VERSION 5.7 ;
  NOWIREEXTENSIONATPIN ON ;
  DIVIDERCHAR "/" ;
  BUSBITCHARS "[]" ;
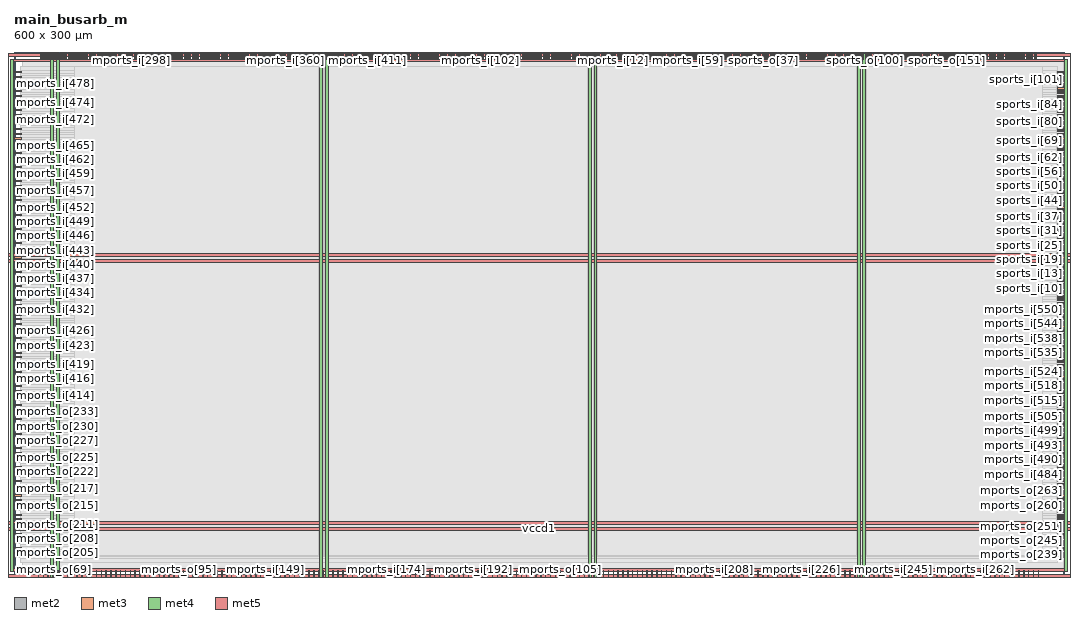
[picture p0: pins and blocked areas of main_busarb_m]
MACRO main_busarb_m
  CLASS BLOCK ;
  FOREIGN main_busarb_m ;
  ORIGIN 0.000 0.000 ;
  SIZE 600.000 BY 300.000 ;
  PIN clk_i
    DIRECTION INPUT ;
    USE SIGNAL ;
    ANTENNAGATEAREA 0.852000 ;
    ANTENNADIFFAREA 0.434700 ;
    PORT
      LAYER met2 ;
        RECT 13.890 0.000 14.170 4.000 ;
    END
  END clk_i
  PIN mports_i[0]
    DIRECTION INPUT ;
    USE SIGNAL ;
    ANTENNAGATEAREA 0.159000 ;
    PORT
      LAYER met2 ;
        RECT 330.830 296.000 331.110 300.000 ;
    END
  END mports_i[0]
  PIN mports_i[100]
    DIRECTION INPUT ;
    USE SIGNAL ;
    ANTENNAGATEAREA 0.196500 ;
    PORT
      LAYER met2 ;
        RECT 264.590 296.000 264.870 300.000 ;
    END
  END mports_i[100]
  PIN mports_i[101]
    DIRECTION INPUT ;
    USE SIGNAL ;
    ANTENNAGATEAREA 0.196500 ;
    PORT
      LAYER met2 ;
        RECT 265.510 296.000 265.790 300.000 ;
    END
  END mports_i[101]
  PIN mports_i[102]
    DIRECTION INPUT ;
    USE SIGNAL ;
    ANTENNAGATEAREA 0.126000 ;
    PORT
      LAYER met2 ;
        RECT 266.430 296.000 266.710 300.000 ;
    END
  END mports_i[102]
  PIN mports_i[103]
    DIRECTION INPUT ;
    USE SIGNAL ;
    ANTENNAGATEAREA 0.213000 ;
    PORT
      LAYER met2 ;
        RECT 267.350 296.000 267.630 300.000 ;
    END
  END mports_i[103]
  PIN mports_i[104]
    DIRECTION INPUT ;
    USE SIGNAL ;
    ANTENNAGATEAREA 0.159000 ;
    PORT
      LAYER met2 ;
        RECT 268.270 296.000 268.550 300.000 ;
    END
  END mports_i[104]
  PIN mports_i[105]
    DIRECTION INPUT ;
    USE SIGNAL ;
    ANTENNAGATEAREA 0.196500 ;
    PORT
      LAYER met2 ;
        RECT 269.190 296.000 269.470 300.000 ;
    END
  END mports_i[105]
  PIN mports_i[106]
    DIRECTION INPUT ;
    USE SIGNAL ;
    ANTENNAGATEAREA 0.196500 ;
    PORT
      LAYER met2 ;
        RECT 270.110 296.000 270.390 300.000 ;
    END
  END mports_i[106]
  PIN mports_i[107]
    DIRECTION INPUT ;
    USE SIGNAL ;
    ANTENNAGATEAREA 0.196500 ;
    PORT
      LAYER met2 ;
        RECT 271.030 296.000 271.310 300.000 ;
    END
  END mports_i[107]
  PIN mports_i[108]
    DIRECTION INPUT ;
    USE SIGNAL ;
    ANTENNAGATEAREA 0.196500 ;
    PORT
      LAYER met2 ;
        RECT 271.950 296.000 272.230 300.000 ;
    END
  END mports_i[108]
  PIN mports_i[109]
    DIRECTION INPUT ;
    USE SIGNAL ;
    ANTENNAGATEAREA 0.196500 ;
    PORT
      LAYER met2 ;
        RECT 272.870 296.000 273.150 300.000 ;
    END
  END mports_i[109]
  PIN mports_i[10]
    DIRECTION INPUT ;
    USE SIGNAL ;
    ANTENNAGATEAREA 0.159000 ;
    PORT
      LAYER met2 ;
        RECT 340.030 296.000 340.310 300.000 ;
    END
  END mports_i[10]
  PIN mports_i[110]
    DIRECTION INPUT ;
    USE SIGNAL ;
    ANTENNAGATEAREA 0.126000 ;
    PORT
      LAYER met2 ;
        RECT 273.790 296.000 274.070 300.000 ;
    END
  END mports_i[110]
  PIN mports_i[111]
    DIRECTION INPUT ;
    USE SIGNAL ;
    ANTENNAGATEAREA 0.196500 ;
    PORT
      LAYER met2 ;
        RECT 274.710 296.000 274.990 300.000 ;
    END
  END mports_i[111]
  PIN mports_i[112]
    DIRECTION INPUT ;
    USE SIGNAL ;
    ANTENNAGATEAREA 0.213000 ;
    PORT
      LAYER met2 ;
        RECT 275.630 296.000 275.910 300.000 ;
    END
  END mports_i[112]
  PIN mports_i[113]
    DIRECTION INPUT ;
    USE SIGNAL ;
    ANTENNAGATEAREA 0.213000 ;
    PORT
      LAYER met2 ;
        RECT 276.550 296.000 276.830 300.000 ;
    END
  END mports_i[113]
  PIN mports_i[114]
    DIRECTION INPUT ;
    USE SIGNAL ;
    ANTENNAGATEAREA 0.126000 ;
    PORT
      LAYER met2 ;
        RECT 277.470 296.000 277.750 300.000 ;
    END
  END mports_i[114]
  PIN mports_i[115]
    DIRECTION INPUT ;
    USE SIGNAL ;
    ANTENNAGATEAREA 0.159000 ;
    PORT
      LAYER met2 ;
        RECT 278.390 296.000 278.670 300.000 ;
    END
  END mports_i[115]
  PIN mports_i[116]
    DIRECTION INPUT ;
    USE SIGNAL ;
    ANTENNAGATEAREA 0.196500 ;
    PORT
      LAYER met2 ;
        RECT 279.310 296.000 279.590 300.000 ;
    END
  END mports_i[116]
  PIN mports_i[117]
    DIRECTION INPUT ;
    USE SIGNAL ;
    ANTENNAGATEAREA 0.196500 ;
    PORT
      LAYER met2 ;
        RECT 280.230 296.000 280.510 300.000 ;
    END
  END mports_i[117]
  PIN mports_i[118]
    DIRECTION INPUT ;
    USE SIGNAL ;
    ANTENNAGATEAREA 0.159000 ;
    PORT
      LAYER met2 ;
        RECT 281.150 296.000 281.430 300.000 ;
    END
  END mports_i[118]
  PIN mports_i[119]
    DIRECTION INPUT ;
    USE SIGNAL ;
    ANTENNAGATEAREA 0.196500 ;
    PORT
      LAYER met2 ;
        RECT 282.070 296.000 282.350 300.000 ;
    END
  END mports_i[119]
  PIN mports_i[11]
    DIRECTION INPUT ;
    USE SIGNAL ;
    ANTENNAGATEAREA 0.159000 ;
    PORT
      LAYER met2 ;
        RECT 340.950 296.000 341.230 300.000 ;
    END
  END mports_i[11]
  PIN mports_i[120]
    DIRECTION INPUT ;
    USE SIGNAL ;
    ANTENNAGATEAREA 0.196500 ;
    PORT
      LAYER met2 ;
        RECT 282.990 296.000 283.270 300.000 ;
    END
  END mports_i[120]
  PIN mports_i[121]
    DIRECTION INPUT ;
    USE SIGNAL ;
    ANTENNAGATEAREA 0.196500 ;
    PORT
      LAYER met2 ;
        RECT 283.910 296.000 284.190 300.000 ;
    END
  END mports_i[121]
  PIN mports_i[122]
    DIRECTION INPUT ;
    USE SIGNAL ;
    ANTENNAGATEAREA 0.213000 ;
    PORT
      LAYER met2 ;
        RECT 284.830 296.000 285.110 300.000 ;
    END
  END mports_i[122]
  PIN mports_i[123]
    DIRECTION INPUT ;
    USE SIGNAL ;
    ANTENNAGATEAREA 0.196500 ;
    PORT
      LAYER met2 ;
        RECT 285.750 296.000 286.030 300.000 ;
    END
  END mports_i[123]
  PIN mports_i[124]
    DIRECTION INPUT ;
    USE SIGNAL ;
    ANTENNAGATEAREA 0.196500 ;
    PORT
      LAYER met2 ;
        RECT 286.670 296.000 286.950 300.000 ;
    END
  END mports_i[124]
  PIN mports_i[125]
    DIRECTION INPUT ;
    USE SIGNAL ;
    ANTENNAGATEAREA 0.159000 ;
    PORT
      LAYER met2 ;
        RECT 287.590 296.000 287.870 300.000 ;
    END
  END mports_i[125]
  PIN mports_i[126]
    DIRECTION INPUT ;
    USE SIGNAL ;
    ANTENNAGATEAREA 0.196500 ;
    PORT
      LAYER met2 ;
        RECT 288.510 296.000 288.790 300.000 ;
    END
  END mports_i[126]
  PIN mports_i[127]
    DIRECTION INPUT ;
    USE SIGNAL ;
    ANTENNAGATEAREA 0.196500 ;
    PORT
      LAYER met2 ;
        RECT 289.430 296.000 289.710 300.000 ;
    END
  END mports_i[127]
  PIN mports_i[128]
    DIRECTION INPUT ;
    USE SIGNAL ;
    ANTENNAGATEAREA 0.126000 ;
    PORT
      LAYER met2 ;
        RECT 290.350 296.000 290.630 300.000 ;
    END
  END mports_i[128]
  PIN mports_i[129]
    DIRECTION INPUT ;
    USE SIGNAL ;
    ANTENNAGATEAREA 0.126000 ;
    PORT
      LAYER met2 ;
        RECT 291.270 296.000 291.550 300.000 ;
    END
  END mports_i[129]
  PIN mports_i[12]
    DIRECTION INPUT ;
    USE SIGNAL ;
    ANTENNAGATEAREA 0.159000 ;
    PORT
      LAYER met2 ;
        RECT 341.870 296.000 342.150 300.000 ;
    END
  END mports_i[12]
  PIN mports_i[130]
    DIRECTION INPUT ;
    USE SIGNAL ;
    ANTENNAGATEAREA 0.213000 ;
    PORT
      LAYER met2 ;
        RECT 292.190 296.000 292.470 300.000 ;
    END
  END mports_i[130]
  PIN mports_i[131]
    DIRECTION INPUT ;
    USE SIGNAL ;
    ANTENNAGATEAREA 0.159000 ;
    PORT
      LAYER met2 ;
        RECT 293.110 296.000 293.390 300.000 ;
    END
  END mports_i[131]
  PIN mports_i[132]
    DIRECTION INPUT ;
    USE SIGNAL ;
    ANTENNAGATEAREA 0.213000 ;
    PORT
      LAYER met2 ;
        RECT 294.030 296.000 294.310 300.000 ;
    END
  END mports_i[132]
  PIN mports_i[133]
    DIRECTION INPUT ;
    USE SIGNAL ;
    ANTENNAGATEAREA 0.247500 ;
    PORT
      LAYER met2 ;
        RECT 294.950 296.000 295.230 300.000 ;
    END
  END mports_i[133]
  PIN mports_i[134]
    DIRECTION INPUT ;
    USE SIGNAL ;
    ANTENNAGATEAREA 0.213000 ;
    PORT
      LAYER met2 ;
        RECT 295.870 296.000 296.150 300.000 ;
    END
  END mports_i[134]
  PIN mports_i[135]
    DIRECTION INPUT ;
    USE SIGNAL ;
    ANTENNAGATEAREA 0.213000 ;
    PORT
      LAYER met2 ;
        RECT 296.790 296.000 297.070 300.000 ;
    END
  END mports_i[135]
  PIN mports_i[136]
    DIRECTION INPUT ;
    USE SIGNAL ;
    ANTENNAGATEAREA 0.196500 ;
    PORT
      LAYER met2 ;
        RECT 297.710 296.000 297.990 300.000 ;
    END
  END mports_i[136]
  PIN mports_i[137]
    DIRECTION INPUT ;
    USE SIGNAL ;
    ANTENNAGATEAREA 0.126000 ;
    PORT
      LAYER met2 ;
        RECT 298.630 296.000 298.910 300.000 ;
    END
  END mports_i[137]
  PIN mports_i[138]
    DIRECTION INPUT ;
    USE SIGNAL ;
    ANTENNAGATEAREA 0.159000 ;
    PORT
      LAYER met2 ;
        RECT 113.250 0.000 113.530 4.000 ;
    END
  END mports_i[138]
  PIN mports_i[139]
    DIRECTION INPUT ;
    USE SIGNAL ;
    ANTENNAGATEAREA 0.159000 ;
    PORT
      LAYER met2 ;
        RECT 116.010 0.000 116.290 4.000 ;
    END
  END mports_i[139]
  PIN mports_i[13]
    DIRECTION INPUT ;
    USE SIGNAL ;
    ANTENNAGATEAREA 0.159000 ;
    PORT
      LAYER met2 ;
        RECT 342.790 296.000 343.070 300.000 ;
    END
  END mports_i[13]
  PIN mports_i[140]
    DIRECTION INPUT ;
    USE SIGNAL ;
    ANTENNAGATEAREA 0.213000 ;
    PORT
      LAYER met2 ;
        RECT 118.770 0.000 119.050 4.000 ;
    END
  END mports_i[140]
  PIN mports_i[141]
    DIRECTION INPUT ;
    USE SIGNAL ;
    ANTENNAGATEAREA 0.213000 ;
    PORT
      LAYER met2 ;
        RECT 121.530 0.000 121.810 4.000 ;
    END
  END mports_i[141]
  PIN mports_i[142]
    DIRECTION INPUT ;
    USE SIGNAL ;
    ANTENNAGATEAREA 0.159000 ;
    PORT
      LAYER met2 ;
        RECT 124.290 0.000 124.570 4.000 ;
    END
  END mports_i[142]
  PIN mports_i[143]
    DIRECTION INPUT ;
    USE SIGNAL ;
    ANTENNAGATEAREA 0.213000 ;
    PORT
      LAYER met2 ;
        RECT 127.050 0.000 127.330 4.000 ;
    END
  END mports_i[143]
  PIN mports_i[144]
    DIRECTION INPUT ;
    USE SIGNAL ;
    ANTENNAGATEAREA 0.159000 ;
    PORT
      LAYER met2 ;
        RECT 129.810 0.000 130.090 4.000 ;
    END
  END mports_i[144]
  PIN mports_i[145]
    DIRECTION INPUT ;
    USE SIGNAL ;
    ANTENNAGATEAREA 0.159000 ;
    PORT
      LAYER met2 ;
        RECT 132.570 0.000 132.850 4.000 ;
    END
  END mports_i[145]
  PIN mports_i[146]
    DIRECTION INPUT ;
    USE SIGNAL ;
    ANTENNAGATEAREA 0.213000 ;
    PORT
      LAYER met2 ;
        RECT 135.330 0.000 135.610 4.000 ;
    END
  END mports_i[146]
  PIN mports_i[147]
    DIRECTION INPUT ;
    USE SIGNAL ;
    ANTENNAGATEAREA 0.213000 ;
    PORT
      LAYER met2 ;
        RECT 138.090 0.000 138.370 4.000 ;
    END
  END mports_i[147]
  PIN mports_i[148]
    DIRECTION INPUT ;
    USE SIGNAL ;
    ANTENNAGATEAREA 0.213000 ;
    PORT
      LAYER met2 ;
        RECT 140.850 0.000 141.130 4.000 ;
    END
  END mports_i[148]
  PIN mports_i[149]
    DIRECTION INPUT ;
    USE SIGNAL ;
    ANTENNAGATEAREA 0.213000 ;
    PORT
      LAYER met2 ;
        RECT 143.610 0.000 143.890 4.000 ;
    END
  END mports_i[149]
  PIN mports_i[14]
    DIRECTION INPUT ;
    USE SIGNAL ;
    ANTENNAGATEAREA 0.159000 ;
    PORT
      LAYER met2 ;
        RECT 343.710 296.000 343.990 300.000 ;
    END
  END mports_i[14]
  PIN mports_i[150]
    DIRECTION INPUT ;
    USE SIGNAL ;
    ANTENNAGATEAREA 0.213000 ;
    PORT
      LAYER met2 ;
        RECT 146.370 0.000 146.650 4.000 ;
    END
  END mports_i[150]
  PIN mports_i[151]
    DIRECTION INPUT ;
    USE SIGNAL ;
    ANTENNAGATEAREA 0.213000 ;
    PORT
      LAYER met2 ;
        RECT 149.130 0.000 149.410 4.000 ;
    END
  END mports_i[151]
  PIN mports_i[152]
    DIRECTION INPUT ;
    USE SIGNAL ;
    ANTENNAGATEAREA 0.159000 ;
    PORT
      LAYER met2 ;
        RECT 151.890 0.000 152.170 4.000 ;
    END
  END mports_i[152]
  PIN mports_i[153]
    DIRECTION INPUT ;
    USE SIGNAL ;
    ANTENNAGATEAREA 0.213000 ;
    PORT
      LAYER met2 ;
        RECT 154.650 0.000 154.930 4.000 ;
    END
  END mports_i[153]
  PIN mports_i[154]
    DIRECTION INPUT ;
    USE SIGNAL ;
    ANTENNAGATEAREA 0.159000 ;
    PORT
      LAYER met2 ;
        RECT 157.410 0.000 157.690 4.000 ;
    END
  END mports_i[154]
  PIN mports_i[155]
    DIRECTION INPUT ;
    USE SIGNAL ;
    ANTENNAGATEAREA 0.159000 ;
    PORT
      LAYER met2 ;
        RECT 160.170 0.000 160.450 4.000 ;
    END
  END mports_i[155]
  PIN mports_i[156]
    DIRECTION INPUT ;
    USE SIGNAL ;
    ANTENNAGATEAREA 0.213000 ;
    PORT
      LAYER met2 ;
        RECT 162.930 0.000 163.210 4.000 ;
    END
  END mports_i[156]
  PIN mports_i[157]
    DIRECTION INPUT ;
    USE SIGNAL ;
    ANTENNAGATEAREA 0.213000 ;
    PORT
      LAYER met2 ;
        RECT 165.690 0.000 165.970 4.000 ;
    END
  END mports_i[157]
  PIN mports_i[158]
    DIRECTION INPUT ;
    USE SIGNAL ;
    ANTENNAGATEAREA 0.213000 ;
    PORT
      LAYER met2 ;
        RECT 168.450 0.000 168.730 4.000 ;
    END
  END mports_i[158]
  PIN mports_i[159]
    DIRECTION INPUT ;
    USE SIGNAL ;
    ANTENNAGATEAREA 0.213000 ;
    PORT
      LAYER met2 ;
        RECT 171.210 0.000 171.490 4.000 ;
    END
  END mports_i[159]
  PIN mports_i[15]
    DIRECTION INPUT ;
    USE SIGNAL ;
    ANTENNAGATEAREA 0.213000 ;
    PORT
      LAYER met2 ;
        RECT 344.630 296.000 344.910 300.000 ;
    END
  END mports_i[15]
  PIN mports_i[160]
    DIRECTION INPUT ;
    USE SIGNAL ;
    ANTENNAGATEAREA 0.159000 ;
    PORT
      LAYER met2 ;
        RECT 173.970 0.000 174.250 4.000 ;
    END
  END mports_i[160]
  PIN mports_i[161]
    DIRECTION INPUT ;
    USE SIGNAL ;
    ANTENNAGATEAREA 0.213000 ;
    PORT
      LAYER met2 ;
        RECT 176.730 0.000 177.010 4.000 ;
    END
  END mports_i[161]
  PIN mports_i[162]
    DIRECTION INPUT ;
    USE SIGNAL ;
    ANTENNAGATEAREA 0.213000 ;
    PORT
      LAYER met2 ;
        RECT 179.490 0.000 179.770 4.000 ;
    END
  END mports_i[162]
  PIN mports_i[163]
    DIRECTION INPUT ;
    USE SIGNAL ;
    ANTENNAGATEAREA 0.213000 ;
    PORT
      LAYER met2 ;
        RECT 182.250 0.000 182.530 4.000 ;
    END
  END mports_i[163]
  PIN mports_i[164]
    DIRECTION INPUT ;
    USE SIGNAL ;
    ANTENNAGATEAREA 0.213000 ;
    PORT
      LAYER met2 ;
        RECT 185.010 0.000 185.290 4.000 ;
    END
  END mports_i[164]
  PIN mports_i[165]
    DIRECTION INPUT ;
    USE SIGNAL ;
    ANTENNAGATEAREA 0.213000 ;
    PORT
      LAYER met2 ;
        RECT 187.770 0.000 188.050 4.000 ;
    END
  END mports_i[165]
  PIN mports_i[166]
    DIRECTION INPUT ;
    USE SIGNAL ;
    ANTENNAGATEAREA 0.213000 ;
    PORT
      LAYER met2 ;
        RECT 190.530 0.000 190.810 4.000 ;
    END
  END mports_i[166]
  PIN mports_i[167]
    DIRECTION INPUT ;
    USE SIGNAL ;
    ANTENNAGATEAREA 0.213000 ;
    PORT
      LAYER met2 ;
        RECT 193.290 0.000 193.570 4.000 ;
    END
  END mports_i[167]
  PIN mports_i[168]
    DIRECTION INPUT ;
    USE SIGNAL ;
    ANTENNAGATEAREA 0.159000 ;
    PORT
      LAYER met2 ;
        RECT 196.050 0.000 196.330 4.000 ;
    END
  END mports_i[168]
  PIN mports_i[169]
    DIRECTION INPUT ;
    USE SIGNAL ;
    ANTENNAGATEAREA 0.213000 ;
    PORT
      LAYER met2 ;
        RECT 198.810 0.000 199.090 4.000 ;
    END
  END mports_i[169]
  PIN mports_i[16]
    DIRECTION INPUT ;
    USE SIGNAL ;
    ANTENNAGATEAREA 0.213000 ;
    PORT
      LAYER met2 ;
        RECT 345.550 296.000 345.830 300.000 ;
    END
  END mports_i[16]
  PIN mports_i[170]
    DIRECTION INPUT ;
    USE SIGNAL ;
    ANTENNAGATEAREA 0.213000 ;
    PORT
      LAYER met2 ;
        RECT 201.570 0.000 201.850 4.000 ;
    END
  END mports_i[170]
  PIN mports_i[171]
    DIRECTION INPUT ;
    USE SIGNAL ;
    ANTENNAGATEAREA 0.213000 ;
    PORT
      LAYER met2 ;
        RECT 204.330 0.000 204.610 4.000 ;
    END
  END mports_i[171]
  PIN mports_i[172]
    DIRECTION INPUT ;
    USE SIGNAL ;
    ANTENNAGATEAREA 0.159000 ;
    PORT
      LAYER met2 ;
        RECT 207.090 0.000 207.370 4.000 ;
    END
  END mports_i[172]
  PIN mports_i[173]
    DIRECTION INPUT ;
    USE SIGNAL ;
    ANTENNAGATEAREA 0.213000 ;
    PORT
      LAYER met2 ;
        RECT 209.850 0.000 210.130 4.000 ;
    END
  END mports_i[173]
  PIN mports_i[174]
    DIRECTION INPUT ;
    USE SIGNAL ;
    ANTENNAGATEAREA 0.159000 ;
    PORT
      LAYER met2 ;
        RECT 212.610 0.000 212.890 4.000 ;
    END
  END mports_i[174]
  PIN mports_i[175]
    DIRECTION INPUT ;
    USE SIGNAL ;
    ANTENNAGATEAREA 0.159000 ;
    PORT
      LAYER met2 ;
        RECT 215.370 0.000 215.650 4.000 ;
    END
  END mports_i[175]
  PIN mports_i[176]
    DIRECTION INPUT ;
    USE SIGNAL ;
    ANTENNAGATEAREA 0.159000 ;
    PORT
      LAYER met2 ;
        RECT 218.130 0.000 218.410 4.000 ;
    END
  END mports_i[176]
  PIN mports_i[177]
    DIRECTION INPUT ;
    USE SIGNAL ;
    ANTENNAGATEAREA 0.213000 ;
    PORT
      LAYER met2 ;
        RECT 220.890 0.000 221.170 4.000 ;
    END
  END mports_i[177]
  PIN mports_i[178]
    DIRECTION INPUT ;
    USE SIGNAL ;
    ANTENNAGATEAREA 0.213000 ;
    PORT
      LAYER met2 ;
        RECT 223.650 0.000 223.930 4.000 ;
    END
  END mports_i[178]
  PIN mports_i[179]
    DIRECTION INPUT ;
    USE SIGNAL ;
    ANTENNAGATEAREA 0.159000 ;
    PORT
      LAYER met2 ;
        RECT 226.410 0.000 226.690 4.000 ;
    END
  END mports_i[179]
  PIN mports_i[17]
    DIRECTION INPUT ;
    USE SIGNAL ;
    ANTENNAGATEAREA 0.159000 ;
    PORT
      LAYER met2 ;
        RECT 346.470 296.000 346.750 300.000 ;
    END
  END mports_i[17]
  PIN mports_i[180]
    DIRECTION INPUT ;
    USE SIGNAL ;
    ANTENNAGATEAREA 0.159000 ;
    PORT
      LAYER met2 ;
        RECT 229.170 0.000 229.450 4.000 ;
    END
  END mports_i[180]
  PIN mports_i[181]
    DIRECTION INPUT ;
    USE SIGNAL ;
    ANTENNAGATEAREA 0.159000 ;
    PORT
      LAYER met2 ;
        RECT 231.930 0.000 232.210 4.000 ;
    END
  END mports_i[181]
  PIN mports_i[182]
    DIRECTION INPUT ;
    USE SIGNAL ;
    ANTENNAGATEAREA 0.159000 ;
    PORT
      LAYER met2 ;
        RECT 234.690 0.000 234.970 4.000 ;
    END
  END mports_i[182]
  PIN mports_i[183]
    DIRECTION INPUT ;
    USE SIGNAL ;
    ANTENNAGATEAREA 0.213000 ;
    PORT
      LAYER met2 ;
        RECT 237.450 0.000 237.730 4.000 ;
    END
  END mports_i[183]
  PIN mports_i[184]
    DIRECTION INPUT ;
    USE SIGNAL ;
    ANTENNAGATEAREA 0.213000 ;
    PORT
      LAYER met2 ;
        RECT 240.210 0.000 240.490 4.000 ;
    END
  END mports_i[184]
  PIN mports_i[185]
    DIRECTION INPUT ;
    USE SIGNAL ;
    ANTENNAGATEAREA 0.159000 ;
    PORT
      LAYER met2 ;
        RECT 242.970 0.000 243.250 4.000 ;
    END
  END mports_i[185]
  PIN mports_i[186]
    DIRECTION INPUT ;
    USE SIGNAL ;
    ANTENNAGATEAREA 0.159000 ;
    PORT
      LAYER met2 ;
        RECT 245.730 0.000 246.010 4.000 ;
    END
  END mports_i[186]
  PIN mports_i[187]
    DIRECTION INPUT ;
    USE SIGNAL ;
    ANTENNAGATEAREA 0.213000 ;
    PORT
      LAYER met2 ;
        RECT 248.490 0.000 248.770 4.000 ;
    END
  END mports_i[187]
  PIN mports_i[188]
    DIRECTION INPUT ;
    USE SIGNAL ;
    ANTENNAGATEAREA 0.213000 ;
    PORT
      LAYER met2 ;
        RECT 251.250 0.000 251.530 4.000 ;
    END
  END mports_i[188]
  PIN mports_i[189]
    DIRECTION INPUT ;
    USE SIGNAL ;
    ANTENNAGATEAREA 0.159000 ;
    PORT
      LAYER met2 ;
        RECT 254.010 0.000 254.290 4.000 ;
    END
  END mports_i[189]
  PIN mports_i[18]
    DIRECTION INPUT ;
    USE SIGNAL ;
    ANTENNAGATEAREA 0.159000 ;
    PORT
      LAYER met2 ;
        RECT 347.390 296.000 347.670 300.000 ;
    END
  END mports_i[18]
  PIN mports_i[190]
    DIRECTION INPUT ;
    USE SIGNAL ;
    ANTENNAGATEAREA 0.159000 ;
    PORT
      LAYER met2 ;
        RECT 256.770 0.000 257.050 4.000 ;
    END
  END mports_i[190]
  PIN mports_i[191]
    DIRECTION INPUT ;
    USE SIGNAL ;
    ANTENNAGATEAREA 0.159000 ;
    PORT
      LAYER met2 ;
        RECT 259.530 0.000 259.810 4.000 ;
    END
  END mports_i[191]
  PIN mports_i[192]
    DIRECTION INPUT ;
    USE SIGNAL ;
    ANTENNAGATEAREA 0.159000 ;
    PORT
      LAYER met2 ;
        RECT 262.290 0.000 262.570 4.000 ;
    END
  END mports_i[192]
  PIN mports_i[193]
    DIRECTION INPUT ;
    USE SIGNAL ;
    ANTENNAGATEAREA 0.159000 ;
    PORT
      LAYER met2 ;
        RECT 265.050 0.000 265.330 4.000 ;
    END
  END mports_i[193]
  PIN mports_i[194]
    DIRECTION INPUT ;
    USE SIGNAL ;
    ANTENNAGATEAREA 0.213000 ;
    PORT
      LAYER met2 ;
        RECT 267.810 0.000 268.090 4.000 ;
    END
  END mports_i[194]
  PIN mports_i[195]
    DIRECTION INPUT ;
    USE SIGNAL ;
    ANTENNAGATEAREA 0.159000 ;
    PORT
      LAYER met2 ;
        RECT 270.570 0.000 270.850 4.000 ;
    END
  END mports_i[195]
  PIN mports_i[196]
    DIRECTION INPUT ;
    USE SIGNAL ;
    ANTENNAGATEAREA 0.159000 ;
    PORT
      LAYER met2 ;
        RECT 273.330 0.000 273.610 4.000 ;
    END
  END mports_i[196]
  PIN mports_i[197]
    DIRECTION INPUT ;
    USE SIGNAL ;
    ANTENNAGATEAREA 0.213000 ;
    PORT
      LAYER met2 ;
        RECT 276.090 0.000 276.370 4.000 ;
    END
  END mports_i[197]
  PIN mports_i[198]
    DIRECTION INPUT ;
    USE SIGNAL ;
    ANTENNAGATEAREA 0.213000 ;
    PORT
      LAYER met2 ;
        RECT 278.850 0.000 279.130 4.000 ;
    END
  END mports_i[198]
  PIN mports_i[199]
    DIRECTION INPUT ;
    USE SIGNAL ;
    ANTENNAGATEAREA 0.213000 ;
    PORT
      LAYER met2 ;
        RECT 281.610 0.000 281.890 4.000 ;
    END
  END mports_i[199]
  PIN mports_i[19]
    DIRECTION INPUT ;
    USE SIGNAL ;
    ANTENNAGATEAREA 0.213000 ;
    PORT
      LAYER met2 ;
        RECT 348.310 296.000 348.590 300.000 ;
    END
  END mports_i[19]
  PIN mports_i[1]
    DIRECTION INPUT ;
    USE SIGNAL ;
    ANTENNAGATEAREA 0.159000 ;
    PORT
      LAYER met2 ;
        RECT 331.750 296.000 332.030 300.000 ;
    END
  END mports_i[1]
  PIN mports_i[200]
    DIRECTION INPUT ;
    USE SIGNAL ;
    ANTENNAGATEAREA 0.213000 ;
    PORT
      LAYER met2 ;
        RECT 284.370 0.000 284.650 4.000 ;
    END
  END mports_i[200]
  PIN mports_i[201]
    DIRECTION INPUT ;
    USE SIGNAL ;
    ANTENNAGATEAREA 0.159000 ;
    PORT
      LAYER met2 ;
        RECT 287.130 0.000 287.410 4.000 ;
    END
  END mports_i[201]
  PIN mports_i[202]
    DIRECTION INPUT ;
    USE SIGNAL ;
    ANTENNAGATEAREA 0.213000 ;
    PORT
      LAYER met2 ;
        RECT 289.890 0.000 290.170 4.000 ;
    END
  END mports_i[202]
  PIN mports_i[203]
    DIRECTION INPUT ;
    USE SIGNAL ;
    ANTENNAGATEAREA 0.213000 ;
    PORT
      LAYER met2 ;
        RECT 292.650 0.000 292.930 4.000 ;
    END
  END mports_i[203]
  PIN mports_i[204]
    DIRECTION INPUT ;
    USE SIGNAL ;
    ANTENNAGATEAREA 0.159000 ;
    PORT
      LAYER met2 ;
        RECT 295.410 0.000 295.690 4.000 ;
    END
  END mports_i[204]
  PIN mports_i[205]
    DIRECTION INPUT ;
    USE SIGNAL ;
    ANTENNAGATEAREA 0.159000 ;
    PORT
      LAYER met2 ;
        RECT 298.170 0.000 298.450 4.000 ;
    END
  END mports_i[205]
  PIN mports_i[206]
    DIRECTION INPUT ;
    USE SIGNAL ;
    ANTENNAGATEAREA 0.159000 ;
    PORT
      LAYER met2 ;
        RECT 300.930 0.000 301.210 4.000 ;
    END
  END mports_i[206]
  PIN mports_i[207]
    DIRECTION INPUT ;
    USE SIGNAL ;
    ANTENNAGATEAREA 0.247500 ;
    PORT
      LAYER met2 ;
        RECT 397.530 0.000 397.810 4.000 ;
    END
  END mports_i[207]
  PIN mports_i[208]
    DIRECTION INPUT ;
    USE SIGNAL ;
    ANTENNAGATEAREA 0.247500 ;
    PORT
      LAYER met2 ;
        RECT 400.290 0.000 400.570 4.000 ;
    END
  END mports_i[208]
  PIN mports_i[209]
    DIRECTION INPUT ;
    USE SIGNAL ;
    ANTENNAGATEAREA 0.247500 ;
    PORT
      LAYER met2 ;
        RECT 403.050 0.000 403.330 4.000 ;
    END
  END mports_i[209]
  PIN mports_i[20]
    DIRECTION INPUT ;
    USE SIGNAL ;
    ANTENNAGATEAREA 0.159000 ;
    PORT
      LAYER met2 ;
        RECT 349.230 296.000 349.510 300.000 ;
    END
  END mports_i[20]
  PIN mports_i[210]
    DIRECTION INPUT ;
    USE SIGNAL ;
    ANTENNAGATEAREA 0.213000 ;
    PORT
      LAYER met2 ;
        RECT 405.810 0.000 406.090 4.000 ;
    END
  END mports_i[210]
  PIN mports_i[211]
    DIRECTION INPUT ;
    USE SIGNAL ;
    ANTENNAGATEAREA 0.213000 ;
    PORT
      LAYER met2 ;
        RECT 408.570 0.000 408.850 4.000 ;
    END
  END mports_i[211]
  PIN mports_i[212]
    DIRECTION INPUT ;
    USE SIGNAL ;
    ANTENNAGATEAREA 0.247500 ;
    PORT
      LAYER met2 ;
        RECT 411.330 0.000 411.610 4.000 ;
    END
  END mports_i[212]
  PIN mports_i[213]
    DIRECTION INPUT ;
    USE SIGNAL ;
    ANTENNAGATEAREA 0.247500 ;
    PORT
      LAYER met2 ;
        RECT 414.090 0.000 414.370 4.000 ;
    END
  END mports_i[213]
  PIN mports_i[214]
    DIRECTION INPUT ;
    USE SIGNAL ;
    ANTENNAGATEAREA 0.247500 ;
    PORT
      LAYER met2 ;
        RECT 416.850 0.000 417.130 4.000 ;
    END
  END mports_i[214]
  PIN mports_i[215]
    DIRECTION INPUT ;
    USE SIGNAL ;
    ANTENNAGATEAREA 0.247500 ;
    PORT
      LAYER met2 ;
        RECT 419.610 0.000 419.890 4.000 ;
    END
  END mports_i[215]
  PIN mports_i[216]
    DIRECTION INPUT ;
    USE SIGNAL ;
    ANTENNAGATEAREA 0.159000 ;
    PORT
      LAYER met2 ;
        RECT 422.370 0.000 422.650 4.000 ;
    END
  END mports_i[216]
  PIN mports_i[217]
    DIRECTION INPUT ;
    USE SIGNAL ;
    ANTENNAGATEAREA 0.159000 ;
    PORT
      LAYER met2 ;
        RECT 425.130 0.000 425.410 4.000 ;
    END
  END mports_i[217]
  PIN mports_i[218]
    DIRECTION INPUT ;
    USE SIGNAL ;
    ANTENNAGATEAREA 0.213000 ;
    PORT
      LAYER met2 ;
        RECT 427.890 0.000 428.170 4.000 ;
    END
  END mports_i[218]
  PIN mports_i[219]
    DIRECTION INPUT ;
    USE SIGNAL ;
    ANTENNAGATEAREA 0.213000 ;
    PORT
      LAYER met2 ;
        RECT 430.650 0.000 430.930 4.000 ;
    END
  END mports_i[219]
  PIN mports_i[21]
    DIRECTION INPUT ;
    USE SIGNAL ;
    ANTENNAGATEAREA 0.159000 ;
    PORT
      LAYER met2 ;
        RECT 350.150 296.000 350.430 300.000 ;
    END
  END mports_i[21]
  PIN mports_i[220]
    DIRECTION INPUT ;
    USE SIGNAL ;
    ANTENNAGATEAREA 0.213000 ;
    PORT
      LAYER met2 ;
        RECT 433.410 0.000 433.690 4.000 ;
    END
  END mports_i[220]
  PIN mports_i[221]
    DIRECTION INPUT ;
    USE SIGNAL ;
    ANTENNAGATEAREA 0.247500 ;
    PORT
      LAYER met2 ;
        RECT 436.170 0.000 436.450 4.000 ;
    END
  END mports_i[221]
  PIN mports_i[222]
    DIRECTION INPUT ;
    USE SIGNAL ;
    ANTENNAGATEAREA 0.213000 ;
    PORT
      LAYER met2 ;
        RECT 438.930 0.000 439.210 4.000 ;
    END
  END mports_i[222]
  PIN mports_i[223]
    DIRECTION INPUT ;
    USE SIGNAL ;
    ANTENNAGATEAREA 0.126000 ;
    PORT
      LAYER met2 ;
        RECT 441.690 0.000 441.970 4.000 ;
    END
  END mports_i[223]
  PIN mports_i[224]
    DIRECTION INPUT ;
    USE SIGNAL ;
    ANTENNAGATEAREA 0.247500 ;
    PORT
      LAYER met2 ;
        RECT 444.450 0.000 444.730 4.000 ;
    END
  END mports_i[224]
  PIN mports_i[225]
    DIRECTION INPUT ;
    USE SIGNAL ;
    ANTENNAGATEAREA 0.213000 ;
    PORT
      LAYER met2 ;
        RECT 447.210 0.000 447.490 4.000 ;
    END
  END mports_i[225]
  PIN mports_i[226]
    DIRECTION INPUT ;
    USE SIGNAL ;
    ANTENNAGATEAREA 0.159000 ;
    PORT
      LAYER met2 ;
        RECT 449.970 0.000 450.250 4.000 ;
    END
  END mports_i[226]
  PIN mports_i[227]
    DIRECTION INPUT ;
    USE SIGNAL ;
    ANTENNAGATEAREA 0.247500 ;
    PORT
      LAYER met2 ;
        RECT 452.730 0.000 453.010 4.000 ;
    END
  END mports_i[227]
  PIN mports_i[228]
    DIRECTION INPUT ;
    USE SIGNAL ;
    ANTENNAGATEAREA 0.213000 ;
    PORT
      LAYER met2 ;
        RECT 455.490 0.000 455.770 4.000 ;
    END
  END mports_i[228]
  PIN mports_i[229]
    DIRECTION INPUT ;
    USE SIGNAL ;
    ANTENNAGATEAREA 0.247500 ;
    PORT
      LAYER met2 ;
        RECT 458.250 0.000 458.530 4.000 ;
    END
  END mports_i[229]
  PIN mports_i[22]
    DIRECTION INPUT ;
    USE SIGNAL ;
    ANTENNAGATEAREA 0.213000 ;
    PORT
      LAYER met2 ;
        RECT 351.070 296.000 351.350 300.000 ;
    END
  END mports_i[22]
  PIN mports_i[230]
    DIRECTION INPUT ;
    USE SIGNAL ;
    ANTENNAGATEAREA 0.247500 ;
    PORT
      LAYER met2 ;
        RECT 461.010 0.000 461.290 4.000 ;
    END
  END mports_i[230]
  PIN mports_i[231]
    DIRECTION INPUT ;
    USE SIGNAL ;
    ANTENNAGATEAREA 0.213000 ;
    PORT
      LAYER met2 ;
        RECT 463.770 0.000 464.050 4.000 ;
    END
  END mports_i[231]
  PIN mports_i[232]
    DIRECTION INPUT ;
    USE SIGNAL ;
    ANTENNAGATEAREA 0.213000 ;
    PORT
      LAYER met2 ;
        RECT 466.530 0.000 466.810 4.000 ;
    END
  END mports_i[232]
  PIN mports_i[233]
    DIRECTION INPUT ;
    USE SIGNAL ;
    ANTENNAGATEAREA 0.159000 ;
    PORT
      LAYER met2 ;
        RECT 469.290 0.000 469.570 4.000 ;
    END
  END mports_i[233]
  PIN mports_i[234]
    DIRECTION INPUT ;
    USE SIGNAL ;
    ANTENNAGATEAREA 0.159000 ;
    PORT
      LAYER met2 ;
        RECT 472.050 0.000 472.330 4.000 ;
    END
  END mports_i[234]
  PIN mports_i[235]
    DIRECTION INPUT ;
    USE SIGNAL ;
    ANTENNAGATEAREA 0.213000 ;
    PORT
      LAYER met2 ;
        RECT 474.810 0.000 475.090 4.000 ;
    END
  END mports_i[235]
  PIN mports_i[236]
    DIRECTION INPUT ;
    USE SIGNAL ;
    ANTENNAGATEAREA 0.213000 ;
    PORT
      LAYER met2 ;
        RECT 477.570 0.000 477.850 4.000 ;
    END
  END mports_i[236]
  PIN mports_i[237]
    DIRECTION INPUT ;
    USE SIGNAL ;
    ANTENNAGATEAREA 0.213000 ;
    PORT
      LAYER met2 ;
        RECT 480.330 0.000 480.610 4.000 ;
    END
  END mports_i[237]
  PIN mports_i[238]
    DIRECTION INPUT ;
    USE SIGNAL ;
    ANTENNAGATEAREA 0.213000 ;
    PORT
      LAYER met2 ;
        RECT 483.090 0.000 483.370 4.000 ;
    END
  END mports_i[238]
  PIN mports_i[239]
    DIRECTION INPUT ;
    USE SIGNAL ;
    ANTENNAGATEAREA 0.213000 ;
    PORT
      LAYER met2 ;
        RECT 485.850 0.000 486.130 4.000 ;
    END
  END mports_i[239]
  PIN mports_i[23]
    DIRECTION INPUT ;
    USE SIGNAL ;
    ANTENNAGATEAREA 0.213000 ;
    PORT
      LAYER met2 ;
        RECT 351.990 296.000 352.270 300.000 ;
    END
  END mports_i[23]
  PIN mports_i[240]
    DIRECTION INPUT ;
    USE SIGNAL ;
    ANTENNAGATEAREA 0.213000 ;
    PORT
      LAYER met2 ;
        RECT 488.610 0.000 488.890 4.000 ;
    END
  END mports_i[240]
  PIN mports_i[241]
    DIRECTION INPUT ;
    USE SIGNAL ;
    ANTENNAGATEAREA 0.159000 ;
    PORT
      LAYER met2 ;
        RECT 491.370 0.000 491.650 4.000 ;
    END
  END mports_i[241]
  PIN mports_i[242]
    DIRECTION INPUT ;
    USE SIGNAL ;
    ANTENNAGATEAREA 0.213000 ;
    PORT
      LAYER met2 ;
        RECT 494.130 0.000 494.410 4.000 ;
    END
  END mports_i[242]
  PIN mports_i[243]
    DIRECTION INPUT ;
    USE SIGNAL ;
    ANTENNAGATEAREA 0.247500 ;
    PORT
      LAYER met2 ;
        RECT 496.890 0.000 497.170 4.000 ;
    END
  END mports_i[243]
  PIN mports_i[244]
    DIRECTION INPUT ;
    USE SIGNAL ;
    ANTENNAGATEAREA 0.247500 ;
    PORT
      LAYER met2 ;
        RECT 499.650 0.000 499.930 4.000 ;
    END
  END mports_i[244]
  PIN mports_i[245]
    DIRECTION INPUT ;
    USE SIGNAL ;
    ANTENNAGATEAREA 0.213000 ;
    PORT
      LAYER met2 ;
        RECT 502.410 0.000 502.690 4.000 ;
    END
  END mports_i[245]
  PIN mports_i[246]
    DIRECTION INPUT ;
    USE SIGNAL ;
    ANTENNAGATEAREA 0.247500 ;
    PORT
      LAYER met2 ;
        RECT 505.170 0.000 505.450 4.000 ;
    END
  END mports_i[246]
  PIN mports_i[247]
    DIRECTION INPUT ;
    USE SIGNAL ;
    ANTENNAGATEAREA 0.213000 ;
    PORT
      LAYER met2 ;
        RECT 507.930 0.000 508.210 4.000 ;
    END
  END mports_i[247]
  PIN mports_i[248]
    DIRECTION INPUT ;
    USE SIGNAL ;
    ANTENNAGATEAREA 0.213000 ;
    PORT
      LAYER met2 ;
        RECT 510.690 0.000 510.970 4.000 ;
    END
  END mports_i[248]
  PIN mports_i[249]
    DIRECTION INPUT ;
    USE SIGNAL ;
    ANTENNAGATEAREA 0.213000 ;
    PORT
      LAYER met2 ;
        RECT 513.450 0.000 513.730 4.000 ;
    END
  END mports_i[249]
  PIN mports_i[24]
    DIRECTION INPUT ;
    USE SIGNAL ;
    ANTENNAGATEAREA 0.159000 ;
    PORT
      LAYER met2 ;
        RECT 352.910 296.000 353.190 300.000 ;
    END
  END mports_i[24]
  PIN mports_i[250]
    DIRECTION INPUT ;
    USE SIGNAL ;
    ANTENNAGATEAREA 0.213000 ;
    PORT
      LAYER met2 ;
        RECT 516.210 0.000 516.490 4.000 ;
    END
  END mports_i[250]
  PIN mports_i[251]
    DIRECTION INPUT ;
    USE SIGNAL ;
    ANTENNAGATEAREA 0.159000 ;
    PORT
      LAYER met2 ;
        RECT 518.970 0.000 519.250 4.000 ;
    END
  END mports_i[251]
  PIN mports_i[252]
    DIRECTION INPUT ;
    USE SIGNAL ;
    ANTENNAGATEAREA 0.213000 ;
    PORT
      LAYER met2 ;
        RECT 521.730 0.000 522.010 4.000 ;
    END
  END mports_i[252]
  PIN mports_i[253]
    DIRECTION INPUT ;
    USE SIGNAL ;
    ANTENNAGATEAREA 0.159000 ;
    PORT
      LAYER met2 ;
        RECT 524.490 0.000 524.770 4.000 ;
    END
  END mports_i[253]
  PIN mports_i[254]
    DIRECTION INPUT ;
    USE SIGNAL ;
    ANTENNAGATEAREA 0.247500 ;
    PORT
      LAYER met2 ;
        RECT 527.250 0.000 527.530 4.000 ;
    END
  END mports_i[254]
  PIN mports_i[255]
    DIRECTION INPUT ;
    USE SIGNAL ;
    ANTENNAGATEAREA 0.213000 ;
    PORT
      LAYER met2 ;
        RECT 530.010 0.000 530.290 4.000 ;
    END
  END mports_i[255]
  PIN mports_i[256]
    DIRECTION INPUT ;
    USE SIGNAL ;
    ANTENNAGATEAREA 0.159000 ;
    PORT
      LAYER met2 ;
        RECT 532.770 0.000 533.050 4.000 ;
    END
  END mports_i[256]
  PIN mports_i[257]
    DIRECTION INPUT ;
    USE SIGNAL ;
    ANTENNAGATEAREA 0.213000 ;
    PORT
      LAYER met2 ;
        RECT 535.530 0.000 535.810 4.000 ;
    END
  END mports_i[257]
  PIN mports_i[258]
    DIRECTION INPUT ;
    USE SIGNAL ;
    ANTENNAGATEAREA 0.247500 ;
    PORT
      LAYER met2 ;
        RECT 538.290 0.000 538.570 4.000 ;
    END
  END mports_i[258]
  PIN mports_i[259]
    DIRECTION INPUT ;
    USE SIGNAL ;
    ANTENNAGATEAREA 0.247500 ;
    PORT
      LAYER met2 ;
        RECT 541.050 0.000 541.330 4.000 ;
    END
  END mports_i[259]
  PIN mports_i[25]
    DIRECTION INPUT ;
    USE SIGNAL ;
    ANTENNAGATEAREA 0.159000 ;
    PORT
      LAYER met2 ;
        RECT 353.830 296.000 354.110 300.000 ;
    END
  END mports_i[25]
  PIN mports_i[260]
    DIRECTION INPUT ;
    USE SIGNAL ;
    ANTENNAGATEAREA 0.213000 ;
    PORT
      LAYER met2 ;
        RECT 543.810 0.000 544.090 4.000 ;
    END
  END mports_i[260]
  PIN mports_i[261]
    DIRECTION INPUT ;
    USE SIGNAL ;
    ANTENNAGATEAREA 0.247500 ;
    PORT
      LAYER met2 ;
        RECT 546.570 0.000 546.850 4.000 ;
    END
  END mports_i[261]
  PIN mports_i[262]
    DIRECTION INPUT ;
    USE SIGNAL ;
    ANTENNAGATEAREA 0.213000 ;
    PORT
      LAYER met2 ;
        RECT 549.330 0.000 549.610 4.000 ;
    END
  END mports_i[262]
  PIN mports_i[263]
    DIRECTION INPUT ;
    USE SIGNAL ;
    ANTENNAGATEAREA 0.159000 ;
    PORT
      LAYER met2 ;
        RECT 552.090 0.000 552.370 4.000 ;
    END
  END mports_i[263]
  PIN mports_i[264]
    DIRECTION INPUT ;
    USE SIGNAL ;
    ANTENNAGATEAREA 0.247500 ;
    PORT
      LAYER met2 ;
        RECT 554.850 0.000 555.130 4.000 ;
    END
  END mports_i[264]
  PIN mports_i[265]
    DIRECTION INPUT ;
    USE SIGNAL ;
    ANTENNAGATEAREA 0.247500 ;
    PORT
      LAYER met2 ;
        RECT 557.610 0.000 557.890 4.000 ;
    END
  END mports_i[265]
  PIN mports_i[266]
    DIRECTION INPUT ;
    USE SIGNAL ;
    ANTENNAGATEAREA 0.213000 ;
    PORT
      LAYER met2 ;
        RECT 560.370 0.000 560.650 4.000 ;
    END
  END mports_i[266]
  PIN mports_i[267]
    DIRECTION INPUT ;
    USE SIGNAL ;
    ANTENNAGATEAREA 0.213000 ;
    PORT
      LAYER met2 ;
        RECT 563.130 0.000 563.410 4.000 ;
    END
  END mports_i[267]
  PIN mports_i[268]
    DIRECTION INPUT ;
    USE SIGNAL ;
    ANTENNAGATEAREA 0.213000 ;
    PORT
      LAYER met2 ;
        RECT 565.890 0.000 566.170 4.000 ;
    END
  END mports_i[268]
  PIN mports_i[269]
    DIRECTION INPUT ;
    USE SIGNAL ;
    ANTENNAGATEAREA 0.159000 ;
    PORT
      LAYER met2 ;
        RECT 568.650 0.000 568.930 4.000 ;
    END
  END mports_i[269]
  PIN mports_i[26]
    DIRECTION INPUT ;
    USE SIGNAL ;
    ANTENNAGATEAREA 0.213000 ;
    PORT
      LAYER met2 ;
        RECT 354.750 296.000 355.030 300.000 ;
    END
  END mports_i[26]
  PIN mports_i[270]
    DIRECTION INPUT ;
    USE SIGNAL ;
    ANTENNAGATEAREA 0.159000 ;
    PORT
      LAYER met2 ;
        RECT 571.410 0.000 571.690 4.000 ;
    END
  END mports_i[270]
  PIN mports_i[271]
    DIRECTION INPUT ;
    USE SIGNAL ;
    ANTENNAGATEAREA 0.247500 ;
    PORT
      LAYER met2 ;
        RECT 574.170 0.000 574.450 4.000 ;
    END
  END mports_i[271]
  PIN mports_i[272]
    DIRECTION INPUT ;
    USE SIGNAL ;
    ANTENNAGATEAREA 0.213000 ;
    PORT
      LAYER met2 ;
        RECT 576.930 0.000 577.210 4.000 ;
    END
  END mports_i[272]
  PIN mports_i[273]
    DIRECTION INPUT ;
    USE SIGNAL ;
    ANTENNAGATEAREA 0.213000 ;
    PORT
      LAYER met2 ;
        RECT 579.690 0.000 579.970 4.000 ;
    END
  END mports_i[273]
  PIN mports_i[274]
    DIRECTION INPUT ;
    USE SIGNAL ;
    ANTENNAGATEAREA 0.213000 ;
    PORT
      LAYER met2 ;
        RECT 582.450 0.000 582.730 4.000 ;
    END
  END mports_i[274]
  PIN mports_i[275]
    DIRECTION INPUT ;
    USE SIGNAL ;
    ANTENNAGATEAREA 0.213000 ;
    PORT
      LAYER met2 ;
        RECT 585.210 0.000 585.490 4.000 ;
    END
  END mports_i[275]
  PIN mports_i[276]
    DIRECTION INPUT ;
    USE SIGNAL ;
    ANTENNAGATEAREA 0.196500 ;
    PORT
      LAYER met2 ;
        RECT 46.550 296.000 46.830 300.000 ;
    END
  END mports_i[276]
  PIN mports_i[277]
    DIRECTION INPUT ;
    USE SIGNAL ;
    ANTENNAGATEAREA 0.196500 ;
    PORT
      LAYER met2 ;
        RECT 47.470 296.000 47.750 300.000 ;
    END
  END mports_i[277]
  PIN mports_i[278]
    DIRECTION INPUT ;
    USE SIGNAL ;
    ANTENNAGATEAREA 0.126000 ;
    PORT
      LAYER met2 ;
        RECT 48.390 296.000 48.670 300.000 ;
    END
  END mports_i[278]
  PIN mports_i[279]
    DIRECTION INPUT ;
    USE SIGNAL ;
    ANTENNAGATEAREA 0.213000 ;
    PORT
      LAYER met2 ;
        RECT 49.310 296.000 49.590 300.000 ;
    END
  END mports_i[279]
  PIN mports_i[27]
    DIRECTION INPUT ;
    USE SIGNAL ;
    ANTENNAGATEAREA 0.159000 ;
    PORT
      LAYER met2 ;
        RECT 355.670 296.000 355.950 300.000 ;
    END
  END mports_i[27]
  PIN mports_i[280]
    DIRECTION INPUT ;
    USE SIGNAL ;
    ANTENNAGATEAREA 0.213000 ;
    PORT
      LAYER met2 ;
        RECT 50.230 296.000 50.510 300.000 ;
    END
  END mports_i[280]
  PIN mports_i[281]
    DIRECTION INPUT ;
    USE SIGNAL ;
    ANTENNAGATEAREA 0.196500 ;
    PORT
      LAYER met2 ;
        RECT 51.150 296.000 51.430 300.000 ;
    END
  END mports_i[281]
  PIN mports_i[282]
    DIRECTION INPUT ;
    USE SIGNAL ;
    ANTENNAGATEAREA 0.196500 ;
    PORT
      LAYER met2 ;
        RECT 52.070 296.000 52.350 300.000 ;
    END
  END mports_i[282]
  PIN mports_i[283]
    DIRECTION INPUT ;
    USE SIGNAL ;
    ANTENNAGATEAREA 0.196500 ;
    PORT
      LAYER met2 ;
        RECT 52.990 296.000 53.270 300.000 ;
    END
  END mports_i[283]
  PIN mports_i[284]
    DIRECTION INPUT ;
    USE SIGNAL ;
    ANTENNAGATEAREA 0.196500 ;
    PORT
      LAYER met2 ;
        RECT 53.910 296.000 54.190 300.000 ;
    END
  END mports_i[284]
  PIN mports_i[285]
    DIRECTION INPUT ;
    USE SIGNAL ;
    ANTENNAGATEAREA 0.159000 ;
    PORT
      LAYER met2 ;
        RECT 54.830 296.000 55.110 300.000 ;
    END
  END mports_i[285]
  PIN mports_i[286]
    DIRECTION INPUT ;
    USE SIGNAL ;
    ANTENNAGATEAREA 0.159000 ;
    PORT
      LAYER met2 ;
        RECT 55.750 296.000 56.030 300.000 ;
    END
  END mports_i[286]
  PIN mports_i[287]
    DIRECTION INPUT ;
    USE SIGNAL ;
    ANTENNAGATEAREA 0.213000 ;
    PORT
      LAYER met2 ;
        RECT 56.670 296.000 56.950 300.000 ;
    END
  END mports_i[287]
  PIN mports_i[288]
    DIRECTION INPUT ;
    USE SIGNAL ;
    ANTENNAGATEAREA 0.126000 ;
    PORT
      LAYER met2 ;
        RECT 57.590 296.000 57.870 300.000 ;
    END
  END mports_i[288]
  PIN mports_i[289]
    DIRECTION INPUT ;
    USE SIGNAL ;
    ANTENNAGATEAREA 0.213000 ;
    PORT
      LAYER met2 ;
        RECT 58.510 296.000 58.790 300.000 ;
    END
  END mports_i[289]
  PIN mports_i[28]
    DIRECTION INPUT ;
    USE SIGNAL ;
    ANTENNAGATEAREA 0.213000 ;
    PORT
      LAYER met2 ;
        RECT 356.590 296.000 356.870 300.000 ;
    END
  END mports_i[28]
  PIN mports_i[290]
    DIRECTION INPUT ;
    USE SIGNAL ;
    ANTENNAGATEAREA 0.196500 ;
    PORT
      LAYER met2 ;
        RECT 59.430 296.000 59.710 300.000 ;
    END
  END mports_i[290]
  PIN mports_i[291]
    DIRECTION INPUT ;
    USE SIGNAL ;
    ANTENNAGATEAREA 0.213000 ;
    PORT
      LAYER met2 ;
        RECT 60.350 296.000 60.630 300.000 ;
    END
  END mports_i[291]
  PIN mports_i[292]
    DIRECTION INPUT ;
    USE SIGNAL ;
    ANTENNAGATEAREA 0.247500 ;
    PORT
      LAYER met2 ;
        RECT 61.270 296.000 61.550 300.000 ;
    END
  END mports_i[292]
  PIN mports_i[293]
    DIRECTION INPUT ;
    USE SIGNAL ;
    ANTENNAGATEAREA 0.196500 ;
    PORT
      LAYER met2 ;
        RECT 62.190 296.000 62.470 300.000 ;
    END
  END mports_i[293]
  PIN mports_i[294]
    DIRECTION INPUT ;
    USE SIGNAL ;
    ANTENNAGATEAREA 0.159000 ;
    PORT
      LAYER met2 ;
        RECT 63.110 296.000 63.390 300.000 ;
    END
  END mports_i[294]
  PIN mports_i[295]
    DIRECTION INPUT ;
    USE SIGNAL ;
    ANTENNAGATEAREA 0.159000 ;
    PORT
      LAYER met2 ;
        RECT 64.030 296.000 64.310 300.000 ;
    END
  END mports_i[295]
  PIN mports_i[296]
    DIRECTION INPUT ;
    USE SIGNAL ;
    ANTENNAGATEAREA 0.213000 ;
    PORT
      LAYER met2 ;
        RECT 64.950 296.000 65.230 300.000 ;
    END
  END mports_i[296]
  PIN mports_i[297]
    DIRECTION INPUT ;
    USE SIGNAL ;
    ANTENNAGATEAREA 0.213000 ;
    PORT
      LAYER met2 ;
        RECT 65.870 296.000 66.150 300.000 ;
    END
  END mports_i[297]
  PIN mports_i[298]
    DIRECTION INPUT ;
    USE SIGNAL ;
    ANTENNAGATEAREA 0.126000 ;
    PORT
      LAYER met2 ;
        RECT 66.790 296.000 67.070 300.000 ;
    END
  END mports_i[298]
  PIN mports_i[299]
    DIRECTION INPUT ;
    USE SIGNAL ;
    ANTENNAGATEAREA 0.126000 ;
    PORT
      LAYER met2 ;
        RECT 67.710 296.000 67.990 300.000 ;
    END
  END mports_i[299]
  PIN mports_i[29]
    DIRECTION INPUT ;
    USE SIGNAL ;
    ANTENNAGATEAREA 0.213000 ;
    PORT
      LAYER met2 ;
        RECT 357.510 296.000 357.790 300.000 ;
    END
  END mports_i[29]
  PIN mports_i[2]
    DIRECTION INPUT ;
    USE SIGNAL ;
    ANTENNAGATEAREA 0.213000 ;
    PORT
      LAYER met2 ;
        RECT 332.670 296.000 332.950 300.000 ;
    END
  END mports_i[2]
  PIN mports_i[300]
    DIRECTION INPUT ;
    USE SIGNAL ;
    ANTENNAGATEAREA 0.213000 ;
    PORT
      LAYER met2 ;
        RECT 68.630 296.000 68.910 300.000 ;
    END
  END mports_i[300]
  PIN mports_i[301]
    DIRECTION INPUT ;
    USE SIGNAL ;
    ANTENNAGATEAREA 0.213000 ;
    PORT
      LAYER met2 ;
        RECT 69.550 296.000 69.830 300.000 ;
    END
  END mports_i[301]
  PIN mports_i[302]
    DIRECTION INPUT ;
    USE SIGNAL ;
    ANTENNAGATEAREA 0.213000 ;
    PORT
      LAYER met2 ;
        RECT 70.470 296.000 70.750 300.000 ;
    END
  END mports_i[302]
  PIN mports_i[303]
    DIRECTION INPUT ;
    USE SIGNAL ;
    ANTENNAGATEAREA 0.213000 ;
    PORT
      LAYER met2 ;
        RECT 71.390 296.000 71.670 300.000 ;
    END
  END mports_i[303]
  PIN mports_i[304]
    DIRECTION INPUT ;
    USE SIGNAL ;
    ANTENNAGATEAREA 0.159000 ;
    PORT
      LAYER met2 ;
        RECT 72.310 296.000 72.590 300.000 ;
    END
  END mports_i[304]
  PIN mports_i[305]
    DIRECTION INPUT ;
    USE SIGNAL ;
    ANTENNAGATEAREA 0.159000 ;
    PORT
      LAYER met2 ;
        RECT 73.230 296.000 73.510 300.000 ;
    END
  END mports_i[305]
  PIN mports_i[306]
    DIRECTION INPUT ;
    USE SIGNAL ;
    ANTENNAGATEAREA 0.159000 ;
    PORT
      LAYER met2 ;
        RECT 74.150 296.000 74.430 300.000 ;
    END
  END mports_i[306]
  PIN mports_i[307]
    DIRECTION INPUT ;
    USE SIGNAL ;
    ANTENNAGATEAREA 0.159000 ;
    PORT
      LAYER met2 ;
        RECT 75.070 296.000 75.350 300.000 ;
    END
  END mports_i[307]
  PIN mports_i[308]
    DIRECTION INPUT ;
    USE SIGNAL ;
    ANTENNAGATEAREA 0.159000 ;
    PORT
      LAYER met2 ;
        RECT 75.990 296.000 76.270 300.000 ;
    END
  END mports_i[308]
  PIN mports_i[309]
    DIRECTION INPUT ;
    USE SIGNAL ;
    ANTENNAGATEAREA 0.213000 ;
    PORT
      LAYER met2 ;
        RECT 76.910 296.000 77.190 300.000 ;
    END
  END mports_i[309]
  PIN mports_i[30]
    DIRECTION INPUT ;
    USE SIGNAL ;
    ANTENNAGATEAREA 0.213000 ;
    PORT
      LAYER met2 ;
        RECT 358.430 296.000 358.710 300.000 ;
    END
  END mports_i[30]
  PIN mports_i[310]
    DIRECTION INPUT ;
    USE SIGNAL ;
    ANTENNAGATEAREA 0.213000 ;
    PORT
      LAYER met2 ;
        RECT 77.830 296.000 78.110 300.000 ;
    END
  END mports_i[310]
  PIN mports_i[311]
    DIRECTION INPUT ;
    USE SIGNAL ;
    ANTENNAGATEAREA 0.213000 ;
    PORT
      LAYER met2 ;
        RECT 78.750 296.000 79.030 300.000 ;
    END
  END mports_i[311]
  PIN mports_i[312]
    DIRECTION INPUT ;
    USE SIGNAL ;
    ANTENNAGATEAREA 0.213000 ;
    PORT
      LAYER met2 ;
        RECT 79.670 296.000 79.950 300.000 ;
    END
  END mports_i[312]
  PIN mports_i[313]
    DIRECTION INPUT ;
    USE SIGNAL ;
    ANTENNAGATEAREA 0.126000 ;
    PORT
      LAYER met2 ;
        RECT 80.590 296.000 80.870 300.000 ;
    END
  END mports_i[313]
  PIN mports_i[314]
    DIRECTION INPUT ;
    USE SIGNAL ;
    ANTENNAGATEAREA 0.213000 ;
    PORT
      LAYER met2 ;
        RECT 81.510 296.000 81.790 300.000 ;
    END
  END mports_i[314]
  PIN mports_i[315]
    DIRECTION INPUT ;
    USE SIGNAL ;
    ANTENNAGATEAREA 0.213000 ;
    PORT
      LAYER met2 ;
        RECT 82.430 296.000 82.710 300.000 ;
    END
  END mports_i[315]
  PIN mports_i[316]
    DIRECTION INPUT ;
    USE SIGNAL ;
    ANTENNAGATEAREA 0.213000 ;
    PORT
      LAYER met2 ;
        RECT 83.350 296.000 83.630 300.000 ;
    END
  END mports_i[316]
  PIN mports_i[317]
    DIRECTION INPUT ;
    USE SIGNAL ;
    ANTENNAGATEAREA 0.159000 ;
    PORT
      LAYER met2 ;
        RECT 84.270 296.000 84.550 300.000 ;
    END
  END mports_i[317]
  PIN mports_i[318]
    DIRECTION INPUT ;
    USE SIGNAL ;
    ANTENNAGATEAREA 0.213000 ;
    PORT
      LAYER met2 ;
        RECT 85.190 296.000 85.470 300.000 ;
    END
  END mports_i[318]
  PIN mports_i[319]
    DIRECTION INPUT ;
    USE SIGNAL ;
    ANTENNAGATEAREA 0.159000 ;
    PORT
      LAYER met2 ;
        RECT 86.110 296.000 86.390 300.000 ;
    END
  END mports_i[319]
  PIN mports_i[31]
    DIRECTION INPUT ;
    USE SIGNAL ;
    ANTENNAGATEAREA 0.213000 ;
    PORT
      LAYER met2 ;
        RECT 359.350 296.000 359.630 300.000 ;
    END
  END mports_i[31]
  PIN mports_i[320]
    DIRECTION INPUT ;
    USE SIGNAL ;
    ANTENNAGATEAREA 0.213000 ;
    PORT
      LAYER met2 ;
        RECT 87.030 296.000 87.310 300.000 ;
    END
  END mports_i[320]
  PIN mports_i[321]
    DIRECTION INPUT ;
    USE SIGNAL ;
    ANTENNAGATEAREA 0.213000 ;
    PORT
      LAYER met2 ;
        RECT 87.950 296.000 88.230 300.000 ;
    END
  END mports_i[321]
  PIN mports_i[322]
    DIRECTION INPUT ;
    USE SIGNAL ;
    ANTENNAGATEAREA 0.213000 ;
    PORT
      LAYER met2 ;
        RECT 88.870 296.000 89.150 300.000 ;
    END
  END mports_i[322]
  PIN mports_i[323]
    DIRECTION INPUT ;
    USE SIGNAL ;
    ANTENNAGATEAREA 0.213000 ;
    PORT
      LAYER met2 ;
        RECT 89.790 296.000 90.070 300.000 ;
    END
  END mports_i[323]
  PIN mports_i[324]
    DIRECTION INPUT ;
    USE SIGNAL ;
    ANTENNAGATEAREA 0.159000 ;
    PORT
      LAYER met2 ;
        RECT 90.710 296.000 90.990 300.000 ;
    END
  END mports_i[324]
  PIN mports_i[325]
    DIRECTION INPUT ;
    USE SIGNAL ;
    ANTENNAGATEAREA 0.213000 ;
    PORT
      LAYER met2 ;
        RECT 91.630 296.000 91.910 300.000 ;
    END
  END mports_i[325]
  PIN mports_i[326]
    DIRECTION INPUT ;
    USE SIGNAL ;
    ANTENNAGATEAREA 0.159000 ;
    PORT
      LAYER met2 ;
        RECT 92.550 296.000 92.830 300.000 ;
    END
  END mports_i[326]
  PIN mports_i[327]
    DIRECTION INPUT ;
    USE SIGNAL ;
    ANTENNAGATEAREA 0.213000 ;
    PORT
      LAYER met2 ;
        RECT 93.470 296.000 93.750 300.000 ;
    END
  END mports_i[327]
  PIN mports_i[328]
    DIRECTION INPUT ;
    USE SIGNAL ;
    ANTENNAGATEAREA 0.213000 ;
    PORT
      LAYER met2 ;
        RECT 94.390 296.000 94.670 300.000 ;
    END
  END mports_i[328]
  PIN mports_i[329]
    DIRECTION INPUT ;
    USE SIGNAL ;
    ANTENNAGATEAREA 0.159000 ;
    PORT
      LAYER met2 ;
        RECT 95.310 296.000 95.590 300.000 ;
    END
  END mports_i[329]
  PIN mports_i[32]
    DIRECTION INPUT ;
    USE SIGNAL ;
    ANTENNAGATEAREA 0.213000 ;
    PORT
      LAYER met2 ;
        RECT 360.270 296.000 360.550 300.000 ;
    END
  END mports_i[32]
  PIN mports_i[330]
    DIRECTION INPUT ;
    USE SIGNAL ;
    ANTENNAGATEAREA 0.213000 ;
    PORT
      LAYER met2 ;
        RECT 96.230 296.000 96.510 300.000 ;
    END
  END mports_i[330]
  PIN mports_i[331]
    DIRECTION INPUT ;
    USE SIGNAL ;
    ANTENNAGATEAREA 0.159000 ;
    PORT
      LAYER met2 ;
        RECT 97.150 296.000 97.430 300.000 ;
    END
  END mports_i[331]
  PIN mports_i[332]
    DIRECTION INPUT ;
    USE SIGNAL ;
    ANTENNAGATEAREA 0.213000 ;
    PORT
      LAYER met2 ;
        RECT 98.070 296.000 98.350 300.000 ;
    END
  END mports_i[332]
  PIN mports_i[333]
    DIRECTION INPUT ;
    USE SIGNAL ;
    ANTENNAGATEAREA 0.213000 ;
    PORT
      LAYER met2 ;
        RECT 98.990 296.000 99.270 300.000 ;
    END
  END mports_i[333]
  PIN mports_i[334]
    DIRECTION INPUT ;
    USE SIGNAL ;
    ANTENNAGATEAREA 0.159000 ;
    PORT
      LAYER met2 ;
        RECT 99.910 296.000 100.190 300.000 ;
    END
  END mports_i[334]
  PIN mports_i[335]
    DIRECTION INPUT ;
    USE SIGNAL ;
    ANTENNAGATEAREA 0.159000 ;
    PORT
      LAYER met2 ;
        RECT 100.830 296.000 101.110 300.000 ;
    END
  END mports_i[335]
  PIN mports_i[336]
    DIRECTION INPUT ;
    USE SIGNAL ;
    ANTENNAGATEAREA 0.159000 ;
    PORT
      LAYER met2 ;
        RECT 101.750 296.000 102.030 300.000 ;
    END
  END mports_i[336]
  PIN mports_i[337]
    DIRECTION INPUT ;
    USE SIGNAL ;
    ANTENNAGATEAREA 0.213000 ;
    PORT
      LAYER met2 ;
        RECT 102.670 296.000 102.950 300.000 ;
    END
  END mports_i[337]
  PIN mports_i[338]
    DIRECTION INPUT ;
    USE SIGNAL ;
    ANTENNAGATEAREA 0.213000 ;
    PORT
      LAYER met2 ;
        RECT 103.590 296.000 103.870 300.000 ;
    END
  END mports_i[338]
  PIN mports_i[339]
    DIRECTION INPUT ;
    USE SIGNAL ;
    ANTENNAGATEAREA 0.213000 ;
    PORT
      LAYER met2 ;
        RECT 104.510 296.000 104.790 300.000 ;
    END
  END mports_i[339]
  PIN mports_i[33]
    DIRECTION INPUT ;
    USE SIGNAL ;
    ANTENNAGATEAREA 0.213000 ;
    PORT
      LAYER met2 ;
        RECT 361.190 296.000 361.470 300.000 ;
    END
  END mports_i[33]
  PIN mports_i[340]
    DIRECTION INPUT ;
    USE SIGNAL ;
    ANTENNAGATEAREA 0.426000 ;
    PORT
      LAYER met2 ;
        RECT 105.430 296.000 105.710 300.000 ;
    END
  END mports_i[340]
  PIN mports_i[341]
    DIRECTION INPUT ;
    USE SIGNAL ;
    ANTENNAGATEAREA 0.213000 ;
    PORT
      LAYER met2 ;
        RECT 106.350 296.000 106.630 300.000 ;
    END
  END mports_i[341]
  PIN mports_i[342]
    DIRECTION INPUT ;
    USE SIGNAL ;
    ANTENNAGATEAREA 0.213000 ;
    PORT
      LAYER met2 ;
        RECT 107.270 296.000 107.550 300.000 ;
    END
  END mports_i[342]
  PIN mports_i[343]
    DIRECTION INPUT ;
    USE SIGNAL ;
    ANTENNAGATEAREA 0.159000 ;
    PORT
      LAYER met2 ;
        RECT 108.190 296.000 108.470 300.000 ;
    END
  END mports_i[343]
  PIN mports_i[344]
    DIRECTION INPUT ;
    USE SIGNAL ;
    ANTENNAGATEAREA 0.159000 ;
    PORT
      LAYER met2 ;
        RECT 109.110 296.000 109.390 300.000 ;
    END
  END mports_i[344]
  PIN mports_i[345]
    DIRECTION INPUT ;
    USE SIGNAL ;
    ANTENNAGATEAREA 0.196500 ;
    PORT
      LAYER met2 ;
        RECT 141.310 296.000 141.590 300.000 ;
    END
  END mports_i[345]
  PIN mports_i[346]
    DIRECTION INPUT ;
    USE SIGNAL ;
    ANTENNAGATEAREA 0.196500 ;
    PORT
      LAYER met2 ;
        RECT 142.230 296.000 142.510 300.000 ;
    END
  END mports_i[346]
  PIN mports_i[347]
    DIRECTION INPUT ;
    USE SIGNAL ;
    ANTENNAGATEAREA 0.213000 ;
    PORT
      LAYER met2 ;
        RECT 143.150 296.000 143.430 300.000 ;
    END
  END mports_i[347]
  PIN mports_i[348]
    DIRECTION INPUT ;
    USE SIGNAL ;
    ANTENNAGATEAREA 0.126000 ;
    PORT
      LAYER met2 ;
        RECT 144.070 296.000 144.350 300.000 ;
    END
  END mports_i[348]
  PIN mports_i[349]
    DIRECTION INPUT ;
    USE SIGNAL ;
    ANTENNAGATEAREA 0.213000 ;
    PORT
      LAYER met2 ;
        RECT 144.990 296.000 145.270 300.000 ;
    END
  END mports_i[349]
  PIN mports_i[34]
    DIRECTION INPUT ;
    USE SIGNAL ;
    ANTENNAGATEAREA 0.213000 ;
    PORT
      LAYER met2 ;
        RECT 362.110 296.000 362.390 300.000 ;
    END
  END mports_i[34]
  PIN mports_i[350]
    DIRECTION INPUT ;
    USE SIGNAL ;
    ANTENNAGATEAREA 0.196500 ;
    PORT
      LAYER met2 ;
        RECT 145.910 296.000 146.190 300.000 ;
    END
  END mports_i[350]
  PIN mports_i[351]
    DIRECTION INPUT ;
    USE SIGNAL ;
    ANTENNAGATEAREA 0.213000 ;
    PORT
      LAYER met2 ;
        RECT 146.830 296.000 147.110 300.000 ;
    END
  END mports_i[351]
  PIN mports_i[352]
    DIRECTION INPUT ;
    USE SIGNAL ;
    ANTENNAGATEAREA 0.196500 ;
    PORT
      LAYER met2 ;
        RECT 147.750 296.000 148.030 300.000 ;
    END
  END mports_i[352]
  PIN mports_i[353]
    DIRECTION INPUT ;
    USE SIGNAL ;
    ANTENNAGATEAREA 0.126000 ;
    PORT
      LAYER met2 ;
        RECT 148.670 296.000 148.950 300.000 ;
    END
  END mports_i[353]
  PIN mports_i[354]
    DIRECTION INPUT ;
    USE SIGNAL ;
    ANTENNAGATEAREA 0.213000 ;
    PORT
      LAYER met2 ;
        RECT 149.590 296.000 149.870 300.000 ;
    END
  END mports_i[354]
  PIN mports_i[355]
    DIRECTION INPUT ;
    USE SIGNAL ;
    ANTENNAGATEAREA 0.159000 ;
    PORT
      LAYER met2 ;
        RECT 150.510 296.000 150.790 300.000 ;
    END
  END mports_i[355]
  PIN mports_i[356]
    DIRECTION INPUT ;
    USE SIGNAL ;
    ANTENNAGATEAREA 0.126000 ;
    PORT
      LAYER met2 ;
        RECT 151.430 296.000 151.710 300.000 ;
    END
  END mports_i[356]
  PIN mports_i[357]
    DIRECTION INPUT ;
    USE SIGNAL ;
    ANTENNAGATEAREA 0.196500 ;
    PORT
      LAYER met2 ;
        RECT 152.350 296.000 152.630 300.000 ;
    END
  END mports_i[357]
  PIN mports_i[358]
    DIRECTION INPUT ;
    USE SIGNAL ;
    ANTENNAGATEAREA 0.196500 ;
    PORT
      LAYER met2 ;
        RECT 153.270 296.000 153.550 300.000 ;
    END
  END mports_i[358]
  PIN mports_i[359]
    DIRECTION INPUT ;
    USE SIGNAL ;
    ANTENNAGATEAREA 0.196500 ;
    PORT
      LAYER met2 ;
        RECT 154.190 296.000 154.470 300.000 ;
    END
  END mports_i[359]
  PIN mports_i[35]
    DIRECTION INPUT ;
    USE SIGNAL ;
    ANTENNAGATEAREA 0.213000 ;
    PORT
      LAYER met2 ;
        RECT 363.030 296.000 363.310 300.000 ;
    END
  END mports_i[35]
  PIN mports_i[360]
    DIRECTION INPUT ;
    USE SIGNAL ;
    ANTENNAGATEAREA 0.213000 ;
    PORT
      LAYER met2 ;
        RECT 155.110 296.000 155.390 300.000 ;
    END
  END mports_i[360]
  PIN mports_i[361]
    DIRECTION INPUT ;
    USE SIGNAL ;
    ANTENNAGATEAREA 0.213000 ;
    PORT
      LAYER met2 ;
        RECT 156.030 296.000 156.310 300.000 ;
    END
  END mports_i[361]
  PIN mports_i[362]
    DIRECTION INPUT ;
    USE SIGNAL ;
    ANTENNAGATEAREA 0.196500 ;
    PORT
      LAYER met2 ;
        RECT 156.950 296.000 157.230 300.000 ;
    END
  END mports_i[362]
  PIN mports_i[363]
    DIRECTION INPUT ;
    USE SIGNAL ;
    ANTENNAGATEAREA 0.213000 ;
    PORT
      LAYER met2 ;
        RECT 157.870 296.000 158.150 300.000 ;
    END
  END mports_i[363]
  PIN mports_i[364]
    DIRECTION INPUT ;
    USE SIGNAL ;
    ANTENNAGATEAREA 0.159000 ;
    PORT
      LAYER met2 ;
        RECT 158.790 296.000 159.070 300.000 ;
    END
  END mports_i[364]
  PIN mports_i[365]
    DIRECTION INPUT ;
    USE SIGNAL ;
    ANTENNAGATEAREA 0.196500 ;
    PORT
      LAYER met2 ;
        RECT 159.710 296.000 159.990 300.000 ;
    END
  END mports_i[365]
  PIN mports_i[366]
    DIRECTION INPUT ;
    USE SIGNAL ;
    ANTENNAGATEAREA 0.196500 ;
    PORT
      LAYER met2 ;
        RECT 160.630 296.000 160.910 300.000 ;
    END
  END mports_i[366]
  PIN mports_i[367]
    DIRECTION INPUT ;
    USE SIGNAL ;
    ANTENNAGATEAREA 0.196500 ;
    PORT
      LAYER met2 ;
        RECT 161.550 296.000 161.830 300.000 ;
    END
  END mports_i[367]
  PIN mports_i[368]
    DIRECTION INPUT ;
    USE SIGNAL ;
    ANTENNAGATEAREA 0.196500 ;
    PORT
      LAYER met2 ;
        RECT 162.470 296.000 162.750 300.000 ;
    END
  END mports_i[368]
  PIN mports_i[369]
    DIRECTION INPUT ;
    USE SIGNAL ;
    ANTENNAGATEAREA 0.196500 ;
    PORT
      LAYER met2 ;
        RECT 163.390 296.000 163.670 300.000 ;
    END
  END mports_i[369]
  PIN mports_i[36]
    DIRECTION INPUT ;
    USE SIGNAL ;
    ANTENNAGATEAREA 0.213000 ;
    PORT
      LAYER met2 ;
        RECT 363.950 296.000 364.230 300.000 ;
    END
  END mports_i[36]
  PIN mports_i[370]
    DIRECTION INPUT ;
    USE SIGNAL ;
    ANTENNAGATEAREA 0.126000 ;
    PORT
      LAYER met2 ;
        RECT 164.310 296.000 164.590 300.000 ;
    END
  END mports_i[370]
  PIN mports_i[371]
    DIRECTION INPUT ;
    USE SIGNAL ;
    ANTENNAGATEAREA 0.213000 ;
    PORT
      LAYER met2 ;
        RECT 165.230 296.000 165.510 300.000 ;
    END
  END mports_i[371]
  PIN mports_i[372]
    DIRECTION INPUT ;
    USE SIGNAL ;
    ANTENNAGATEAREA 0.159000 ;
    PORT
      LAYER met2 ;
        RECT 166.150 296.000 166.430 300.000 ;
    END
  END mports_i[372]
  PIN mports_i[373]
    DIRECTION INPUT ;
    USE SIGNAL ;
    ANTENNAGATEAREA 0.213000 ;
    PORT
      LAYER met2 ;
        RECT 167.070 296.000 167.350 300.000 ;
    END
  END mports_i[373]
  PIN mports_i[374]
    DIRECTION INPUT ;
    USE SIGNAL ;
    ANTENNAGATEAREA 0.126000 ;
    PORT
      LAYER met2 ;
        RECT 167.990 296.000 168.270 300.000 ;
    END
  END mports_i[374]
  PIN mports_i[375]
    DIRECTION INPUT ;
    USE SIGNAL ;
    ANTENNAGATEAREA 0.213000 ;
    PORT
      LAYER met2 ;
        RECT 168.910 296.000 169.190 300.000 ;
    END
  END mports_i[375]
  PIN mports_i[376]
    DIRECTION INPUT ;
    USE SIGNAL ;
    ANTENNAGATEAREA 0.213000 ;
    PORT
      LAYER met2 ;
        RECT 169.830 296.000 170.110 300.000 ;
    END
  END mports_i[376]
  PIN mports_i[377]
    DIRECTION INPUT ;
    USE SIGNAL ;
    ANTENNAGATEAREA 0.213000 ;
    PORT
      LAYER met2 ;
        RECT 170.750 296.000 171.030 300.000 ;
    END
  END mports_i[377]
  PIN mports_i[378]
    DIRECTION INPUT ;
    USE SIGNAL ;
    ANTENNAGATEAREA 0.196500 ;
    PORT
      LAYER met2 ;
        RECT 171.670 296.000 171.950 300.000 ;
    END
  END mports_i[378]
  PIN mports_i[379]
    DIRECTION INPUT ;
    USE SIGNAL ;
    ANTENNAGATEAREA 0.159000 ;
    PORT
      LAYER met2 ;
        RECT 172.590 296.000 172.870 300.000 ;
    END
  END mports_i[379]
  PIN mports_i[37]
    DIRECTION INPUT ;
    USE SIGNAL ;
    ANTENNAGATEAREA 0.213000 ;
    PORT
      LAYER met2 ;
        RECT 364.870 296.000 365.150 300.000 ;
    END
  END mports_i[37]
  PIN mports_i[380]
    DIRECTION INPUT ;
    USE SIGNAL ;
    ANTENNAGATEAREA 0.213000 ;
    PORT
      LAYER met2 ;
        RECT 173.510 296.000 173.790 300.000 ;
    END
  END mports_i[380]
  PIN mports_i[381]
    DIRECTION INPUT ;
    USE SIGNAL ;
    ANTENNAGATEAREA 0.196500 ;
    PORT
      LAYER met2 ;
        RECT 174.430 296.000 174.710 300.000 ;
    END
  END mports_i[381]
  PIN mports_i[382]
    DIRECTION INPUT ;
    USE SIGNAL ;
    ANTENNAGATEAREA 0.196500 ;
    PORT
      LAYER met2 ;
        RECT 175.350 296.000 175.630 300.000 ;
    END
  END mports_i[382]
  PIN mports_i[383]
    DIRECTION INPUT ;
    USE SIGNAL ;
    ANTENNAGATEAREA 0.196500 ;
    PORT
      LAYER met2 ;
        RECT 176.270 296.000 176.550 300.000 ;
    END
  END mports_i[383]
  PIN mports_i[384]
    DIRECTION INPUT ;
    USE SIGNAL ;
    ANTENNAGATEAREA 0.196500 ;
    PORT
      LAYER met2 ;
        RECT 177.190 296.000 177.470 300.000 ;
    END
  END mports_i[384]
  PIN mports_i[385]
    DIRECTION INPUT ;
    USE SIGNAL ;
    ANTENNAGATEAREA 0.126000 ;
    PORT
      LAYER met2 ;
        RECT 178.110 296.000 178.390 300.000 ;
    END
  END mports_i[385]
  PIN mports_i[386]
    DIRECTION INPUT ;
    USE SIGNAL ;
    ANTENNAGATEAREA 0.213000 ;
    PORT
      LAYER met2 ;
        RECT 179.030 296.000 179.310 300.000 ;
    END
  END mports_i[386]
  PIN mports_i[387]
    DIRECTION INPUT ;
    USE SIGNAL ;
    ANTENNAGATEAREA 0.126000 ;
    PORT
      LAYER met2 ;
        RECT 179.950 296.000 180.230 300.000 ;
    END
  END mports_i[387]
  PIN mports_i[388]
    DIRECTION INPUT ;
    USE SIGNAL ;
    ANTENNAGATEAREA 0.159000 ;
    PORT
      LAYER met2 ;
        RECT 180.870 296.000 181.150 300.000 ;
    END
  END mports_i[388]
  PIN mports_i[389]
    DIRECTION INPUT ;
    USE SIGNAL ;
    ANTENNAGATEAREA 0.159000 ;
    PORT
      LAYER met2 ;
        RECT 181.790 296.000 182.070 300.000 ;
    END
  END mports_i[389]
  PIN mports_i[38]
    DIRECTION INPUT ;
    USE SIGNAL ;
    ANTENNAGATEAREA 0.213000 ;
    PORT
      LAYER met2 ;
        RECT 365.790 296.000 366.070 300.000 ;
    END
  END mports_i[38]
  PIN mports_i[390]
    DIRECTION INPUT ;
    USE SIGNAL ;
    ANTENNAGATEAREA 0.159000 ;
    PORT
      LAYER met2 ;
        RECT 182.710 296.000 182.990 300.000 ;
    END
  END mports_i[390]
  PIN mports_i[391]
    DIRECTION INPUT ;
    USE SIGNAL ;
    ANTENNAGATEAREA 0.159000 ;
    PORT
      LAYER met2 ;
        RECT 183.630 296.000 183.910 300.000 ;
    END
  END mports_i[391]
  PIN mports_i[392]
    DIRECTION INPUT ;
    USE SIGNAL ;
    ANTENNAGATEAREA 0.196500 ;
    PORT
      LAYER met2 ;
        RECT 184.550 296.000 184.830 300.000 ;
    END
  END mports_i[392]
  PIN mports_i[393]
    DIRECTION INPUT ;
    USE SIGNAL ;
    ANTENNAGATEAREA 0.213000 ;
    PORT
      LAYER met2 ;
        RECT 185.470 296.000 185.750 300.000 ;
    END
  END mports_i[393]
  PIN mports_i[394]
    DIRECTION INPUT ;
    USE SIGNAL ;
    ANTENNAGATEAREA 0.159000 ;
    PORT
      LAYER met2 ;
        RECT 186.390 296.000 186.670 300.000 ;
    END
  END mports_i[394]
  PIN mports_i[395]
    DIRECTION INPUT ;
    USE SIGNAL ;
    ANTENNAGATEAREA 0.213000 ;
    PORT
      LAYER met2 ;
        RECT 187.310 296.000 187.590 300.000 ;
    END
  END mports_i[395]
  PIN mports_i[396]
    DIRECTION INPUT ;
    USE SIGNAL ;
    ANTENNAGATEAREA 0.196500 ;
    PORT
      LAYER met2 ;
        RECT 188.230 296.000 188.510 300.000 ;
    END
  END mports_i[396]
  PIN mports_i[397]
    DIRECTION INPUT ;
    USE SIGNAL ;
    ANTENNAGATEAREA 0.196500 ;
    PORT
      LAYER met2 ;
        RECT 189.150 296.000 189.430 300.000 ;
    END
  END mports_i[397]
  PIN mports_i[398]
    DIRECTION INPUT ;
    USE SIGNAL ;
    ANTENNAGATEAREA 0.159000 ;
    PORT
      LAYER met2 ;
        RECT 190.070 296.000 190.350 300.000 ;
    END
  END mports_i[398]
  PIN mports_i[399]
    DIRECTION INPUT ;
    USE SIGNAL ;
    ANTENNAGATEAREA 0.126000 ;
    PORT
      LAYER met2 ;
        RECT 190.990 296.000 191.270 300.000 ;
    END
  END mports_i[399]
  PIN mports_i[39]
    DIRECTION INPUT ;
    USE SIGNAL ;
    ANTENNAGATEAREA 0.213000 ;
    PORT
      LAYER met2 ;
        RECT 366.710 296.000 366.990 300.000 ;
    END
  END mports_i[39]
  PIN mports_i[3]
    DIRECTION INPUT ;
    USE SIGNAL ;
    ANTENNAGATEAREA 0.159000 ;
    PORT
      LAYER met2 ;
        RECT 333.590 296.000 333.870 300.000 ;
    END
  END mports_i[3]
  PIN mports_i[400]
    DIRECTION INPUT ;
    USE SIGNAL ;
    ANTENNAGATEAREA 0.213000 ;
    PORT
      LAYER met2 ;
        RECT 191.910 296.000 192.190 300.000 ;
    END
  END mports_i[400]
  PIN mports_i[401]
    DIRECTION INPUT ;
    USE SIGNAL ;
    ANTENNAGATEAREA 0.213000 ;
    PORT
      LAYER met2 ;
        RECT 192.830 296.000 193.110 300.000 ;
    END
  END mports_i[401]
  PIN mports_i[402]
    DIRECTION INPUT ;
    USE SIGNAL ;
    ANTENNAGATEAREA 0.196500 ;
    PORT
      LAYER met2 ;
        RECT 193.750 296.000 194.030 300.000 ;
    END
  END mports_i[402]
  PIN mports_i[403]
    DIRECTION INPUT ;
    USE SIGNAL ;
    ANTENNAGATEAREA 0.213000 ;
    PORT
      LAYER met2 ;
        RECT 194.670 296.000 194.950 300.000 ;
    END
  END mports_i[403]
  PIN mports_i[404]
    DIRECTION INPUT ;
    USE SIGNAL ;
    ANTENNAGATEAREA 0.213000 ;
    PORT
      LAYER met2 ;
        RECT 195.590 296.000 195.870 300.000 ;
    END
  END mports_i[404]
  PIN mports_i[405]
    DIRECTION INPUT ;
    USE SIGNAL ;
    ANTENNAGATEAREA 0.213000 ;
    PORT
      LAYER met2 ;
        RECT 196.510 296.000 196.790 300.000 ;
    END
  END mports_i[405]
  PIN mports_i[406]
    DIRECTION INPUT ;
    USE SIGNAL ;
    ANTENNAGATEAREA 0.159000 ;
    PORT
      LAYER met2 ;
        RECT 197.430 296.000 197.710 300.000 ;
    END
  END mports_i[406]
  PIN mports_i[407]
    DIRECTION INPUT ;
    USE SIGNAL ;
    ANTENNAGATEAREA 0.159000 ;
    PORT
      LAYER met2 ;
        RECT 198.350 296.000 198.630 300.000 ;
    END
  END mports_i[407]
  PIN mports_i[408]
    DIRECTION INPUT ;
    USE SIGNAL ;
    ANTENNAGATEAREA 0.159000 ;
    PORT
      LAYER met2 ;
        RECT 199.270 296.000 199.550 300.000 ;
    END
  END mports_i[408]
  PIN mports_i[409]
    DIRECTION INPUT ;
    USE SIGNAL ;
    ANTENNAGATEAREA 0.426000 ;
    PORT
      LAYER met2 ;
        RECT 200.190 296.000 200.470 300.000 ;
    END
  END mports_i[409]
  PIN mports_i[40]
    DIRECTION INPUT ;
    USE SIGNAL ;
    ANTENNAGATEAREA 0.213000 ;
    PORT
      LAYER met2 ;
        RECT 367.630 296.000 367.910 300.000 ;
    END
  END mports_i[40]
  PIN mports_i[410]
    DIRECTION INPUT ;
    USE SIGNAL ;
    ANTENNAGATEAREA 0.159000 ;
    PORT
      LAYER met2 ;
        RECT 201.110 296.000 201.390 300.000 ;
    END
  END mports_i[410]
  PIN mports_i[411]
    DIRECTION INPUT ;
    USE SIGNAL ;
    ANTENNAGATEAREA 0.159000 ;
    PORT
      LAYER met2 ;
        RECT 202.030 296.000 202.310 300.000 ;
    END
  END mports_i[411]
  PIN mports_i[412]
    DIRECTION INPUT ;
    USE SIGNAL ;
    ANTENNAGATEAREA 0.213000 ;
    PORT
      LAYER met2 ;
        RECT 202.950 296.000 203.230 300.000 ;
    END
  END mports_i[412]
  PIN mports_i[413]
    DIRECTION INPUT ;
    USE SIGNAL ;
    ANTENNAGATEAREA 0.213000 ;
    PORT
      LAYER met2 ;
        RECT 203.870 296.000 204.150 300.000 ;
    END
  END mports_i[413]
  PIN mports_i[414]
    DIRECTION INPUT ;
    USE SIGNAL ;
    ANTENNAGATEAREA 0.213000 ;
    PORT
      LAYER met3 ;
        RECT 0.000 103.400 4.000 104.000 ;
    END
  END mports_i[414]
  PIN mports_i[415]
    DIRECTION INPUT ;
    USE SIGNAL ;
    ANTENNAGATEAREA 0.213000 ;
    PORT
      LAYER met3 ;
        RECT 0.000 106.120 4.000 106.720 ;
    END
  END mports_i[415]
  PIN mports_i[416]
    DIRECTION INPUT ;
    USE SIGNAL ;
    ANTENNAGATEAREA 0.213000 ;
    PORT
      LAYER met3 ;
        RECT 0.000 108.840 4.000 109.440 ;
    END
  END mports_i[416]
  PIN mports_i[417]
    DIRECTION INPUT ;
    USE SIGNAL ;
    ANTENNAGATEAREA 0.213000 ;
    PORT
      LAYER met3 ;
        RECT 0.000 111.560 4.000 112.160 ;
    END
  END mports_i[417]
  PIN mports_i[418]
    DIRECTION INPUT ;
    USE SIGNAL ;
    ANTENNAGATEAREA 0.213000 ;
    PORT
      LAYER met3 ;
        RECT 0.000 114.280 4.000 114.880 ;
    END
  END mports_i[418]
  PIN mports_i[419]
    DIRECTION INPUT ;
    USE SIGNAL ;
    ANTENNAGATEAREA 0.213000 ;
    PORT
      LAYER met3 ;
        RECT 0.000 117.000 4.000 117.600 ;
    END
  END mports_i[419]
  PIN mports_i[41]
    DIRECTION INPUT ;
    USE SIGNAL ;
    ANTENNAGATEAREA 0.213000 ;
    PORT
      LAYER met2 ;
        RECT 368.550 296.000 368.830 300.000 ;
    END
  END mports_i[41]
  PIN mports_i[420]
    DIRECTION INPUT ;
    USE SIGNAL ;
    ANTENNAGATEAREA 0.213000 ;
    PORT
      LAYER met3 ;
        RECT 0.000 119.720 4.000 120.320 ;
    END
  END mports_i[420]
  PIN mports_i[421]
    DIRECTION INPUT ;
    USE SIGNAL ;
    ANTENNAGATEAREA 0.159000 ;
    PORT
      LAYER met3 ;
        RECT 0.000 122.440 4.000 123.040 ;
    END
  END mports_i[421]
  PIN mports_i[422]
    DIRECTION INPUT ;
    USE SIGNAL ;
    ANTENNAGATEAREA 0.213000 ;
    PORT
      LAYER met3 ;
        RECT 0.000 125.160 4.000 125.760 ;
    END
  END mports_i[422]
  PIN mports_i[423]
    DIRECTION INPUT ;
    USE SIGNAL ;
    ANTENNAGATEAREA 0.159000 ;
    PORT
      LAYER met3 ;
        RECT 0.000 127.880 4.000 128.480 ;
    END
  END mports_i[423]
  PIN mports_i[424]
    DIRECTION INPUT ;
    USE SIGNAL ;
    ANTENNAGATEAREA 0.159000 ;
    PORT
      LAYER met3 ;
        RECT 0.000 130.600 4.000 131.200 ;
    END
  END mports_i[424]
  PIN mports_i[425]
    DIRECTION INPUT ;
    USE SIGNAL ;
    ANTENNAGATEAREA 0.213000 ;
    PORT
      LAYER met3 ;
        RECT 0.000 133.320 4.000 133.920 ;
    END
  END mports_i[425]
  PIN mports_i[426]
    DIRECTION INPUT ;
    USE SIGNAL ;
    ANTENNAGATEAREA 0.213000 ;
    PORT
      LAYER met3 ;
        RECT 0.000 136.040 4.000 136.640 ;
    END
  END mports_i[426]
  PIN mports_i[427]
    DIRECTION INPUT ;
    USE SIGNAL ;
    ANTENNAGATEAREA 0.213000 ;
    PORT
      LAYER met3 ;
        RECT 0.000 138.760 4.000 139.360 ;
    END
  END mports_i[427]
  PIN mports_i[428]
    DIRECTION INPUT ;
    USE SIGNAL ;
    ANTENNAGATEAREA 0.213000 ;
    PORT
      LAYER met3 ;
        RECT 0.000 141.480 4.000 142.080 ;
    END
  END mports_i[428]
  PIN mports_i[429]
    DIRECTION INPUT ;
    USE SIGNAL ;
    ANTENNAGATEAREA 0.213000 ;
    PORT
      LAYER met3 ;
        RECT 0.000 144.200 4.000 144.800 ;
    END
  END mports_i[429]
  PIN mports_i[42]
    DIRECTION INPUT ;
    USE SIGNAL ;
    ANTENNAGATEAREA 0.213000 ;
    PORT
      LAYER met2 ;
        RECT 369.470 296.000 369.750 300.000 ;
    END
  END mports_i[42]
  PIN mports_i[430]
    DIRECTION INPUT ;
    USE SIGNAL ;
    ANTENNAGATEAREA 0.213000 ;
    PORT
      LAYER met3 ;
        RECT 0.000 146.920 4.000 147.520 ;
    END
  END mports_i[430]
  PIN mports_i[431]
    DIRECTION INPUT ;
    USE SIGNAL ;
    ANTENNAGATEAREA 0.159000 ;
    PORT
      LAYER met3 ;
        RECT 0.000 149.640 4.000 150.240 ;
    END
  END mports_i[431]
  PIN mports_i[432]
    DIRECTION INPUT ;
    USE SIGNAL ;
    ANTENNAGATEAREA 0.213000 ;
    PORT
      LAYER met3 ;
        RECT 0.000 152.360 4.000 152.960 ;
    END
  END mports_i[432]
  PIN mports_i[433]
    DIRECTION INPUT ;
    USE SIGNAL ;
    ANTENNAGATEAREA 0.159000 ;
    PORT
      LAYER met3 ;
        RECT 0.000 155.080 4.000 155.680 ;
    END
  END mports_i[433]
  PIN mports_i[434]
    DIRECTION INPUT ;
    USE SIGNAL ;
    ANTENNAGATEAREA 0.213000 ;
    PORT
      LAYER met3 ;
        RECT 0.000 157.800 4.000 158.400 ;
    END
  END mports_i[434]
  PIN mports_i[435]
    DIRECTION INPUT ;
    USE SIGNAL ;
    ANTENNAGATEAREA 0.213000 ;
    PORT
      LAYER met3 ;
        RECT 0.000 160.520 4.000 161.120 ;
    END
  END mports_i[435]
  PIN mports_i[436]
    DIRECTION INPUT ;
    USE SIGNAL ;
    ANTENNAGATEAREA 0.159000 ;
    PORT
      LAYER met3 ;
        RECT 0.000 163.240 4.000 163.840 ;
    END
  END mports_i[436]
  PIN mports_i[437]
    DIRECTION INPUT ;
    USE SIGNAL ;
    ANTENNAGATEAREA 0.159000 ;
    PORT
      LAYER met3 ;
        RECT 0.000 165.960 4.000 166.560 ;
    END
  END mports_i[437]
  PIN mports_i[438]
    DIRECTION INPUT ;
    USE SIGNAL ;
    ANTENNAGATEAREA 0.213000 ;
    PORT
      LAYER met3 ;
        RECT 0.000 168.680 4.000 169.280 ;
    END
  END mports_i[438]
  PIN mports_i[439]
    DIRECTION INPUT ;
    USE SIGNAL ;
    ANTENNAGATEAREA 0.213000 ;
    PORT
      LAYER met3 ;
        RECT 0.000 171.400 4.000 172.000 ;
    END
  END mports_i[439]
  PIN mports_i[43]
    DIRECTION INPUT ;
    USE SIGNAL ;
    ANTENNAGATEAREA 0.196500 ;
    PORT
      LAYER met2 ;
        RECT 370.390 296.000 370.670 300.000 ;
    END
  END mports_i[43]
  PIN mports_i[440]
    DIRECTION INPUT ;
    USE SIGNAL ;
    ANTENNAGATEAREA 0.159000 ;
    PORT
      LAYER met3 ;
        RECT 0.000 174.120 4.000 174.720 ;
    END
  END mports_i[440]
  PIN mports_i[441]
    DIRECTION INPUT ;
    USE SIGNAL ;
    ANTENNAGATEAREA 0.159000 ;
    PORT
      LAYER met3 ;
        RECT 0.000 176.840 4.000 177.440 ;
    END
  END mports_i[441]
  PIN mports_i[442]
    DIRECTION INPUT ;
    USE SIGNAL ;
    ANTENNAGATEAREA 0.159000 ;
    PORT
      LAYER met3 ;
        RECT 0.000 179.560 4.000 180.160 ;
    END
  END mports_i[442]
  PIN mports_i[443]
    DIRECTION INPUT ;
    USE SIGNAL ;
    ANTENNAGATEAREA 0.213000 ;
    PORT
      LAYER met3 ;
        RECT 0.000 182.280 4.000 182.880 ;
    END
  END mports_i[443]
  PIN mports_i[444]
    DIRECTION INPUT ;
    USE SIGNAL ;
    ANTENNAGATEAREA 0.159000 ;
    PORT
      LAYER met3 ;
        RECT 0.000 185.000 4.000 185.600 ;
    END
  END mports_i[444]
  PIN mports_i[445]
    DIRECTION INPUT ;
    USE SIGNAL ;
    ANTENNAGATEAREA 0.213000 ;
    PORT
      LAYER met3 ;
        RECT 0.000 187.720 4.000 188.320 ;
    END
  END mports_i[445]
  PIN mports_i[446]
    DIRECTION INPUT ;
    USE SIGNAL ;
    ANTENNAGATEAREA 0.159000 ;
    PORT
      LAYER met3 ;
        RECT 0.000 190.440 4.000 191.040 ;
    END
  END mports_i[446]
  PIN mports_i[447]
    DIRECTION INPUT ;
    USE SIGNAL ;
    ANTENNAGATEAREA 0.213000 ;
    PORT
      LAYER met3 ;
        RECT 0.000 193.160 4.000 193.760 ;
    END
  END mports_i[447]
  PIN mports_i[448]
    DIRECTION INPUT ;
    USE SIGNAL ;
    ANTENNAGATEAREA 0.213000 ;
    PORT
      LAYER met3 ;
        RECT 0.000 195.880 4.000 196.480 ;
    END
  END mports_i[448]
  PIN mports_i[449]
    DIRECTION INPUT ;
    USE SIGNAL ;
    ANTENNAGATEAREA 0.213000 ;
    PORT
      LAYER met3 ;
        RECT 0.000 198.600 4.000 199.200 ;
    END
  END mports_i[449]
  PIN mports_i[44]
    DIRECTION INPUT ;
    USE SIGNAL ;
    ANTENNAGATEAREA 0.196500 ;
    PORT
      LAYER met2 ;
        RECT 371.310 296.000 371.590 300.000 ;
    END
  END mports_i[44]
  PIN mports_i[450]
    DIRECTION INPUT ;
    USE SIGNAL ;
    ANTENNAGATEAREA 0.159000 ;
    PORT
      LAYER met3 ;
        RECT 0.000 201.320 4.000 201.920 ;
    END
  END mports_i[450]
  PIN mports_i[451]
    DIRECTION INPUT ;
    USE SIGNAL ;
    ANTENNAGATEAREA 0.159000 ;
    PORT
      LAYER met3 ;
        RECT 0.000 204.040 4.000 204.640 ;
    END
  END mports_i[451]
  PIN mports_i[452]
    DIRECTION INPUT ;
    USE SIGNAL ;
    ANTENNAGATEAREA 0.159000 ;
    PORT
      LAYER met3 ;
        RECT 0.000 206.760 4.000 207.360 ;
    END
  END mports_i[452]
  PIN mports_i[453]
    DIRECTION INPUT ;
    USE SIGNAL ;
    ANTENNAGATEAREA 0.213000 ;
    PORT
      LAYER met3 ;
        RECT 0.000 209.480 4.000 210.080 ;
    END
  END mports_i[453]
  PIN mports_i[454]
    DIRECTION INPUT ;
    USE SIGNAL ;
    ANTENNAGATEAREA 0.159000 ;
    PORT
      LAYER met3 ;
        RECT 0.000 212.200 4.000 212.800 ;
    END
  END mports_i[454]
  PIN mports_i[455]
    DIRECTION INPUT ;
    USE SIGNAL ;
    ANTENNAGATEAREA 0.159000 ;
    PORT
      LAYER met3 ;
        RECT 0.000 214.920 4.000 215.520 ;
    END
  END mports_i[455]
  PIN mports_i[456]
    DIRECTION INPUT ;
    USE SIGNAL ;
    ANTENNAGATEAREA 0.159000 ;
    PORT
      LAYER met3 ;
        RECT 0.000 217.640 4.000 218.240 ;
    END
  END mports_i[456]
  PIN mports_i[457]
    DIRECTION INPUT ;
    USE SIGNAL ;
    ANTENNAGATEAREA 0.213000 ;
    PORT
      LAYER met3 ;
        RECT 0.000 220.360 4.000 220.960 ;
    END
  END mports_i[457]
  PIN mports_i[458]
    DIRECTION INPUT ;
    USE SIGNAL ;
    ANTENNAGATEAREA 0.213000 ;
    PORT
      LAYER met3 ;
        RECT 0.000 223.080 4.000 223.680 ;
    END
  END mports_i[458]
  PIN mports_i[459]
    DIRECTION INPUT ;
    USE SIGNAL ;
    ANTENNAGATEAREA 0.213000 ;
    PORT
      LAYER met3 ;
        RECT 0.000 225.800 4.000 226.400 ;
    END
  END mports_i[459]
  PIN mports_i[45]
    DIRECTION INPUT ;
    USE SIGNAL ;
    ANTENNAGATEAREA 0.196500 ;
    PORT
      LAYER met2 ;
        RECT 372.230 296.000 372.510 300.000 ;
    END
  END mports_i[45]
  PIN mports_i[460]
    DIRECTION INPUT ;
    USE SIGNAL ;
    ANTENNAGATEAREA 0.213000 ;
    PORT
      LAYER met3 ;
        RECT 0.000 228.520 4.000 229.120 ;
    END
  END mports_i[460]
  PIN mports_i[461]
    DIRECTION INPUT ;
    USE SIGNAL ;
    ANTENNAGATEAREA 0.159000 ;
    PORT
      LAYER met3 ;
        RECT 0.000 231.240 4.000 231.840 ;
    END
  END mports_i[461]
  PIN mports_i[462]
    DIRECTION INPUT ;
    USE SIGNAL ;
    ANTENNAGATEAREA 0.159000 ;
    PORT
      LAYER met3 ;
        RECT 0.000 233.960 4.000 234.560 ;
    END
  END mports_i[462]
  PIN mports_i[463]
    DIRECTION INPUT ;
    USE SIGNAL ;
    ANTENNAGATEAREA 0.213000 ;
    PORT
      LAYER met3 ;
        RECT 0.000 236.680 4.000 237.280 ;
    END
  END mports_i[463]
  PIN mports_i[464]
    DIRECTION INPUT ;
    USE SIGNAL ;
    ANTENNAGATEAREA 0.159000 ;
    PORT
      LAYER met3 ;
        RECT 0.000 239.400 4.000 240.000 ;
    END
  END mports_i[464]
  PIN mports_i[465]
    DIRECTION INPUT ;
    USE SIGNAL ;
    ANTENNAGATEAREA 0.159000 ;
    PORT
      LAYER met3 ;
        RECT 0.000 242.120 4.000 242.720 ;
    END
  END mports_i[465]
  PIN mports_i[466]
    DIRECTION INPUT ;
    USE SIGNAL ;
    ANTENNAGATEAREA 0.159000 ;
    PORT
      LAYER met3 ;
        RECT 0.000 244.840 4.000 245.440 ;
    END
  END mports_i[466]
  PIN mports_i[467]
    DIRECTION INPUT ;
    USE SIGNAL ;
    ANTENNAGATEAREA 0.213000 ;
    PORT
      LAYER met3 ;
        RECT 0.000 247.560 4.000 248.160 ;
    END
  END mports_i[467]
  PIN mports_i[468]
    DIRECTION INPUT ;
    USE SIGNAL ;
    ANTENNAGATEAREA 0.159000 ;
    PORT
      LAYER met3 ;
        RECT 0.000 250.280 4.000 250.880 ;
    END
  END mports_i[468]
  PIN mports_i[469]
    DIRECTION INPUT ;
    USE SIGNAL ;
    ANTENNAGATEAREA 0.159000 ;
    PORT
      LAYER met3 ;
        RECT 0.000 253.000 4.000 253.600 ;
    END
  END mports_i[469]
  PIN mports_i[46]
    DIRECTION INPUT ;
    USE SIGNAL ;
    ANTENNAGATEAREA 0.213000 ;
    PORT
      LAYER met2 ;
        RECT 373.150 296.000 373.430 300.000 ;
    END
  END mports_i[46]
  PIN mports_i[470]
    DIRECTION INPUT ;
    USE SIGNAL ;
    ANTENNAGATEAREA 0.247500 ;
    PORT
      LAYER met3 ;
        RECT 0.000 255.720 4.000 256.320 ;
    END
  END mports_i[470]
  PIN mports_i[471]
    DIRECTION INPUT ;
    USE SIGNAL ;
    ANTENNAGATEAREA 0.159000 ;
    PORT
      LAYER met3 ;
        RECT 0.000 258.440 4.000 259.040 ;
    END
  END mports_i[471]
  PIN mports_i[472]
    DIRECTION INPUT ;
    USE SIGNAL ;
    ANTENNAGATEAREA 0.213000 ;
    PORT
      LAYER met3 ;
        RECT 0.000 261.160 4.000 261.760 ;
    END
  END mports_i[472]
  PIN mports_i[473]
    DIRECTION INPUT ;
    USE SIGNAL ;
    ANTENNAGATEAREA 0.213000 ;
    PORT
      LAYER met3 ;
        RECT 0.000 263.880 4.000 264.480 ;
    END
  END mports_i[473]
  PIN mports_i[474]
    DIRECTION INPUT ;
    USE SIGNAL ;
    ANTENNAGATEAREA 0.213000 ;
    PORT
      LAYER met3 ;
        RECT 0.000 266.600 4.000 267.200 ;
    END
  END mports_i[474]
  PIN mports_i[475]
    DIRECTION INPUT ;
    USE SIGNAL ;
    ANTENNAGATEAREA 0.213000 ;
    PORT
      LAYER met3 ;
        RECT 0.000 269.320 4.000 269.920 ;
    END
  END mports_i[475]
  PIN mports_i[476]
    DIRECTION INPUT ;
    USE SIGNAL ;
    ANTENNAGATEAREA 0.247500 ;
    PORT
      LAYER met3 ;
        RECT 0.000 272.040 4.000 272.640 ;
    END
  END mports_i[476]
  PIN mports_i[477]
    DIRECTION INPUT ;
    USE SIGNAL ;
    ANTENNAGATEAREA 0.213000 ;
    PORT
      LAYER met3 ;
        RECT 0.000 274.760 4.000 275.360 ;
    END
  END mports_i[477]
  PIN mports_i[478]
    DIRECTION INPUT ;
    USE SIGNAL ;
    ANTENNAGATEAREA 0.426000 ;
    PORT
      LAYER met3 ;
        RECT 0.000 277.480 4.000 278.080 ;
    END
  END mports_i[478]
  PIN mports_i[479]
    DIRECTION INPUT ;
    USE SIGNAL ;
    ANTENNAGATEAREA 0.213000 ;
    PORT
      LAYER met3 ;
        RECT 0.000 280.200 4.000 280.800 ;
    END
  END mports_i[479]
  PIN mports_i[47]
    DIRECTION INPUT ;
    USE SIGNAL ;
    ANTENNAGATEAREA 0.213000 ;
    PORT
      LAYER met2 ;
        RECT 374.070 296.000 374.350 300.000 ;
    END
  END mports_i[47]
  PIN mports_i[480]
    DIRECTION INPUT ;
    USE SIGNAL ;
    ANTENNAGATEAREA 0.213000 ;
    PORT
      LAYER met3 ;
        RECT 0.000 282.920 4.000 283.520 ;
    END
  END mports_i[480]
  PIN mports_i[481]
    DIRECTION INPUT ;
    USE SIGNAL ;
    ANTENNAGATEAREA 0.213000 ;
    PORT
      LAYER met3 ;
        RECT 0.000 285.640 4.000 286.240 ;
    END
  END mports_i[481]
  PIN mports_i[482]
    DIRECTION INPUT ;
    USE SIGNAL ;
    ANTENNAGATEAREA 0.213000 ;
    PORT
      LAYER met3 ;
        RECT 0.000 288.360 4.000 288.960 ;
    END
  END mports_i[482]
  PIN mports_i[483]
    DIRECTION INPUT ;
    USE SIGNAL ;
    ANTENNAGATEAREA 0.426000 ;
    PORT
      LAYER met3 ;
        RECT 596.000 57.160 600.000 57.760 ;
    END
  END mports_i[483]
  PIN mports_i[484]
    DIRECTION INPUT ;
    USE SIGNAL ;
    ANTENNAGATEAREA 0.426000 ;
    PORT
      LAYER met3 ;
        RECT 596.000 58.520 600.000 59.120 ;
    END
  END mports_i[484]
  PIN mports_i[485]
    DIRECTION INPUT ;
    USE SIGNAL ;
    ANTENNAGATEAREA 0.247500 ;
    PORT
      LAYER met3 ;
        RECT 596.000 59.880 600.000 60.480 ;
    END
  END mports_i[485]
  PIN mports_i[486]
    DIRECTION INPUT ;
    USE SIGNAL ;
    ANTENNAGATEAREA 0.247500 ;
    PORT
      LAYER met3 ;
        RECT 596.000 61.240 600.000 61.840 ;
    END
  END mports_i[486]
  PIN mports_i[487]
    DIRECTION INPUT ;
    USE SIGNAL ;
    ANTENNAGATEAREA 0.247500 ;
    PORT
      LAYER met3 ;
        RECT 596.000 62.600 600.000 63.200 ;
    END
  END mports_i[487]
  PIN mports_i[488]
    DIRECTION INPUT ;
    USE SIGNAL ;
    ANTENNAGATEAREA 0.247500 ;
    PORT
      LAYER met3 ;
        RECT 596.000 63.960 600.000 64.560 ;
    END
  END mports_i[488]
  PIN mports_i[489]
    DIRECTION INPUT ;
    USE SIGNAL ;
    ANTENNAGATEAREA 0.247500 ;
    PORT
      LAYER met3 ;
        RECT 596.000 65.320 600.000 65.920 ;
    END
  END mports_i[489]
  PIN mports_i[48]
    DIRECTION INPUT ;
    USE SIGNAL ;
    ANTENNAGATEAREA 0.126000 ;
    PORT
      LAYER met2 ;
        RECT 374.990 296.000 375.270 300.000 ;
    END
  END mports_i[48]
  PIN mports_i[490]
    DIRECTION INPUT ;
    USE SIGNAL ;
    ANTENNAGATEAREA 0.426000 ;
    PORT
      LAYER met3 ;
        RECT 596.000 66.680 600.000 67.280 ;
    END
  END mports_i[490]
  PIN mports_i[491]
    DIRECTION INPUT ;
    USE SIGNAL ;
    ANTENNAGATEAREA 0.426000 ;
    PORT
      LAYER met3 ;
        RECT 596.000 68.040 600.000 68.640 ;
    END
  END mports_i[491]
  PIN mports_i[492]
    DIRECTION INPUT ;
    USE SIGNAL ;
    ANTENNAGATEAREA 0.213000 ;
    PORT
      LAYER met3 ;
        RECT 596.000 69.400 600.000 70.000 ;
    END
  END mports_i[492]
  PIN mports_i[493]
    DIRECTION INPUT ;
    USE SIGNAL ;
    ANTENNAGATEAREA 0.213000 ;
    PORT
      LAYER met3 ;
        RECT 596.000 70.760 600.000 71.360 ;
    END
  END mports_i[493]
  PIN mports_i[494]
    DIRECTION INPUT ;
    USE SIGNAL ;
    ANTENNAGATEAREA 0.247500 ;
    PORT
      LAYER met3 ;
        RECT 596.000 72.120 600.000 72.720 ;
    END
  END mports_i[494]
  PIN mports_i[495]
    DIRECTION INPUT ;
    USE SIGNAL ;
    ANTENNAGATEAREA 0.247500 ;
    PORT
      LAYER met3 ;
        RECT 596.000 73.480 600.000 74.080 ;
    END
  END mports_i[495]
  PIN mports_i[496]
    DIRECTION INPUT ;
    USE SIGNAL ;
    ANTENNAGATEAREA 0.247500 ;
    PORT
      LAYER met3 ;
        RECT 596.000 74.840 600.000 75.440 ;
    END
  END mports_i[496]
  PIN mports_i[497]
    DIRECTION INPUT ;
    USE SIGNAL ;
    ANTENNAGATEAREA 0.247500 ;
    PORT
      LAYER met3 ;
        RECT 596.000 76.200 600.000 76.800 ;
    END
  END mports_i[497]
  PIN mports_i[498]
    DIRECTION INPUT ;
    USE SIGNAL ;
    ANTENNAGATEAREA 0.159000 ;
    PORT
      LAYER met3 ;
        RECT 596.000 77.560 600.000 78.160 ;
    END
  END mports_i[498]
  PIN mports_i[499]
    DIRECTION INPUT ;
    USE SIGNAL ;
    ANTENNAGATEAREA 0.213000 ;
    PORT
      LAYER met3 ;
        RECT 596.000 78.920 600.000 79.520 ;
    END
  END mports_i[499]
  PIN mports_i[49]
    DIRECTION INPUT ;
    USE SIGNAL ;
    ANTENNAGATEAREA 0.213000 ;
    PORT
      LAYER met2 ;
        RECT 375.910 296.000 376.190 300.000 ;
    END
  END mports_i[49]
  PIN mports_i[4]
    DIRECTION INPUT ;
    USE SIGNAL ;
    ANTENNAGATEAREA 0.159000 ;
    PORT
      LAYER met2 ;
        RECT 334.510 296.000 334.790 300.000 ;
    END
  END mports_i[4]
  PIN mports_i[500]
    DIRECTION INPUT ;
    USE SIGNAL ;
    ANTENNAGATEAREA 0.247500 ;
    PORT
      LAYER met3 ;
        RECT 596.000 80.280 600.000 80.880 ;
    END
  END mports_i[500]
  PIN mports_i[501]
    DIRECTION INPUT ;
    USE SIGNAL ;
    ANTENNAGATEAREA 0.213000 ;
    PORT
      LAYER met3 ;
        RECT 596.000 81.640 600.000 82.240 ;
    END
  END mports_i[501]
  PIN mports_i[502]
    DIRECTION INPUT ;
    USE SIGNAL ;
    ANTENNAGATEAREA 0.213000 ;
    PORT
      LAYER met3 ;
        RECT 596.000 83.000 600.000 83.600 ;
    END
  END mports_i[502]
  PIN mports_i[503]
    DIRECTION INPUT ;
    USE SIGNAL ;
    ANTENNAGATEAREA 0.247500 ;
    PORT
      LAYER met3 ;
        RECT 596.000 84.360 600.000 84.960 ;
    END
  END mports_i[503]
  PIN mports_i[504]
    DIRECTION INPUT ;
    USE SIGNAL ;
    ANTENNAGATEAREA 0.247500 ;
    PORT
      LAYER met3 ;
        RECT 596.000 85.720 600.000 86.320 ;
    END
  END mports_i[504]
  PIN mports_i[505]
    DIRECTION INPUT ;
    USE SIGNAL ;
    ANTENNAGATEAREA 0.247500 ;
    PORT
      LAYER met3 ;
        RECT 596.000 87.080 600.000 87.680 ;
    END
  END mports_i[505]
  PIN mports_i[506]
    DIRECTION INPUT ;
    USE SIGNAL ;
    ANTENNAGATEAREA 0.247500 ;
    PORT
      LAYER met3 ;
        RECT 596.000 88.440 600.000 89.040 ;
    END
  END mports_i[506]
  PIN mports_i[507]
    DIRECTION INPUT ;
    USE SIGNAL ;
    ANTENNAGATEAREA 0.247500 ;
    PORT
      LAYER met3 ;
        RECT 596.000 89.800 600.000 90.400 ;
    END
  END mports_i[507]
  PIN mports_i[508]
    DIRECTION INPUT ;
    USE SIGNAL ;
    ANTENNAGATEAREA 0.247500 ;
    PORT
      LAYER met3 ;
        RECT 596.000 91.160 600.000 91.760 ;
    END
  END mports_i[508]
  PIN mports_i[509]
    DIRECTION INPUT ;
    USE SIGNAL ;
    ANTENNAGATEAREA 0.213000 ;
    PORT
      LAYER met3 ;
        RECT 596.000 92.520 600.000 93.120 ;
    END
  END mports_i[509]
  PIN mports_i[50]
    DIRECTION INPUT ;
    USE SIGNAL ;
    ANTENNAGATEAREA 0.213000 ;
    PORT
      LAYER met2 ;
        RECT 376.830 296.000 377.110 300.000 ;
    END
  END mports_i[50]
  PIN mports_i[510]
    DIRECTION INPUT ;
    USE SIGNAL ;
    ANTENNAGATEAREA 0.213000 ;
    PORT
      LAYER met3 ;
        RECT 596.000 93.880 600.000 94.480 ;
    END
  END mports_i[510]
  PIN mports_i[511]
    DIRECTION INPUT ;
    USE SIGNAL ;
    ANTENNAGATEAREA 0.213000 ;
    PORT
      LAYER met3 ;
        RECT 596.000 95.240 600.000 95.840 ;
    END
  END mports_i[511]
  PIN mports_i[512]
    DIRECTION INPUT ;
    USE SIGNAL ;
    ANTENNAGATEAREA 0.247500 ;
    PORT
      LAYER met3 ;
        RECT 596.000 96.600 600.000 97.200 ;
    END
  END mports_i[512]
  PIN mports_i[513]
    DIRECTION INPUT ;
    USE SIGNAL ;
    ANTENNAGATEAREA 0.213000 ;
    PORT
      LAYER met3 ;
        RECT 596.000 97.960 600.000 98.560 ;
    END
  END mports_i[513]
  PIN mports_i[514]
    DIRECTION INPUT ;
    USE SIGNAL ;
    ANTENNAGATEAREA 0.213000 ;
    PORT
      LAYER met3 ;
        RECT 596.000 99.320 600.000 99.920 ;
    END
  END mports_i[514]
  PIN mports_i[515]
    DIRECTION INPUT ;
    USE SIGNAL ;
    ANTENNAGATEAREA 0.213000 ;
    PORT
      LAYER met3 ;
        RECT 596.000 100.680 600.000 101.280 ;
    END
  END mports_i[515]
  PIN mports_i[516]
    DIRECTION INPUT ;
    USE SIGNAL ;
    ANTENNAGATEAREA 0.247500 ;
    PORT
      LAYER met3 ;
        RECT 596.000 102.040 600.000 102.640 ;
    END
  END mports_i[516]
  PIN mports_i[517]
    DIRECTION INPUT ;
    USE SIGNAL ;
    ANTENNAGATEAREA 0.159000 ;
    PORT
      LAYER met3 ;
        RECT 596.000 103.400 600.000 104.000 ;
    END
  END mports_i[517]
  PIN mports_i[518]
    DIRECTION INPUT ;
    USE SIGNAL ;
    ANTENNAGATEAREA 0.159000 ;
    PORT
      LAYER met3 ;
        RECT 596.000 104.760 600.000 105.360 ;
    END
  END mports_i[518]
  PIN mports_i[519]
    DIRECTION INPUT ;
    USE SIGNAL ;
    ANTENNAGATEAREA 0.247500 ;
    PORT
      LAYER met3 ;
        RECT 596.000 106.120 600.000 106.720 ;
    END
  END mports_i[519]
  PIN mports_i[51]
    DIRECTION INPUT ;
    USE SIGNAL ;
    ANTENNAGATEAREA 0.213000 ;
    PORT
      LAYER met2 ;
        RECT 377.750 296.000 378.030 300.000 ;
    END
  END mports_i[51]
  PIN mports_i[520]
    DIRECTION INPUT ;
    USE SIGNAL ;
    ANTENNAGATEAREA 0.247500 ;
    PORT
      LAYER met3 ;
        RECT 596.000 107.480 600.000 108.080 ;
    END
  END mports_i[520]
  PIN mports_i[521]
    DIRECTION INPUT ;
    USE SIGNAL ;
    ANTENNAGATEAREA 0.247500 ;
    PORT
      LAYER met3 ;
        RECT 596.000 108.840 600.000 109.440 ;
    END
  END mports_i[521]
  PIN mports_i[522]
    DIRECTION INPUT ;
    USE SIGNAL ;
    ANTENNAGATEAREA 0.247500 ;
    PORT
      LAYER met3 ;
        RECT 596.000 110.200 600.000 110.800 ;
    END
  END mports_i[522]
  PIN mports_i[523]
    DIRECTION INPUT ;
    USE SIGNAL ;
    ANTENNAGATEAREA 0.213000 ;
    PORT
      LAYER met3 ;
        RECT 596.000 111.560 600.000 112.160 ;
    END
  END mports_i[523]
  PIN mports_i[524]
    DIRECTION INPUT ;
    USE SIGNAL ;
    ANTENNAGATEAREA 0.213000 ;
    PORT
      LAYER met3 ;
        RECT 596.000 112.920 600.000 113.520 ;
    END
  END mports_i[524]
  PIN mports_i[525]
    DIRECTION INPUT ;
    USE SIGNAL ;
    ANTENNAGATEAREA 0.213000 ;
    PORT
      LAYER met3 ;
        RECT 596.000 114.280 600.000 114.880 ;
    END
  END mports_i[525]
  PIN mports_i[526]
    DIRECTION INPUT ;
    USE SIGNAL ;
    ANTENNAGATEAREA 0.213000 ;
    PORT
      LAYER met3 ;
        RECT 596.000 115.640 600.000 116.240 ;
    END
  END mports_i[526]
  PIN mports_i[527]
    DIRECTION INPUT ;
    USE SIGNAL ;
    ANTENNAGATEAREA 0.159000 ;
    PORT
      LAYER met3 ;
        RECT 596.000 117.000 600.000 117.600 ;
    END
  END mports_i[527]
  PIN mports_i[528]
    DIRECTION INPUT ;
    USE SIGNAL ;
    ANTENNAGATEAREA 0.159000 ;
    PORT
      LAYER met3 ;
        RECT 596.000 118.360 600.000 118.960 ;
    END
  END mports_i[528]
  PIN mports_i[529]
    DIRECTION INPUT ;
    USE SIGNAL ;
    ANTENNAGATEAREA 0.159000 ;
    PORT
      LAYER met3 ;
        RECT 596.000 119.720 600.000 120.320 ;
    END
  END mports_i[529]
  PIN mports_i[52]
    DIRECTION INPUT ;
    USE SIGNAL ;
    ANTENNAGATEAREA 0.213000 ;
    PORT
      LAYER met2 ;
        RECT 378.670 296.000 378.950 300.000 ;
    END
  END mports_i[52]
  PIN mports_i[530]
    DIRECTION INPUT ;
    USE SIGNAL ;
    ANTENNAGATEAREA 0.247500 ;
    PORT
      LAYER met3 ;
        RECT 596.000 121.080 600.000 121.680 ;
    END
  END mports_i[530]
  PIN mports_i[531]
    DIRECTION INPUT ;
    USE SIGNAL ;
    ANTENNAGATEAREA 0.213000 ;
    PORT
      LAYER met3 ;
        RECT 596.000 122.440 600.000 123.040 ;
    END
  END mports_i[531]
  PIN mports_i[532]
    DIRECTION INPUT ;
    USE SIGNAL ;
    ANTENNAGATEAREA 0.159000 ;
    PORT
      LAYER met3 ;
        RECT 596.000 123.800 600.000 124.400 ;
    END
  END mports_i[532]
  PIN mports_i[533]
    DIRECTION INPUT ;
    USE SIGNAL ;
    ANTENNAGATEAREA 0.213000 ;
    PORT
      LAYER met3 ;
        RECT 596.000 125.160 600.000 125.760 ;
    END
  END mports_i[533]
  PIN mports_i[534]
    DIRECTION INPUT ;
    USE SIGNAL ;
    ANTENNAGATEAREA 0.247500 ;
    PORT
      LAYER met3 ;
        RECT 596.000 126.520 600.000 127.120 ;
    END
  END mports_i[534]
  PIN mports_i[535]
    DIRECTION INPUT ;
    USE SIGNAL ;
    ANTENNAGATEAREA 0.247500 ;
    PORT
      LAYER met3 ;
        RECT 596.000 127.880 600.000 128.480 ;
    END
  END mports_i[535]
  PIN mports_i[536]
    DIRECTION INPUT ;
    USE SIGNAL ;
    ANTENNAGATEAREA 0.159000 ;
    PORT
      LAYER met3 ;
        RECT 596.000 129.240 600.000 129.840 ;
    END
  END mports_i[536]
  PIN mports_i[537]
    DIRECTION INPUT ;
    USE SIGNAL ;
    ANTENNAGATEAREA 0.213000 ;
    PORT
      LAYER met3 ;
        RECT 596.000 130.600 600.000 131.200 ;
    END
  END mports_i[537]
  PIN mports_i[538]
    DIRECTION INPUT ;
    USE SIGNAL ;
    ANTENNAGATEAREA 0.213000 ;
    PORT
      LAYER met3 ;
        RECT 596.000 131.960 600.000 132.560 ;
    END
  END mports_i[538]
  PIN mports_i[539]
    DIRECTION INPUT ;
    USE SIGNAL ;
    ANTENNAGATEAREA 0.213000 ;
    PORT
      LAYER met3 ;
        RECT 596.000 133.320 600.000 133.920 ;
    END
  END mports_i[539]
  PIN mports_i[53]
    DIRECTION INPUT ;
    USE SIGNAL ;
    ANTENNAGATEAREA 0.126000 ;
    PORT
      LAYER met2 ;
        RECT 379.590 296.000 379.870 300.000 ;
    END
  END mports_i[53]
  PIN mports_i[540]
    DIRECTION INPUT ;
    USE SIGNAL ;
    ANTENNAGATEAREA 0.213000 ;
    PORT
      LAYER met3 ;
        RECT 596.000 134.680 600.000 135.280 ;
    END
  END mports_i[540]
  PIN mports_i[541]
    DIRECTION INPUT ;
    USE SIGNAL ;
    ANTENNAGATEAREA 0.213000 ;
    PORT
      LAYER met3 ;
        RECT 596.000 136.040 600.000 136.640 ;
    END
  END mports_i[541]
  PIN mports_i[542]
    DIRECTION INPUT ;
    USE SIGNAL ;
    ANTENNAGATEAREA 0.213000 ;
    PORT
      LAYER met3 ;
        RECT 596.000 137.400 600.000 138.000 ;
    END
  END mports_i[542]
  PIN mports_i[543]
    DIRECTION INPUT ;
    USE SIGNAL ;
    ANTENNAGATEAREA 0.159000 ;
    PORT
      LAYER met3 ;
        RECT 596.000 138.760 600.000 139.360 ;
    END
  END mports_i[543]
  PIN mports_i[544]
    DIRECTION INPUT ;
    USE SIGNAL ;
    ANTENNAGATEAREA 0.159000 ;
    PORT
      LAYER met3 ;
        RECT 596.000 140.120 600.000 140.720 ;
    END
  END mports_i[544]
  PIN mports_i[545]
    DIRECTION INPUT ;
    USE SIGNAL ;
    ANTENNAGATEAREA 0.213000 ;
    PORT
      LAYER met3 ;
        RECT 596.000 141.480 600.000 142.080 ;
    END
  END mports_i[545]
  PIN mports_i[546]
    DIRECTION INPUT ;
    USE SIGNAL ;
    ANTENNAGATEAREA 0.159000 ;
    PORT
      LAYER met3 ;
        RECT 596.000 142.840 600.000 143.440 ;
    END
  END mports_i[546]
  PIN mports_i[547]
    DIRECTION INPUT ;
    USE SIGNAL ;
    ANTENNAGATEAREA 0.247500 ;
    PORT
      LAYER met3 ;
        RECT 596.000 144.200 600.000 144.800 ;
    END
  END mports_i[547]
  PIN mports_i[548]
    DIRECTION INPUT ;
    USE SIGNAL ;
    ANTENNAGATEAREA 0.159000 ;
    PORT
      LAYER met3 ;
        RECT 596.000 145.560 600.000 146.160 ;
    END
  END mports_i[548]
  PIN mports_i[549]
    DIRECTION INPUT ;
    USE SIGNAL ;
    ANTENNAGATEAREA 0.159000 ;
    PORT
      LAYER met3 ;
        RECT 596.000 146.920 600.000 147.520 ;
    END
  END mports_i[549]
  PIN mports_i[54]
    DIRECTION INPUT ;
    USE SIGNAL ;
    ANTENNAGATEAREA 0.126000 ;
    PORT
      LAYER met2 ;
        RECT 380.510 296.000 380.790 300.000 ;
    END
  END mports_i[54]
  PIN mports_i[550]
    DIRECTION INPUT ;
    USE SIGNAL ;
    ANTENNAGATEAREA 0.213000 ;
    PORT
      LAYER met3 ;
        RECT 596.000 148.280 600.000 148.880 ;
    END
  END mports_i[550]
  PIN mports_i[551]
    DIRECTION INPUT ;
    USE SIGNAL ;
    ANTENNAGATEAREA 0.159000 ;
    PORT
      LAYER met3 ;
        RECT 596.000 149.640 600.000 150.240 ;
    END
  END mports_i[551]
  PIN mports_i[55]
    DIRECTION INPUT ;
    USE SIGNAL ;
    ANTENNAGATEAREA 0.196500 ;
    PORT
      LAYER met2 ;
        RECT 381.430 296.000 381.710 300.000 ;
    END
  END mports_i[55]
  PIN mports_i[56]
    DIRECTION INPUT ;
    USE SIGNAL ;
    ANTENNAGATEAREA 0.213000 ;
    PORT
      LAYER met2 ;
        RECT 382.350 296.000 382.630 300.000 ;
    END
  END mports_i[56]
  PIN mports_i[57]
    DIRECTION INPUT ;
    USE SIGNAL ;
    ANTENNAGATEAREA 0.126000 ;
    PORT
      LAYER met2 ;
        RECT 383.270 296.000 383.550 300.000 ;
    END
  END mports_i[57]
  PIN mports_i[58]
    DIRECTION INPUT ;
    USE SIGNAL ;
    ANTENNAGATEAREA 0.196500 ;
    PORT
      LAYER met2 ;
        RECT 384.190 296.000 384.470 300.000 ;
    END
  END mports_i[58]
  PIN mports_i[59]
    DIRECTION INPUT ;
    USE SIGNAL ;
    ANTENNAGATEAREA 0.196500 ;
    PORT
      LAYER met2 ;
        RECT 385.110 296.000 385.390 300.000 ;
    END
  END mports_i[59]
  PIN mports_i[5]
    DIRECTION INPUT ;
    USE SIGNAL ;
    ANTENNAGATEAREA 0.159000 ;
    PORT
      LAYER met2 ;
        RECT 335.430 296.000 335.710 300.000 ;
    END
  END mports_i[5]
  PIN mports_i[60]
    DIRECTION INPUT ;
    USE SIGNAL ;
    ANTENNAGATEAREA 0.196500 ;
    PORT
      LAYER met2 ;
        RECT 386.030 296.000 386.310 300.000 ;
    END
  END mports_i[60]
  PIN mports_i[61]
    DIRECTION INPUT ;
    USE SIGNAL ;
    ANTENNAGATEAREA 0.213000 ;
    PORT
      LAYER met2 ;
        RECT 386.950 296.000 387.230 300.000 ;
    END
  END mports_i[61]
  PIN mports_i[62]
    DIRECTION INPUT ;
    USE SIGNAL ;
    ANTENNAGATEAREA 0.213000 ;
    PORT
      LAYER met2 ;
        RECT 387.870 296.000 388.150 300.000 ;
    END
  END mports_i[62]
  PIN mports_i[63]
    DIRECTION INPUT ;
    USE SIGNAL ;
    ANTENNAGATEAREA 0.126000 ;
    PORT
      LAYER met2 ;
        RECT 388.790 296.000 389.070 300.000 ;
    END
  END mports_i[63]
  PIN mports_i[64]
    DIRECTION INPUT ;
    USE SIGNAL ;
    ANTENNAGATEAREA 0.247500 ;
    PORT
      LAYER met2 ;
        RECT 389.710 296.000 389.990 300.000 ;
    END
  END mports_i[64]
  PIN mports_i[65]
    DIRECTION INPUT ;
    USE SIGNAL ;
    ANTENNAGATEAREA 0.213000 ;
    PORT
      LAYER met2 ;
        RECT 390.630 296.000 390.910 300.000 ;
    END
  END mports_i[65]
  PIN mports_i[66]
    DIRECTION INPUT ;
    USE SIGNAL ;
    ANTENNAGATEAREA 0.196500 ;
    PORT
      LAYER met2 ;
        RECT 391.550 296.000 391.830 300.000 ;
    END
  END mports_i[66]
  PIN mports_i[67]
    DIRECTION INPUT ;
    USE SIGNAL ;
    ANTENNAGATEAREA 0.196500 ;
    PORT
      LAYER met2 ;
        RECT 392.470 296.000 392.750 300.000 ;
    END
  END mports_i[67]
  PIN mports_i[68]
    DIRECTION INPUT ;
    USE SIGNAL ;
    ANTENNAGATEAREA 0.196500 ;
    PORT
      LAYER met2 ;
        RECT 393.390 296.000 393.670 300.000 ;
    END
  END mports_i[68]
  PIN mports_i[69]
    DIRECTION INPUT ;
    USE SIGNAL ;
    ANTENNAGATEAREA 0.213000 ;
    PORT
      LAYER met2 ;
        RECT 236.070 296.000 236.350 300.000 ;
    END
  END mports_i[69]
  PIN mports_i[6]
    DIRECTION INPUT ;
    USE SIGNAL ;
    ANTENNAGATEAREA 0.159000 ;
    PORT
      LAYER met2 ;
        RECT 336.350 296.000 336.630 300.000 ;
    END
  END mports_i[6]
  PIN mports_i[70]
    DIRECTION INPUT ;
    USE SIGNAL ;
    ANTENNAGATEAREA 0.213000 ;
    PORT
      LAYER met2 ;
        RECT 236.990 296.000 237.270 300.000 ;
    END
  END mports_i[70]
  PIN mports_i[71]
    DIRECTION INPUT ;
    USE SIGNAL ;
    ANTENNAGATEAREA 0.213000 ;
    PORT
      LAYER met2 ;
        RECT 237.910 296.000 238.190 300.000 ;
    END
  END mports_i[71]
  PIN mports_i[72]
    DIRECTION INPUT ;
    USE SIGNAL ;
    ANTENNAGATEAREA 0.213000 ;
    PORT
      LAYER met2 ;
        RECT 238.830 296.000 239.110 300.000 ;
    END
  END mports_i[72]
  PIN mports_i[73]
    DIRECTION INPUT ;
    USE SIGNAL ;
    ANTENNAGATEAREA 0.213000 ;
    PORT
      LAYER met2 ;
        RECT 239.750 296.000 240.030 300.000 ;
    END
  END mports_i[73]
  PIN mports_i[74]
    DIRECTION INPUT ;
    USE SIGNAL ;
    ANTENNAGATEAREA 0.213000 ;
    PORT
      LAYER met2 ;
        RECT 240.670 296.000 240.950 300.000 ;
    END
  END mports_i[74]
  PIN mports_i[75]
    DIRECTION INPUT ;
    USE SIGNAL ;
    ANTENNAGATEAREA 0.213000 ;
    PORT
      LAYER met2 ;
        RECT 241.590 296.000 241.870 300.000 ;
    END
  END mports_i[75]
  PIN mports_i[76]
    DIRECTION INPUT ;
    USE SIGNAL ;
    ANTENNAGATEAREA 0.213000 ;
    PORT
      LAYER met2 ;
        RECT 242.510 296.000 242.790 300.000 ;
    END
  END mports_i[76]
  PIN mports_i[77]
    DIRECTION INPUT ;
    USE SIGNAL ;
    ANTENNAGATEAREA 0.213000 ;
    PORT
      LAYER met2 ;
        RECT 243.430 296.000 243.710 300.000 ;
    END
  END mports_i[77]
  PIN mports_i[78]
    DIRECTION INPUT ;
    USE SIGNAL ;
    ANTENNAGATEAREA 0.213000 ;
    PORT
      LAYER met2 ;
        RECT 244.350 296.000 244.630 300.000 ;
    END
  END mports_i[78]
  PIN mports_i[79]
    DIRECTION INPUT ;
    USE SIGNAL ;
    ANTENNAGATEAREA 0.213000 ;
    PORT
      LAYER met2 ;
        RECT 245.270 296.000 245.550 300.000 ;
    END
  END mports_i[79]
  PIN mports_i[7]
    DIRECTION INPUT ;
    USE SIGNAL ;
    ANTENNAGATEAREA 0.159000 ;
    PORT
      LAYER met2 ;
        RECT 337.270 296.000 337.550 300.000 ;
    END
  END mports_i[7]
  PIN mports_i[80]
    DIRECTION INPUT ;
    USE SIGNAL ;
    ANTENNAGATEAREA 0.213000 ;
    PORT
      LAYER met2 ;
        RECT 246.190 296.000 246.470 300.000 ;
    END
  END mports_i[80]
  PIN mports_i[81]
    DIRECTION INPUT ;
    USE SIGNAL ;
    ANTENNAGATEAREA 0.213000 ;
    PORT
      LAYER met2 ;
        RECT 247.110 296.000 247.390 300.000 ;
    END
  END mports_i[81]
  PIN mports_i[82]
    DIRECTION INPUT ;
    USE SIGNAL ;
    ANTENNAGATEAREA 0.213000 ;
    PORT
      LAYER met2 ;
        RECT 248.030 296.000 248.310 300.000 ;
    END
  END mports_i[82]
  PIN mports_i[83]
    DIRECTION INPUT ;
    USE SIGNAL ;
    ANTENNAGATEAREA 0.213000 ;
    PORT
      LAYER met2 ;
        RECT 248.950 296.000 249.230 300.000 ;
    END
  END mports_i[83]
  PIN mports_i[84]
    DIRECTION INPUT ;
    USE SIGNAL ;
    ANTENNAGATEAREA 0.159000 ;
    PORT
      LAYER met2 ;
        RECT 249.870 296.000 250.150 300.000 ;
    END
  END mports_i[84]
  PIN mports_i[85]
    DIRECTION INPUT ;
    USE SIGNAL ;
    ANTENNAGATEAREA 0.213000 ;
    PORT
      LAYER met2 ;
        RECT 250.790 296.000 251.070 300.000 ;
    END
  END mports_i[85]
  PIN mports_i[86]
    DIRECTION INPUT ;
    USE SIGNAL ;
    ANTENNAGATEAREA 0.126000 ;
    PORT
      LAYER met2 ;
        RECT 251.710 296.000 251.990 300.000 ;
    END
  END mports_i[86]
  PIN mports_i[87]
    DIRECTION INPUT ;
    USE SIGNAL ;
    ANTENNAGATEAREA 0.213000 ;
    PORT
      LAYER met2 ;
        RECT 252.630 296.000 252.910 300.000 ;
    END
  END mports_i[87]
  PIN mports_i[88]
    DIRECTION INPUT ;
    USE SIGNAL ;
    ANTENNAGATEAREA 0.213000 ;
    PORT
      LAYER met2 ;
        RECT 253.550 296.000 253.830 300.000 ;
    END
  END mports_i[88]
  PIN mports_i[89]
    DIRECTION INPUT ;
    USE SIGNAL ;
    ANTENNAGATEAREA 0.213000 ;
    PORT
      LAYER met2 ;
        RECT 254.470 296.000 254.750 300.000 ;
    END
  END mports_i[89]
  PIN mports_i[8]
    DIRECTION INPUT ;
    USE SIGNAL ;
    ANTENNAGATEAREA 0.159000 ;
    PORT
      LAYER met2 ;
        RECT 338.190 296.000 338.470 300.000 ;
    END
  END mports_i[8]
  PIN mports_i[90]
    DIRECTION INPUT ;
    USE SIGNAL ;
    ANTENNAGATEAREA 0.126000 ;
    PORT
      LAYER met2 ;
        RECT 255.390 296.000 255.670 300.000 ;
    END
  END mports_i[90]
  PIN mports_i[91]
    DIRECTION INPUT ;
    USE SIGNAL ;
    ANTENNAGATEAREA 0.196500 ;
    PORT
      LAYER met2 ;
        RECT 256.310 296.000 256.590 300.000 ;
    END
  END mports_i[91]
  PIN mports_i[92]
    DIRECTION INPUT ;
    USE SIGNAL ;
    ANTENNAGATEAREA 0.196500 ;
    PORT
      LAYER met2 ;
        RECT 257.230 296.000 257.510 300.000 ;
    END
  END mports_i[92]
  PIN mports_i[93]
    DIRECTION INPUT ;
    USE SIGNAL ;
    ANTENNAGATEAREA 0.213000 ;
    PORT
      LAYER met2 ;
        RECT 258.150 296.000 258.430 300.000 ;
    END
  END mports_i[93]
  PIN mports_i[94]
    DIRECTION INPUT ;
    USE SIGNAL ;
    ANTENNAGATEAREA 0.213000 ;
    PORT
      LAYER met2 ;
        RECT 259.070 296.000 259.350 300.000 ;
    END
  END mports_i[94]
  PIN mports_i[95]
    DIRECTION INPUT ;
    USE SIGNAL ;
    ANTENNAGATEAREA 0.213000 ;
    PORT
      LAYER met2 ;
        RECT 259.990 296.000 260.270 300.000 ;
    END
  END mports_i[95]
  PIN mports_i[96]
    DIRECTION INPUT ;
    USE SIGNAL ;
    ANTENNAGATEAREA 0.213000 ;
    PORT
      LAYER met2 ;
        RECT 260.910 296.000 261.190 300.000 ;
    END
  END mports_i[96]
  PIN mports_i[97]
    DIRECTION INPUT ;
    USE SIGNAL ;
    ANTENNAGATEAREA 0.126000 ;
    PORT
      LAYER met2 ;
        RECT 261.830 296.000 262.110 300.000 ;
    END
  END mports_i[97]
  PIN mports_i[98]
    DIRECTION INPUT ;
    USE SIGNAL ;
    ANTENNAGATEAREA 0.126000 ;
    PORT
      LAYER met2 ;
        RECT 262.750 296.000 263.030 300.000 ;
    END
  END mports_i[98]
  PIN mports_i[99]
    DIRECTION INPUT ;
    USE SIGNAL ;
    ANTENNAGATEAREA 0.126000 ;
    PORT
      LAYER met2 ;
        RECT 263.670 296.000 263.950 300.000 ;
    END
  END mports_i[99]
  PIN mports_i[9]
    DIRECTION INPUT ;
    USE SIGNAL ;
    ANTENNAGATEAREA 0.213000 ;
    PORT
      LAYER met2 ;
        RECT 339.110 296.000 339.390 300.000 ;
    END
  END mports_i[9]
  PIN mports_o[0]
    DIRECTION OUTPUT TRISTATE ;
    USE SIGNAL ;
    ANTENNADIFFAREA 0.795200 ;
    PORT
      LAYER met2 ;
        RECT 299.550 296.000 299.830 300.000 ;
    END
  END mports_o[0]
  PIN mports_o[100]
    DIRECTION OUTPUT TRISTATE ;
    USE SIGNAL ;
    ANTENNADIFFAREA 0.795200 ;
    PORT
      LAYER met2 ;
        RECT 107.730 0.000 108.010 4.000 ;
    END
  END mports_o[100]
  PIN mports_o[101]
    DIRECTION OUTPUT TRISTATE ;
    USE SIGNAL ;
    ANTENNADIFFAREA 0.795200 ;
    PORT
      LAYER met2 ;
        RECT 110.490 0.000 110.770 4.000 ;
    END
  END mports_o[101]
  PIN mports_o[102]
    DIRECTION OUTPUT TRISTATE ;
    USE SIGNAL ;
    ANTENNADIFFAREA 0.795200 ;
    PORT
      LAYER met2 ;
        RECT 303.690 0.000 303.970 4.000 ;
    END
  END mports_o[102]
  PIN mports_o[103]
    DIRECTION OUTPUT TRISTATE ;
    USE SIGNAL ;
    ANTENNADIFFAREA 0.795200 ;
    PORT
      LAYER met2 ;
        RECT 306.450 0.000 306.730 4.000 ;
    END
  END mports_o[103]
  PIN mports_o[104]
    DIRECTION OUTPUT TRISTATE ;
    USE SIGNAL ;
    ANTENNADIFFAREA 0.795200 ;
    PORT
      LAYER met2 ;
        RECT 309.210 0.000 309.490 4.000 ;
    END
  END mports_o[104]
  PIN mports_o[105]
    DIRECTION OUTPUT TRISTATE ;
    USE SIGNAL ;
    ANTENNADIFFAREA 0.795200 ;
    PORT
      LAYER met2 ;
        RECT 311.970 0.000 312.250 4.000 ;
    END
  END mports_o[105]
  PIN mports_o[106]
    DIRECTION OUTPUT TRISTATE ;
    USE SIGNAL ;
    ANTENNADIFFAREA 0.795200 ;
    PORT
      LAYER met2 ;
        RECT 314.730 0.000 315.010 4.000 ;
    END
  END mports_o[106]
  PIN mports_o[107]
    DIRECTION OUTPUT TRISTATE ;
    USE SIGNAL ;
    ANTENNADIFFAREA 0.795200 ;
    PORT
      LAYER met2 ;
        RECT 317.490 0.000 317.770 4.000 ;
    END
  END mports_o[107]
  PIN mports_o[108]
    DIRECTION OUTPUT TRISTATE ;
    USE SIGNAL ;
    ANTENNADIFFAREA 0.795200 ;
    PORT
      LAYER met2 ;
        RECT 320.250 0.000 320.530 4.000 ;
    END
  END mports_o[108]
  PIN mports_o[109]
    DIRECTION OUTPUT TRISTATE ;
    USE SIGNAL ;
    ANTENNADIFFAREA 0.795200 ;
    PORT
      LAYER met2 ;
        RECT 323.010 0.000 323.290 4.000 ;
    END
  END mports_o[109]
  PIN mports_o[10]
    DIRECTION OUTPUT TRISTATE ;
    USE SIGNAL ;
    ANTENNADIFFAREA 0.795200 ;
    PORT
      LAYER met2 ;
        RECT 308.750 296.000 309.030 300.000 ;
    END
  END mports_o[10]
  PIN mports_o[110]
    DIRECTION OUTPUT TRISTATE ;
    USE SIGNAL ;
    ANTENNADIFFAREA 0.795200 ;
    PORT
      LAYER met2 ;
        RECT 325.770 0.000 326.050 4.000 ;
    END
  END mports_o[110]
  PIN mports_o[111]
    DIRECTION OUTPUT TRISTATE ;
    USE SIGNAL ;
    ANTENNADIFFAREA 0.795200 ;
    PORT
      LAYER met2 ;
        RECT 328.530 0.000 328.810 4.000 ;
    END
  END mports_o[111]
  PIN mports_o[112]
    DIRECTION OUTPUT TRISTATE ;
    USE SIGNAL ;
    ANTENNADIFFAREA 0.795200 ;
    PORT
      LAYER met2 ;
        RECT 331.290 0.000 331.570 4.000 ;
    END
  END mports_o[112]
  PIN mports_o[113]
    DIRECTION OUTPUT TRISTATE ;
    USE SIGNAL ;
    ANTENNADIFFAREA 0.795200 ;
    PORT
      LAYER met2 ;
        RECT 334.050 0.000 334.330 4.000 ;
    END
  END mports_o[113]
  PIN mports_o[114]
    DIRECTION OUTPUT TRISTATE ;
    USE SIGNAL ;
    ANTENNADIFFAREA 0.795200 ;
    PORT
      LAYER met2 ;
        RECT 336.810 0.000 337.090 4.000 ;
    END
  END mports_o[114]
  PIN mports_o[115]
    DIRECTION OUTPUT TRISTATE ;
    USE SIGNAL ;
    ANTENNADIFFAREA 0.795200 ;
    PORT
      LAYER met2 ;
        RECT 339.570 0.000 339.850 4.000 ;
    END
  END mports_o[115]
  PIN mports_o[116]
    DIRECTION OUTPUT TRISTATE ;
    USE SIGNAL ;
    ANTENNADIFFAREA 0.795200 ;
    PORT
      LAYER met2 ;
        RECT 342.330 0.000 342.610 4.000 ;
    END
  END mports_o[116]
  PIN mports_o[117]
    DIRECTION OUTPUT TRISTATE ;
    USE SIGNAL ;
    ANTENNADIFFAREA 0.795200 ;
    PORT
      LAYER met2 ;
        RECT 345.090 0.000 345.370 4.000 ;
    END
  END mports_o[117]
  PIN mports_o[118]
    DIRECTION OUTPUT TRISTATE ;
    USE SIGNAL ;
    ANTENNADIFFAREA 0.795200 ;
    PORT
      LAYER met2 ;
        RECT 347.850 0.000 348.130 4.000 ;
    END
  END mports_o[118]
  PIN mports_o[119]
    DIRECTION OUTPUT TRISTATE ;
    USE SIGNAL ;
    ANTENNADIFFAREA 0.795200 ;
    PORT
      LAYER met2 ;
        RECT 350.610 0.000 350.890 4.000 ;
    END
  END mports_o[119]
  PIN mports_o[11]
    DIRECTION OUTPUT TRISTATE ;
    USE SIGNAL ;
    ANTENNADIFFAREA 0.795200 ;
    PORT
      LAYER met2 ;
        RECT 309.670 296.000 309.950 300.000 ;
    END
  END mports_o[11]
  PIN mports_o[120]
    DIRECTION OUTPUT TRISTATE ;
    USE SIGNAL ;
    ANTENNADIFFAREA 0.795200 ;
    PORT
      LAYER met2 ;
        RECT 353.370 0.000 353.650 4.000 ;
    END
  END mports_o[120]
  PIN mports_o[121]
    DIRECTION OUTPUT TRISTATE ;
    USE SIGNAL ;
    ANTENNADIFFAREA 0.795200 ;
    PORT
      LAYER met2 ;
        RECT 356.130 0.000 356.410 4.000 ;
    END
  END mports_o[121]
  PIN mports_o[122]
    DIRECTION OUTPUT TRISTATE ;
    USE SIGNAL ;
    ANTENNADIFFAREA 0.795200 ;
    PORT
      LAYER met2 ;
        RECT 358.890 0.000 359.170 4.000 ;
    END
  END mports_o[122]
  PIN mports_o[123]
    DIRECTION OUTPUT TRISTATE ;
    USE SIGNAL ;
    ANTENNADIFFAREA 0.795200 ;
    PORT
      LAYER met2 ;
        RECT 361.650 0.000 361.930 4.000 ;
    END
  END mports_o[123]
  PIN mports_o[124]
    DIRECTION OUTPUT TRISTATE ;
    USE SIGNAL ;
    ANTENNADIFFAREA 0.795200 ;
    PORT
      LAYER met2 ;
        RECT 364.410 0.000 364.690 4.000 ;
    END
  END mports_o[124]
  PIN mports_o[125]
    DIRECTION OUTPUT TRISTATE ;
    USE SIGNAL ;
    ANTENNADIFFAREA 0.795200 ;
    PORT
      LAYER met2 ;
        RECT 367.170 0.000 367.450 4.000 ;
    END
  END mports_o[125]
  PIN mports_o[126]
    DIRECTION OUTPUT TRISTATE ;
    USE SIGNAL ;
    ANTENNADIFFAREA 0.795200 ;
    PORT
      LAYER met2 ;
        RECT 369.930 0.000 370.210 4.000 ;
    END
  END mports_o[126]
  PIN mports_o[127]
    DIRECTION OUTPUT TRISTATE ;
    USE SIGNAL ;
    ANTENNADIFFAREA 0.795200 ;
    PORT
      LAYER met2 ;
        RECT 372.690 0.000 372.970 4.000 ;
    END
  END mports_o[127]
  PIN mports_o[128]
    DIRECTION OUTPUT TRISTATE ;
    USE SIGNAL ;
    ANTENNADIFFAREA 0.795200 ;
    PORT
      LAYER met2 ;
        RECT 375.450 0.000 375.730 4.000 ;
    END
  END mports_o[128]
  PIN mports_o[129]
    DIRECTION OUTPUT TRISTATE ;
    USE SIGNAL ;
    ANTENNADIFFAREA 0.795200 ;
    PORT
      LAYER met2 ;
        RECT 378.210 0.000 378.490 4.000 ;
    END
  END mports_o[129]
  PIN mports_o[12]
    DIRECTION OUTPUT TRISTATE ;
    USE SIGNAL ;
    ANTENNADIFFAREA 0.795200 ;
    PORT
      LAYER met2 ;
        RECT 310.590 296.000 310.870 300.000 ;
    END
  END mports_o[12]
  PIN mports_o[130]
    DIRECTION OUTPUT TRISTATE ;
    USE SIGNAL ;
    ANTENNADIFFAREA 0.795200 ;
    PORT
      LAYER met2 ;
        RECT 380.970 0.000 381.250 4.000 ;
    END
  END mports_o[130]
  PIN mports_o[131]
    DIRECTION OUTPUT TRISTATE ;
    USE SIGNAL ;
    ANTENNADIFFAREA 0.795200 ;
    PORT
      LAYER met2 ;
        RECT 383.730 0.000 384.010 4.000 ;
    END
  END mports_o[131]
  PIN mports_o[132]
    DIRECTION OUTPUT TRISTATE ;
    USE SIGNAL ;
    ANTENNADIFFAREA 0.795200 ;
    PORT
      LAYER met2 ;
        RECT 386.490 0.000 386.770 4.000 ;
    END
  END mports_o[132]
  PIN mports_o[133]
    DIRECTION OUTPUT TRISTATE ;
    USE SIGNAL ;
    ANTENNADIFFAREA 0.795200 ;
    PORT
      LAYER met2 ;
        RECT 389.250 0.000 389.530 4.000 ;
    END
  END mports_o[133]
  PIN mports_o[134]
    DIRECTION OUTPUT TRISTATE ;
    USE SIGNAL ;
    ANTENNADIFFAREA 0.795200 ;
    PORT
      LAYER met2 ;
        RECT 392.010 0.000 392.290 4.000 ;
    END
  END mports_o[134]
  PIN mports_o[135]
    DIRECTION OUTPUT TRISTATE ;
    USE SIGNAL ;
    ANTENNADIFFAREA 0.795200 ;
    PORT
      LAYER met2 ;
        RECT 394.770 0.000 395.050 4.000 ;
    END
  END mports_o[135]
  PIN mports_o[136]
    DIRECTION OUTPUT TRISTATE ;
    USE SIGNAL ;
    ANTENNADIFFAREA 0.795200 ;
    PORT
      LAYER met2 ;
        RECT 15.270 296.000 15.550 300.000 ;
    END
  END mports_o[136]
  PIN mports_o[137]
    DIRECTION OUTPUT TRISTATE ;
    USE SIGNAL ;
    ANTENNADIFFAREA 0.795200 ;
    PORT
      LAYER met2 ;
        RECT 16.190 296.000 16.470 300.000 ;
    END
  END mports_o[137]
  PIN mports_o[138]
    DIRECTION OUTPUT TRISTATE ;
    USE SIGNAL ;
    ANTENNADIFFAREA 0.795200 ;
    PORT
      LAYER met2 ;
        RECT 17.110 296.000 17.390 300.000 ;
    END
  END mports_o[138]
  PIN mports_o[139]
    DIRECTION OUTPUT TRISTATE ;
    USE SIGNAL ;
    ANTENNADIFFAREA 0.795200 ;
    PORT
      LAYER met2 ;
        RECT 18.030 296.000 18.310 300.000 ;
    END
  END mports_o[139]
  PIN mports_o[13]
    DIRECTION OUTPUT TRISTATE ;
    USE SIGNAL ;
    ANTENNADIFFAREA 0.795200 ;
    PORT
      LAYER met2 ;
        RECT 311.510 296.000 311.790 300.000 ;
    END
  END mports_o[13]
  PIN mports_o[140]
    DIRECTION OUTPUT TRISTATE ;
    USE SIGNAL ;
    ANTENNADIFFAREA 0.795200 ;
    PORT
      LAYER met2 ;
        RECT 18.950 296.000 19.230 300.000 ;
    END
  END mports_o[140]
  PIN mports_o[141]
    DIRECTION OUTPUT TRISTATE ;
    USE SIGNAL ;
    ANTENNADIFFAREA 0.795200 ;
    PORT
      LAYER met2 ;
        RECT 19.870 296.000 20.150 300.000 ;
    END
  END mports_o[141]
  PIN mports_o[142]
    DIRECTION OUTPUT TRISTATE ;
    USE SIGNAL ;
    ANTENNADIFFAREA 0.795200 ;
    PORT
      LAYER met2 ;
        RECT 20.790 296.000 21.070 300.000 ;
    END
  END mports_o[142]
  PIN mports_o[143]
    DIRECTION OUTPUT TRISTATE ;
    USE SIGNAL ;
    ANTENNADIFFAREA 0.795200 ;
    PORT
      LAYER met2 ;
        RECT 21.710 296.000 21.990 300.000 ;
    END
  END mports_o[143]
  PIN mports_o[144]
    DIRECTION OUTPUT TRISTATE ;
    USE SIGNAL ;
    ANTENNADIFFAREA 0.795200 ;
    PORT
      LAYER met2 ;
        RECT 22.630 296.000 22.910 300.000 ;
    END
  END mports_o[144]
  PIN mports_o[145]
    DIRECTION OUTPUT TRISTATE ;
    USE SIGNAL ;
    ANTENNADIFFAREA 0.795200 ;
    PORT
      LAYER met2 ;
        RECT 23.550 296.000 23.830 300.000 ;
    END
  END mports_o[145]
  PIN mports_o[146]
    DIRECTION OUTPUT TRISTATE ;
    USE SIGNAL ;
    ANTENNADIFFAREA 0.795200 ;
    PORT
      LAYER met2 ;
        RECT 24.470 296.000 24.750 300.000 ;
    END
  END mports_o[146]
  PIN mports_o[147]
    DIRECTION OUTPUT TRISTATE ;
    USE SIGNAL ;
    ANTENNADIFFAREA 0.795200 ;
    PORT
      LAYER met2 ;
        RECT 25.390 296.000 25.670 300.000 ;
    END
  END mports_o[147]
  PIN mports_o[148]
    DIRECTION OUTPUT TRISTATE ;
    USE SIGNAL ;
    ANTENNADIFFAREA 0.795200 ;
    PORT
      LAYER met2 ;
        RECT 26.310 296.000 26.590 300.000 ;
    END
  END mports_o[148]
  PIN mports_o[149]
    DIRECTION OUTPUT TRISTATE ;
    USE SIGNAL ;
    ANTENNADIFFAREA 0.795200 ;
    PORT
      LAYER met2 ;
        RECT 27.230 296.000 27.510 300.000 ;
    END
  END mports_o[149]
  PIN mports_o[14]
    DIRECTION OUTPUT TRISTATE ;
    USE SIGNAL ;
    ANTENNADIFFAREA 0.795200 ;
    PORT
      LAYER met2 ;
        RECT 312.430 296.000 312.710 300.000 ;
    END
  END mports_o[14]
  PIN mports_o[150]
    DIRECTION OUTPUT TRISTATE ;
    USE SIGNAL ;
    ANTENNADIFFAREA 0.795200 ;
    PORT
      LAYER met2 ;
        RECT 28.150 296.000 28.430 300.000 ;
    END
  END mports_o[150]
  PIN mports_o[151]
    DIRECTION OUTPUT TRISTATE ;
    USE SIGNAL ;
    ANTENNADIFFAREA 0.795200 ;
    PORT
      LAYER met2 ;
        RECT 29.070 296.000 29.350 300.000 ;
    END
  END mports_o[151]
  PIN mports_o[152]
    DIRECTION OUTPUT TRISTATE ;
    USE SIGNAL ;
    ANTENNADIFFAREA 0.795200 ;
    PORT
      LAYER met2 ;
        RECT 29.990 296.000 30.270 300.000 ;
    END
  END mports_o[152]
  PIN mports_o[153]
    DIRECTION OUTPUT TRISTATE ;
    USE SIGNAL ;
    ANTENNADIFFAREA 0.795200 ;
    PORT
      LAYER met2 ;
        RECT 30.910 296.000 31.190 300.000 ;
    END
  END mports_o[153]
  PIN mports_o[154]
    DIRECTION OUTPUT TRISTATE ;
    USE SIGNAL ;
    ANTENNADIFFAREA 0.795200 ;
    PORT
      LAYER met2 ;
        RECT 31.830 296.000 32.110 300.000 ;
    END
  END mports_o[154]
  PIN mports_o[155]
    DIRECTION OUTPUT TRISTATE ;
    USE SIGNAL ;
    ANTENNADIFFAREA 0.795200 ;
    PORT
      LAYER met2 ;
        RECT 32.750 296.000 33.030 300.000 ;
    END
  END mports_o[155]
  PIN mports_o[156]
    DIRECTION OUTPUT TRISTATE ;
    USE SIGNAL ;
    ANTENNADIFFAREA 0.795200 ;
    PORT
      LAYER met2 ;
        RECT 33.670 296.000 33.950 300.000 ;
    END
  END mports_o[156]
  PIN mports_o[157]
    DIRECTION OUTPUT TRISTATE ;
    USE SIGNAL ;
    ANTENNADIFFAREA 0.795200 ;
    PORT
      LAYER met2 ;
        RECT 34.590 296.000 34.870 300.000 ;
    END
  END mports_o[157]
  PIN mports_o[158]
    DIRECTION OUTPUT TRISTATE ;
    USE SIGNAL ;
    ANTENNADIFFAREA 0.795200 ;
    PORT
      LAYER met2 ;
        RECT 35.510 296.000 35.790 300.000 ;
    END
  END mports_o[158]
  PIN mports_o[159]
    DIRECTION OUTPUT TRISTATE ;
    USE SIGNAL ;
    ANTENNADIFFAREA 0.795200 ;
    PORT
      LAYER met2 ;
        RECT 36.430 296.000 36.710 300.000 ;
    END
  END mports_o[159]
  PIN mports_o[15]
    DIRECTION OUTPUT TRISTATE ;
    USE SIGNAL ;
    ANTENNADIFFAREA 0.795200 ;
    PORT
      LAYER met2 ;
        RECT 313.350 296.000 313.630 300.000 ;
    END
  END mports_o[15]
  PIN mports_o[160]
    DIRECTION OUTPUT TRISTATE ;
    USE SIGNAL ;
    ANTENNADIFFAREA 0.795200 ;
    PORT
      LAYER met2 ;
        RECT 37.350 296.000 37.630 300.000 ;
    END
  END mports_o[160]
  PIN mports_o[161]
    DIRECTION OUTPUT TRISTATE ;
    USE SIGNAL ;
    ANTENNADIFFAREA 0.795200 ;
    PORT
      LAYER met2 ;
        RECT 38.270 296.000 38.550 300.000 ;
    END
  END mports_o[161]
  PIN mports_o[162]
    DIRECTION OUTPUT TRISTATE ;
    USE SIGNAL ;
    ANTENNADIFFAREA 0.795200 ;
    PORT
      LAYER met2 ;
        RECT 39.190 296.000 39.470 300.000 ;
    END
  END mports_o[162]
  PIN mports_o[163]
    DIRECTION OUTPUT TRISTATE ;
    USE SIGNAL ;
    ANTENNADIFFAREA 0.795200 ;
    PORT
      LAYER met2 ;
        RECT 40.110 296.000 40.390 300.000 ;
    END
  END mports_o[163]
  PIN mports_o[164]
    DIRECTION OUTPUT TRISTATE ;
    USE SIGNAL ;
    ANTENNADIFFAREA 0.795200 ;
    PORT
      LAYER met2 ;
        RECT 41.030 296.000 41.310 300.000 ;
    END
  END mports_o[164]
  PIN mports_o[165]
    DIRECTION OUTPUT TRISTATE ;
    USE SIGNAL ;
    ANTENNADIFFAREA 0.795200 ;
    PORT
      LAYER met2 ;
        RECT 41.950 296.000 42.230 300.000 ;
    END
  END mports_o[165]
  PIN mports_o[166]
    DIRECTION OUTPUT TRISTATE ;
    USE SIGNAL ;
    ANTENNADIFFAREA 0.795200 ;
    PORT
      LAYER met2 ;
        RECT 42.870 296.000 43.150 300.000 ;
    END
  END mports_o[166]
  PIN mports_o[167]
    DIRECTION OUTPUT TRISTATE ;
    USE SIGNAL ;
    ANTENNADIFFAREA 0.795200 ;
    PORT
      LAYER met2 ;
        RECT 43.790 296.000 44.070 300.000 ;
    END
  END mports_o[167]
  PIN mports_o[168]
    DIRECTION OUTPUT TRISTATE ;
    USE SIGNAL ;
    ANTENNADIFFAREA 0.795200 ;
    PORT
      LAYER met2 ;
        RECT 44.710 296.000 44.990 300.000 ;
    END
  END mports_o[168]
  PIN mports_o[169]
    DIRECTION OUTPUT TRISTATE ;
    USE SIGNAL ;
    ANTENNADIFFAREA 0.795200 ;
    PORT
      LAYER met2 ;
        RECT 45.630 296.000 45.910 300.000 ;
    END
  END mports_o[169]
  PIN mports_o[16]
    DIRECTION OUTPUT TRISTATE ;
    USE SIGNAL ;
    ANTENNADIFFAREA 0.795200 ;
    PORT
      LAYER met2 ;
        RECT 314.270 296.000 314.550 300.000 ;
    END
  END mports_o[16]
  PIN mports_o[170]
    DIRECTION OUTPUT TRISTATE ;
    USE SIGNAL ;
    ANTENNADIFFAREA 0.795200 ;
    PORT
      LAYER met2 ;
        RECT 110.030 296.000 110.310 300.000 ;
    END
  END mports_o[170]
  PIN mports_o[171]
    DIRECTION OUTPUT TRISTATE ;
    USE SIGNAL ;
    ANTENNADIFFAREA 0.795200 ;
    PORT
      LAYER met2 ;
        RECT 110.950 296.000 111.230 300.000 ;
    END
  END mports_o[171]
  PIN mports_o[172]
    DIRECTION OUTPUT TRISTATE ;
    USE SIGNAL ;
    ANTENNADIFFAREA 0.795200 ;
    PORT
      LAYER met2 ;
        RECT 111.870 296.000 112.150 300.000 ;
    END
  END mports_o[172]
  PIN mports_o[173]
    DIRECTION OUTPUT TRISTATE ;
    USE SIGNAL ;
    ANTENNADIFFAREA 0.795200 ;
    PORT
      LAYER met2 ;
        RECT 112.790 296.000 113.070 300.000 ;
    END
  END mports_o[173]
  PIN mports_o[174]
    DIRECTION OUTPUT TRISTATE ;
    USE SIGNAL ;
    ANTENNADIFFAREA 0.795200 ;
    PORT
      LAYER met2 ;
        RECT 113.710 296.000 113.990 300.000 ;
    END
  END mports_o[174]
  PIN mports_o[175]
    DIRECTION OUTPUT TRISTATE ;
    USE SIGNAL ;
    ANTENNADIFFAREA 0.795200 ;
    PORT
      LAYER met2 ;
        RECT 114.630 296.000 114.910 300.000 ;
    END
  END mports_o[175]
  PIN mports_o[176]
    DIRECTION OUTPUT TRISTATE ;
    USE SIGNAL ;
    ANTENNADIFFAREA 0.795200 ;
    PORT
      LAYER met2 ;
        RECT 115.550 296.000 115.830 300.000 ;
    END
  END mports_o[176]
  PIN mports_o[177]
    DIRECTION OUTPUT TRISTATE ;
    USE SIGNAL ;
    ANTENNADIFFAREA 0.795200 ;
    PORT
      LAYER met2 ;
        RECT 116.470 296.000 116.750 300.000 ;
    END
  END mports_o[177]
  PIN mports_o[178]
    DIRECTION OUTPUT TRISTATE ;
    USE SIGNAL ;
    ANTENNADIFFAREA 0.795200 ;
    PORT
      LAYER met2 ;
        RECT 117.390 296.000 117.670 300.000 ;
    END
  END mports_o[178]
  PIN mports_o[179]
    DIRECTION OUTPUT TRISTATE ;
    USE SIGNAL ;
    ANTENNADIFFAREA 0.795200 ;
    PORT
      LAYER met2 ;
        RECT 118.310 296.000 118.590 300.000 ;
    END
  END mports_o[179]
  PIN mports_o[17]
    DIRECTION OUTPUT TRISTATE ;
    USE SIGNAL ;
    ANTENNADIFFAREA 0.795200 ;
    PORT
      LAYER met2 ;
        RECT 315.190 296.000 315.470 300.000 ;
    END
  END mports_o[17]
  PIN mports_o[180]
    DIRECTION OUTPUT TRISTATE ;
    USE SIGNAL ;
    ANTENNADIFFAREA 0.795200 ;
    PORT
      LAYER met2 ;
        RECT 119.230 296.000 119.510 300.000 ;
    END
  END mports_o[180]
  PIN mports_o[181]
    DIRECTION OUTPUT TRISTATE ;
    USE SIGNAL ;
    ANTENNADIFFAREA 0.795200 ;
    PORT
      LAYER met2 ;
        RECT 120.150 296.000 120.430 300.000 ;
    END
  END mports_o[181]
  PIN mports_o[182]
    DIRECTION OUTPUT TRISTATE ;
    USE SIGNAL ;
    ANTENNADIFFAREA 0.795200 ;
    PORT
      LAYER met2 ;
        RECT 121.070 296.000 121.350 300.000 ;
    END
  END mports_o[182]
  PIN mports_o[183]
    DIRECTION OUTPUT TRISTATE ;
    USE SIGNAL ;
    ANTENNADIFFAREA 0.795200 ;
    PORT
      LAYER met2 ;
        RECT 121.990 296.000 122.270 300.000 ;
    END
  END mports_o[183]
  PIN mports_o[184]
    DIRECTION OUTPUT TRISTATE ;
    USE SIGNAL ;
    ANTENNADIFFAREA 0.795200 ;
    PORT
      LAYER met2 ;
        RECT 122.910 296.000 123.190 300.000 ;
    END
  END mports_o[184]
  PIN mports_o[185]
    DIRECTION OUTPUT TRISTATE ;
    USE SIGNAL ;
    ANTENNADIFFAREA 0.795200 ;
    PORT
      LAYER met2 ;
        RECT 123.830 296.000 124.110 300.000 ;
    END
  END mports_o[185]
  PIN mports_o[186]
    DIRECTION OUTPUT TRISTATE ;
    USE SIGNAL ;
    ANTENNADIFFAREA 0.795200 ;
    PORT
      LAYER met2 ;
        RECT 124.750 296.000 125.030 300.000 ;
    END
  END mports_o[186]
  PIN mports_o[187]
    DIRECTION OUTPUT TRISTATE ;
    USE SIGNAL ;
    ANTENNADIFFAREA 0.795200 ;
    PORT
      LAYER met2 ;
        RECT 125.670 296.000 125.950 300.000 ;
    END
  END mports_o[187]
  PIN mports_o[188]
    DIRECTION OUTPUT TRISTATE ;
    USE SIGNAL ;
    ANTENNADIFFAREA 0.795200 ;
    PORT
      LAYER met2 ;
        RECT 126.590 296.000 126.870 300.000 ;
    END
  END mports_o[188]
  PIN mports_o[189]
    DIRECTION OUTPUT TRISTATE ;
    USE SIGNAL ;
    ANTENNADIFFAREA 0.795200 ;
    PORT
      LAYER met2 ;
        RECT 127.510 296.000 127.790 300.000 ;
    END
  END mports_o[189]
  PIN mports_o[18]
    DIRECTION OUTPUT TRISTATE ;
    USE SIGNAL ;
    ANTENNADIFFAREA 0.795200 ;
    PORT
      LAYER met2 ;
        RECT 316.110 296.000 316.390 300.000 ;
    END
  END mports_o[18]
  PIN mports_o[190]
    DIRECTION OUTPUT TRISTATE ;
    USE SIGNAL ;
    ANTENNADIFFAREA 0.795200 ;
    PORT
      LAYER met2 ;
        RECT 128.430 296.000 128.710 300.000 ;
    END
  END mports_o[190]
  PIN mports_o[191]
    DIRECTION OUTPUT TRISTATE ;
    USE SIGNAL ;
    ANTENNADIFFAREA 0.795200 ;
    PORT
      LAYER met2 ;
        RECT 129.350 296.000 129.630 300.000 ;
    END
  END mports_o[191]
  PIN mports_o[192]
    DIRECTION OUTPUT TRISTATE ;
    USE SIGNAL ;
    ANTENNADIFFAREA 0.795200 ;
    PORT
      LAYER met2 ;
        RECT 130.270 296.000 130.550 300.000 ;
    END
  END mports_o[192]
  PIN mports_o[193]
    DIRECTION OUTPUT TRISTATE ;
    USE SIGNAL ;
    ANTENNADIFFAREA 0.795200 ;
    PORT
      LAYER met2 ;
        RECT 131.190 296.000 131.470 300.000 ;
    END
  END mports_o[193]
  PIN mports_o[194]
    DIRECTION OUTPUT TRISTATE ;
    USE SIGNAL ;
    ANTENNADIFFAREA 0.795200 ;
    PORT
      LAYER met2 ;
        RECT 132.110 296.000 132.390 300.000 ;
    END
  END mports_o[194]
  PIN mports_o[195]
    DIRECTION OUTPUT TRISTATE ;
    USE SIGNAL ;
    ANTENNADIFFAREA 0.795200 ;
    PORT
      LAYER met2 ;
        RECT 133.030 296.000 133.310 300.000 ;
    END
  END mports_o[195]
  PIN mports_o[196]
    DIRECTION OUTPUT TRISTATE ;
    USE SIGNAL ;
    ANTENNADIFFAREA 0.795200 ;
    PORT
      LAYER met2 ;
        RECT 133.950 296.000 134.230 300.000 ;
    END
  END mports_o[196]
  PIN mports_o[197]
    DIRECTION OUTPUT TRISTATE ;
    USE SIGNAL ;
    ANTENNADIFFAREA 0.795200 ;
    PORT
      LAYER met2 ;
        RECT 134.870 296.000 135.150 300.000 ;
    END
  END mports_o[197]
  PIN mports_o[198]
    DIRECTION OUTPUT TRISTATE ;
    USE SIGNAL ;
    ANTENNADIFFAREA 0.795200 ;
    PORT
      LAYER met2 ;
        RECT 135.790 296.000 136.070 300.000 ;
    END
  END mports_o[198]
  PIN mports_o[199]
    DIRECTION OUTPUT TRISTATE ;
    USE SIGNAL ;
    ANTENNADIFFAREA 0.795200 ;
    PORT
      LAYER met2 ;
        RECT 136.710 296.000 136.990 300.000 ;
    END
  END mports_o[199]
  PIN mports_o[19]
    DIRECTION OUTPUT TRISTATE ;
    USE SIGNAL ;
    ANTENNADIFFAREA 0.795200 ;
    PORT
      LAYER met2 ;
        RECT 317.030 296.000 317.310 300.000 ;
    END
  END mports_o[19]
  PIN mports_o[1]
    DIRECTION OUTPUT TRISTATE ;
    USE SIGNAL ;
    ANTENNADIFFAREA 0.795200 ;
    PORT
      LAYER met2 ;
        RECT 300.470 296.000 300.750 300.000 ;
    END
  END mports_o[1]
  PIN mports_o[200]
    DIRECTION OUTPUT TRISTATE ;
    USE SIGNAL ;
    ANTENNADIFFAREA 0.795200 ;
    PORT
      LAYER met2 ;
        RECT 137.630 296.000 137.910 300.000 ;
    END
  END mports_o[200]
  PIN mports_o[201]
    DIRECTION OUTPUT TRISTATE ;
    USE SIGNAL ;
    ANTENNADIFFAREA 0.795200 ;
    PORT
      LAYER met2 ;
        RECT 138.550 296.000 138.830 300.000 ;
    END
  END mports_o[201]
  PIN mports_o[202]
    DIRECTION OUTPUT TRISTATE ;
    USE SIGNAL ;
    ANTENNADIFFAREA 0.795200 ;
    PORT
      LAYER met2 ;
        RECT 139.470 296.000 139.750 300.000 ;
    END
  END mports_o[202]
  PIN mports_o[203]
    DIRECTION OUTPUT TRISTATE ;
    USE SIGNAL ;
    ANTENNADIFFAREA 0.795200 ;
    PORT
      LAYER met2 ;
        RECT 140.390 296.000 140.670 300.000 ;
    END
  END mports_o[203]
  PIN mports_o[204]
    DIRECTION OUTPUT TRISTATE ;
    USE SIGNAL ;
    ANTENNADIFFAREA 0.795200 ;
    PORT
      LAYER met3 ;
        RECT 0.000 10.920 4.000 11.520 ;
    END
  END mports_o[204]
  PIN mports_o[205]
    DIRECTION OUTPUT TRISTATE ;
    USE SIGNAL ;
    ANTENNADIFFAREA 0.795200 ;
    PORT
      LAYER met3 ;
        RECT 0.000 13.640 4.000 14.240 ;
    END
  END mports_o[205]
  PIN mports_o[206]
    DIRECTION OUTPUT TRISTATE ;
    USE SIGNAL ;
    ANTENNADIFFAREA 0.795200 ;
    PORT
      LAYER met3 ;
        RECT 0.000 16.360 4.000 16.960 ;
    END
  END mports_o[206]
  PIN mports_o[207]
    DIRECTION OUTPUT TRISTATE ;
    USE SIGNAL ;
    ANTENNADIFFAREA 0.795200 ;
    PORT
      LAYER met3 ;
        RECT 0.000 19.080 4.000 19.680 ;
    END
  END mports_o[207]
  PIN mports_o[208]
    DIRECTION OUTPUT TRISTATE ;
    USE SIGNAL ;
    ANTENNADIFFAREA 0.795200 ;
    PORT
      LAYER met3 ;
        RECT 0.000 21.800 4.000 22.400 ;
    END
  END mports_o[208]
  PIN mports_o[209]
    DIRECTION OUTPUT TRISTATE ;
    USE SIGNAL ;
    ANTENNADIFFAREA 0.795200 ;
    PORT
      LAYER met3 ;
        RECT 0.000 24.520 4.000 25.120 ;
    END
  END mports_o[209]
  PIN mports_o[20]
    DIRECTION OUTPUT TRISTATE ;
    USE SIGNAL ;
    ANTENNADIFFAREA 0.795200 ;
    PORT
      LAYER met2 ;
        RECT 317.950 296.000 318.230 300.000 ;
    END
  END mports_o[20]
  PIN mports_o[210]
    DIRECTION OUTPUT TRISTATE ;
    USE SIGNAL ;
    ANTENNADIFFAREA 0.795200 ;
    PORT
      LAYER met3 ;
        RECT 0.000 27.240 4.000 27.840 ;
    END
  END mports_o[210]
  PIN mports_o[211]
    DIRECTION OUTPUT TRISTATE ;
    USE SIGNAL ;
    ANTENNADIFFAREA 0.795200 ;
    PORT
      LAYER met3 ;
        RECT 0.000 29.960 4.000 30.560 ;
    END
  END mports_o[211]
  PIN mports_o[212]
    DIRECTION OUTPUT TRISTATE ;
    USE SIGNAL ;
    ANTENNADIFFAREA 0.795200 ;
    PORT
      LAYER met3 ;
        RECT 0.000 32.680 4.000 33.280 ;
    END
  END mports_o[212]
  PIN mports_o[213]
    DIRECTION OUTPUT TRISTATE ;
    USE SIGNAL ;
    ANTENNADIFFAREA 0.795200 ;
    PORT
      LAYER met3 ;
        RECT 0.000 35.400 4.000 36.000 ;
    END
  END mports_o[213]
  PIN mports_o[214]
    DIRECTION OUTPUT TRISTATE ;
    USE SIGNAL ;
    ANTENNADIFFAREA 0.795200 ;
    PORT
      LAYER met3 ;
        RECT 0.000 38.120 4.000 38.720 ;
    END
  END mports_o[214]
  PIN mports_o[215]
    DIRECTION OUTPUT TRISTATE ;
    USE SIGNAL ;
    ANTENNADIFFAREA 0.795200 ;
    PORT
      LAYER met3 ;
        RECT 0.000 40.840 4.000 41.440 ;
    END
  END mports_o[215]
  PIN mports_o[216]
    DIRECTION OUTPUT TRISTATE ;
    USE SIGNAL ;
    ANTENNADIFFAREA 0.795200 ;
    PORT
      LAYER met3 ;
        RECT 0.000 43.560 4.000 44.160 ;
    END
  END mports_o[216]
  PIN mports_o[217]
    DIRECTION OUTPUT TRISTATE ;
    USE SIGNAL ;
    ANTENNADIFFAREA 0.795200 ;
    PORT
      LAYER met3 ;
        RECT 0.000 46.280 4.000 46.880 ;
    END
  END mports_o[217]
  PIN mports_o[218]
    DIRECTION OUTPUT TRISTATE ;
    USE SIGNAL ;
    ANTENNADIFFAREA 0.795200 ;
    PORT
      LAYER met3 ;
        RECT 0.000 49.000 4.000 49.600 ;
    END
  END mports_o[218]
  PIN mports_o[219]
    DIRECTION OUTPUT TRISTATE ;
    USE SIGNAL ;
    ANTENNADIFFAREA 0.795200 ;
    PORT
      LAYER met3 ;
        RECT 0.000 51.720 4.000 52.320 ;
    END
  END mports_o[219]
  PIN mports_o[21]
    DIRECTION OUTPUT TRISTATE ;
    USE SIGNAL ;
    ANTENNADIFFAREA 0.795200 ;
    PORT
      LAYER met2 ;
        RECT 318.870 296.000 319.150 300.000 ;
    END
  END mports_o[21]
  PIN mports_o[220]
    DIRECTION OUTPUT TRISTATE ;
    USE SIGNAL ;
    ANTENNADIFFAREA 0.795200 ;
    PORT
      LAYER met3 ;
        RECT 0.000 54.440 4.000 55.040 ;
    END
  END mports_o[220]
  PIN mports_o[221]
    DIRECTION OUTPUT TRISTATE ;
    USE SIGNAL ;
    ANTENNADIFFAREA 0.795200 ;
    PORT
      LAYER met3 ;
        RECT 0.000 57.160 4.000 57.760 ;
    END
  END mports_o[221]
  PIN mports_o[222]
    DIRECTION OUTPUT TRISTATE ;
    USE SIGNAL ;
    ANTENNADIFFAREA 0.795200 ;
    PORT
      LAYER met3 ;
        RECT 0.000 59.880 4.000 60.480 ;
    END
  END mports_o[222]
  PIN mports_o[223]
    DIRECTION OUTPUT TRISTATE ;
    USE SIGNAL ;
    ANTENNADIFFAREA 0.795200 ;
    PORT
      LAYER met3 ;
        RECT 0.000 62.600 4.000 63.200 ;
    END
  END mports_o[223]
  PIN mports_o[224]
    DIRECTION OUTPUT TRISTATE ;
    USE SIGNAL ;
    ANTENNADIFFAREA 0.795200 ;
    PORT
      LAYER met3 ;
        RECT 0.000 65.320 4.000 65.920 ;
    END
  END mports_o[224]
  PIN mports_o[225]
    DIRECTION OUTPUT TRISTATE ;
    USE SIGNAL ;
    ANTENNADIFFAREA 0.795200 ;
    PORT
      LAYER met3 ;
        RECT 0.000 68.040 4.000 68.640 ;
    END
  END mports_o[225]
  PIN mports_o[226]
    DIRECTION OUTPUT TRISTATE ;
    USE SIGNAL ;
    ANTENNADIFFAREA 0.795200 ;
    PORT
      LAYER met3 ;
        RECT 0.000 70.760 4.000 71.360 ;
    END
  END mports_o[226]
  PIN mports_o[227]
    DIRECTION OUTPUT TRISTATE ;
    USE SIGNAL ;
    ANTENNADIFFAREA 0.795200 ;
    PORT
      LAYER met3 ;
        RECT 0.000 73.480 4.000 74.080 ;
    END
  END mports_o[227]
  PIN mports_o[228]
    DIRECTION OUTPUT TRISTATE ;
    USE SIGNAL ;
    ANTENNADIFFAREA 0.795200 ;
    PORT
      LAYER met3 ;
        RECT 0.000 76.200 4.000 76.800 ;
    END
  END mports_o[228]
  PIN mports_o[229]
    DIRECTION OUTPUT TRISTATE ;
    USE SIGNAL ;
    ANTENNADIFFAREA 0.795200 ;
    PORT
      LAYER met3 ;
        RECT 0.000 78.920 4.000 79.520 ;
    END
  END mports_o[229]
  PIN mports_o[22]
    DIRECTION OUTPUT TRISTATE ;
    USE SIGNAL ;
    ANTENNADIFFAREA 0.795200 ;
    PORT
      LAYER met2 ;
        RECT 319.790 296.000 320.070 300.000 ;
    END
  END mports_o[22]
  PIN mports_o[230]
    DIRECTION OUTPUT TRISTATE ;
    USE SIGNAL ;
    ANTENNADIFFAREA 0.795200 ;
    PORT
      LAYER met3 ;
        RECT 0.000 81.640 4.000 82.240 ;
    END
  END mports_o[230]
  PIN mports_o[231]
    DIRECTION OUTPUT TRISTATE ;
    USE SIGNAL ;
    ANTENNADIFFAREA 0.795200 ;
    PORT
      LAYER met3 ;
        RECT 0.000 84.360 4.000 84.960 ;
    END
  END mports_o[231]
  PIN mports_o[232]
    DIRECTION OUTPUT TRISTATE ;
    USE SIGNAL ;
    ANTENNADIFFAREA 0.795200 ;
    PORT
      LAYER met3 ;
        RECT 0.000 87.080 4.000 87.680 ;
    END
  END mports_o[232]
  PIN mports_o[233]
    DIRECTION OUTPUT TRISTATE ;
    USE SIGNAL ;
    ANTENNADIFFAREA 0.795200 ;
    PORT
      LAYER met3 ;
        RECT 0.000 89.800 4.000 90.400 ;
    END
  END mports_o[233]
  PIN mports_o[234]
    DIRECTION OUTPUT TRISTATE ;
    USE SIGNAL ;
    ANTENNADIFFAREA 0.795200 ;
    PORT
      LAYER met3 ;
        RECT 0.000 92.520 4.000 93.120 ;
    END
  END mports_o[234]
  PIN mports_o[235]
    DIRECTION OUTPUT TRISTATE ;
    USE SIGNAL ;
    ANTENNADIFFAREA 0.795200 ;
    PORT
      LAYER met3 ;
        RECT 0.000 95.240 4.000 95.840 ;
    END
  END mports_o[235]
  PIN mports_o[236]
    DIRECTION OUTPUT TRISTATE ;
    USE SIGNAL ;
    ANTENNADIFFAREA 0.795200 ;
    PORT
      LAYER met3 ;
        RECT 0.000 97.960 4.000 98.560 ;
    END
  END mports_o[236]
  PIN mports_o[237]
    DIRECTION OUTPUT TRISTATE ;
    USE SIGNAL ;
    ANTENNADIFFAREA 0.795200 ;
    PORT
      LAYER met3 ;
        RECT 0.000 100.680 4.000 101.280 ;
    END
  END mports_o[237]
  PIN mports_o[238]
    DIRECTION OUTPUT TRISTATE ;
    USE SIGNAL ;
    ANTENNADIFFAREA 0.795200 ;
    PORT
      LAYER met3 ;
        RECT 596.000 10.920 600.000 11.520 ;
    END
  END mports_o[238]
  PIN mports_o[239]
    DIRECTION OUTPUT TRISTATE ;
    USE SIGNAL ;
    ANTENNADIFFAREA 0.445500 ;
    PORT
      LAYER met3 ;
        RECT 596.000 12.280 600.000 12.880 ;
    END
  END mports_o[239]
  PIN mports_o[23]
    DIRECTION OUTPUT TRISTATE ;
    USE SIGNAL ;
    ANTENNADIFFAREA 0.795200 ;
    PORT
      LAYER met2 ;
        RECT 320.710 296.000 320.990 300.000 ;
    END
  END mports_o[23]
  PIN mports_o[240]
    DIRECTION OUTPUT TRISTATE ;
    USE SIGNAL ;
    ANTENNADIFFAREA 0.445500 ;
    PORT
      LAYER met3 ;
        RECT 596.000 13.640 600.000 14.240 ;
    END
  END mports_o[240]
  PIN mports_o[241]
    DIRECTION OUTPUT TRISTATE ;
    USE SIGNAL ;
    ANTENNADIFFAREA 0.795200 ;
    PORT
      LAYER met3 ;
        RECT 596.000 15.000 600.000 15.600 ;
    END
  END mports_o[241]
  PIN mports_o[242]
    DIRECTION OUTPUT TRISTATE ;
    USE SIGNAL ;
    ANTENNADIFFAREA 0.445500 ;
    PORT
      LAYER met3 ;
        RECT 596.000 16.360 600.000 16.960 ;
    END
  END mports_o[242]
  PIN mports_o[243]
    DIRECTION OUTPUT TRISTATE ;
    USE SIGNAL ;
    ANTENNADIFFAREA 0.445500 ;
    PORT
      LAYER met3 ;
        RECT 596.000 17.720 600.000 18.320 ;
    END
  END mports_o[243]
  PIN mports_o[244]
    DIRECTION OUTPUT TRISTATE ;
    USE SIGNAL ;
    ANTENNADIFFAREA 0.795200 ;
    PORT
      LAYER met3 ;
        RECT 596.000 19.080 600.000 19.680 ;
    END
  END mports_o[244]
  PIN mports_o[245]
    DIRECTION OUTPUT TRISTATE ;
    USE SIGNAL ;
    ANTENNADIFFAREA 0.795200 ;
    PORT
      LAYER met3 ;
        RECT 596.000 20.440 600.000 21.040 ;
    END
  END mports_o[245]
  PIN mports_o[246]
    DIRECTION OUTPUT TRISTATE ;
    USE SIGNAL ;
    ANTENNADIFFAREA 0.445500 ;
    PORT
      LAYER met3 ;
        RECT 596.000 21.800 600.000 22.400 ;
    END
  END mports_o[246]
  PIN mports_o[247]
    DIRECTION OUTPUT TRISTATE ;
    USE SIGNAL ;
    ANTENNADIFFAREA 0.445500 ;
    PORT
      LAYER met3 ;
        RECT 596.000 23.160 600.000 23.760 ;
    END
  END mports_o[247]
  PIN mports_o[248]
    DIRECTION OUTPUT TRISTATE ;
    USE SIGNAL ;
    ANTENNADIFFAREA 0.445500 ;
    PORT
      LAYER met3 ;
        RECT 596.000 24.520 600.000 25.120 ;
    END
  END mports_o[248]
  PIN mports_o[249]
    DIRECTION OUTPUT TRISTATE ;
    USE SIGNAL ;
    ANTENNADIFFAREA 0.795200 ;
    PORT
      LAYER met3 ;
        RECT 596.000 25.880 600.000 26.480 ;
    END
  END mports_o[249]
  PIN mports_o[24]
    DIRECTION OUTPUT TRISTATE ;
    USE SIGNAL ;
    ANTENNADIFFAREA 0.795200 ;
    PORT
      LAYER met2 ;
        RECT 321.630 296.000 321.910 300.000 ;
    END
  END mports_o[24]
  PIN mports_o[250]
    DIRECTION OUTPUT TRISTATE ;
    USE SIGNAL ;
    ANTENNADIFFAREA 0.795200 ;
    PORT
      LAYER met3 ;
        RECT 596.000 27.240 600.000 27.840 ;
    END
  END mports_o[250]
  PIN mports_o[251]
    DIRECTION OUTPUT TRISTATE ;
    USE SIGNAL ;
    ANTENNADIFFAREA 0.795200 ;
    PORT
      LAYER met3 ;
        RECT 596.000 28.600 600.000 29.200 ;
    END
  END mports_o[251]
  PIN mports_o[252]
    DIRECTION OUTPUT TRISTATE ;
    USE SIGNAL ;
    ANTENNADIFFAREA 0.445500 ;
    PORT
      LAYER met3 ;
        RECT 596.000 29.960 600.000 30.560 ;
    END
  END mports_o[252]
  PIN mports_o[253]
    DIRECTION OUTPUT TRISTATE ;
    USE SIGNAL ;
    ANTENNADIFFAREA 0.445500 ;
    PORT
      LAYER met3 ;
        RECT 596.000 31.320 600.000 31.920 ;
    END
  END mports_o[253]
  PIN mports_o[254]
    DIRECTION OUTPUT TRISTATE ;
    USE SIGNAL ;
    ANTENNADIFFAREA 0.445500 ;
    PORT
      LAYER met3 ;
        RECT 596.000 32.680 600.000 33.280 ;
    END
  END mports_o[254]
  PIN mports_o[255]
    DIRECTION OUTPUT TRISTATE ;
    USE SIGNAL ;
    ANTENNADIFFAREA 0.795200 ;
    PORT
      LAYER met3 ;
        RECT 596.000 34.040 600.000 34.640 ;
    END
  END mports_o[255]
  PIN mports_o[256]
    DIRECTION OUTPUT TRISTATE ;
    USE SIGNAL ;
    ANTENNADIFFAREA 0.445500 ;
    PORT
      LAYER met3 ;
        RECT 596.000 35.400 600.000 36.000 ;
    END
  END mports_o[256]
  PIN mports_o[257]
    DIRECTION OUTPUT TRISTATE ;
    USE SIGNAL ;
    ANTENNADIFFAREA 0.445500 ;
    PORT
      LAYER met3 ;
        RECT 596.000 36.760 600.000 37.360 ;
    END
  END mports_o[257]
  PIN mports_o[258]
    DIRECTION OUTPUT TRISTATE ;
    USE SIGNAL ;
    ANTENNADIFFAREA 0.445500 ;
    PORT
      LAYER met3 ;
        RECT 596.000 38.120 600.000 38.720 ;
    END
  END mports_o[258]
  PIN mports_o[259]
    DIRECTION OUTPUT TRISTATE ;
    USE SIGNAL ;
    ANTENNADIFFAREA 0.445500 ;
    PORT
      LAYER met3 ;
        RECT 596.000 39.480 600.000 40.080 ;
    END
  END mports_o[259]
  PIN mports_o[25]
    DIRECTION OUTPUT TRISTATE ;
    USE SIGNAL ;
    ANTENNADIFFAREA 0.795200 ;
    PORT
      LAYER met2 ;
        RECT 322.550 296.000 322.830 300.000 ;
    END
  END mports_o[25]
  PIN mports_o[260]
    DIRECTION OUTPUT TRISTATE ;
    USE SIGNAL ;
    ANTENNADIFFAREA 0.795200 ;
    PORT
      LAYER met3 ;
        RECT 596.000 40.840 600.000 41.440 ;
    END
  END mports_o[260]
  PIN mports_o[261]
    DIRECTION OUTPUT TRISTATE ;
    USE SIGNAL ;
    ANTENNADIFFAREA 0.795200 ;
    PORT
      LAYER met3 ;
        RECT 596.000 42.200 600.000 42.800 ;
    END
  END mports_o[261]
  PIN mports_o[262]
    DIRECTION OUTPUT TRISTATE ;
    USE SIGNAL ;
    ANTENNADIFFAREA 0.445500 ;
    PORT
      LAYER met3 ;
        RECT 596.000 43.560 600.000 44.160 ;
    END
  END mports_o[262]
  PIN mports_o[263]
    DIRECTION OUTPUT TRISTATE ;
    USE SIGNAL ;
    ANTENNADIFFAREA 0.445500 ;
    PORT
      LAYER met3 ;
        RECT 596.000 44.920 600.000 45.520 ;
    END
  END mports_o[263]
  PIN mports_o[264]
    DIRECTION OUTPUT TRISTATE ;
    USE SIGNAL ;
    ANTENNADIFFAREA 0.445500 ;
    PORT
      LAYER met3 ;
        RECT 596.000 46.280 600.000 46.880 ;
    END
  END mports_o[264]
  PIN mports_o[265]
    DIRECTION OUTPUT TRISTATE ;
    USE SIGNAL ;
    ANTENNADIFFAREA 0.795200 ;
    PORT
      LAYER met3 ;
        RECT 596.000 47.640 600.000 48.240 ;
    END
  END mports_o[265]
  PIN mports_o[266]
    DIRECTION OUTPUT TRISTATE ;
    USE SIGNAL ;
    ANTENNADIFFAREA 0.445500 ;
    PORT
      LAYER met3 ;
        RECT 596.000 49.000 600.000 49.600 ;
    END
  END mports_o[266]
  PIN mports_o[267]
    DIRECTION OUTPUT TRISTATE ;
    USE SIGNAL ;
    ANTENNADIFFAREA 0.795200 ;
    PORT
      LAYER met3 ;
        RECT 596.000 50.360 600.000 50.960 ;
    END
  END mports_o[267]
  PIN mports_o[268]
    DIRECTION OUTPUT TRISTATE ;
    USE SIGNAL ;
    ANTENNADIFFAREA 0.445500 ;
    PORT
      LAYER met3 ;
        RECT 596.000 51.720 600.000 52.320 ;
    END
  END mports_o[268]
  PIN mports_o[269]
    DIRECTION OUTPUT TRISTATE ;
    USE SIGNAL ;
    ANTENNADIFFAREA 0.445500 ;
    PORT
      LAYER met3 ;
        RECT 596.000 53.080 600.000 53.680 ;
    END
  END mports_o[269]
  PIN mports_o[26]
    DIRECTION OUTPUT TRISTATE ;
    USE SIGNAL ;
    ANTENNADIFFAREA 0.795200 ;
    PORT
      LAYER met2 ;
        RECT 323.470 296.000 323.750 300.000 ;
    END
  END mports_o[26]
  PIN mports_o[270]
    DIRECTION OUTPUT TRISTATE ;
    USE SIGNAL ;
    ANTENNADIFFAREA 0.795200 ;
    PORT
      LAYER met3 ;
        RECT 596.000 54.440 600.000 55.040 ;
    END
  END mports_o[270]
  PIN mports_o[271]
    DIRECTION OUTPUT TRISTATE ;
    USE SIGNAL ;
    ANTENNADIFFAREA 0.795200 ;
    PORT
      LAYER met3 ;
        RECT 596.000 55.800 600.000 56.400 ;
    END
  END mports_o[271]
  PIN mports_o[27]
    DIRECTION OUTPUT TRISTATE ;
    USE SIGNAL ;
    ANTENNADIFFAREA 0.795200 ;
    PORT
      LAYER met2 ;
        RECT 324.390 296.000 324.670 300.000 ;
    END
  END mports_o[27]
  PIN mports_o[28]
    DIRECTION OUTPUT TRISTATE ;
    USE SIGNAL ;
    ANTENNADIFFAREA 0.795200 ;
    PORT
      LAYER met2 ;
        RECT 325.310 296.000 325.590 300.000 ;
    END
  END mports_o[28]
  PIN mports_o[29]
    DIRECTION OUTPUT TRISTATE ;
    USE SIGNAL ;
    ANTENNADIFFAREA 0.795200 ;
    PORT
      LAYER met2 ;
        RECT 326.230 296.000 326.510 300.000 ;
    END
  END mports_o[29]
  PIN mports_o[2]
    DIRECTION OUTPUT TRISTATE ;
    USE SIGNAL ;
    ANTENNADIFFAREA 0.795200 ;
    PORT
      LAYER met2 ;
        RECT 301.390 296.000 301.670 300.000 ;
    END
  END mports_o[2]
  PIN mports_o[30]
    DIRECTION OUTPUT TRISTATE ;
    USE SIGNAL ;
    ANTENNADIFFAREA 0.795200 ;
    PORT
      LAYER met2 ;
        RECT 327.150 296.000 327.430 300.000 ;
    END
  END mports_o[30]
  PIN mports_o[31]
    DIRECTION OUTPUT TRISTATE ;
    USE SIGNAL ;
    ANTENNADIFFAREA 0.795200 ;
    PORT
      LAYER met2 ;
        RECT 328.070 296.000 328.350 300.000 ;
    END
  END mports_o[31]
  PIN mports_o[32]
    DIRECTION OUTPUT TRISTATE ;
    USE SIGNAL ;
    ANTENNADIFFAREA 0.795200 ;
    PORT
      LAYER met2 ;
        RECT 328.990 296.000 329.270 300.000 ;
    END
  END mports_o[32]
  PIN mports_o[33]
    DIRECTION OUTPUT TRISTATE ;
    USE SIGNAL ;
    ANTENNADIFFAREA 0.795200 ;
    PORT
      LAYER met2 ;
        RECT 329.910 296.000 330.190 300.000 ;
    END
  END mports_o[33]
  PIN mports_o[34]
    DIRECTION OUTPUT TRISTATE ;
    USE SIGNAL ;
    ANTENNADIFFAREA 0.795200 ;
    PORT
      LAYER met2 ;
        RECT 204.790 296.000 205.070 300.000 ;
    END
  END mports_o[34]
  PIN mports_o[35]
    DIRECTION OUTPUT TRISTATE ;
    USE SIGNAL ;
    ANTENNADIFFAREA 0.795200 ;
    PORT
      LAYER met2 ;
        RECT 205.710 296.000 205.990 300.000 ;
    END
  END mports_o[35]
  PIN mports_o[36]
    DIRECTION OUTPUT TRISTATE ;
    USE SIGNAL ;
    ANTENNADIFFAREA 0.795200 ;
    PORT
      LAYER met2 ;
        RECT 206.630 296.000 206.910 300.000 ;
    END
  END mports_o[36]
  PIN mports_o[37]
    DIRECTION OUTPUT TRISTATE ;
    USE SIGNAL ;
    ANTENNADIFFAREA 0.795200 ;
    PORT
      LAYER met2 ;
        RECT 207.550 296.000 207.830 300.000 ;
    END
  END mports_o[37]
  PIN mports_o[38]
    DIRECTION OUTPUT TRISTATE ;
    USE SIGNAL ;
    ANTENNADIFFAREA 0.795200 ;
    PORT
      LAYER met2 ;
        RECT 208.470 296.000 208.750 300.000 ;
    END
  END mports_o[38]
  PIN mports_o[39]
    DIRECTION OUTPUT TRISTATE ;
    USE SIGNAL ;
    ANTENNADIFFAREA 0.795200 ;
    PORT
      LAYER met2 ;
        RECT 209.390 296.000 209.670 300.000 ;
    END
  END mports_o[39]
  PIN mports_o[3]
    DIRECTION OUTPUT TRISTATE ;
    USE SIGNAL ;
    ANTENNADIFFAREA 0.795200 ;
    PORT
      LAYER met2 ;
        RECT 302.310 296.000 302.590 300.000 ;
    END
  END mports_o[3]
  PIN mports_o[40]
    DIRECTION OUTPUT TRISTATE ;
    USE SIGNAL ;
    ANTENNADIFFAREA 0.795200 ;
    PORT
      LAYER met2 ;
        RECT 210.310 296.000 210.590 300.000 ;
    END
  END mports_o[40]
  PIN mports_o[41]
    DIRECTION OUTPUT TRISTATE ;
    USE SIGNAL ;
    ANTENNADIFFAREA 0.795200 ;
    PORT
      LAYER met2 ;
        RECT 211.230 296.000 211.510 300.000 ;
    END
  END mports_o[41]
  PIN mports_o[42]
    DIRECTION OUTPUT TRISTATE ;
    USE SIGNAL ;
    ANTENNADIFFAREA 0.795200 ;
    PORT
      LAYER met2 ;
        RECT 212.150 296.000 212.430 300.000 ;
    END
  END mports_o[42]
  PIN mports_o[43]
    DIRECTION OUTPUT TRISTATE ;
    USE SIGNAL ;
    ANTENNADIFFAREA 0.795200 ;
    PORT
      LAYER met2 ;
        RECT 213.070 296.000 213.350 300.000 ;
    END
  END mports_o[43]
  PIN mports_o[44]
    DIRECTION OUTPUT TRISTATE ;
    USE SIGNAL ;
    ANTENNADIFFAREA 0.795200 ;
    PORT
      LAYER met2 ;
        RECT 213.990 296.000 214.270 300.000 ;
    END
  END mports_o[44]
  PIN mports_o[45]
    DIRECTION OUTPUT TRISTATE ;
    USE SIGNAL ;
    ANTENNADIFFAREA 0.795200 ;
    PORT
      LAYER met2 ;
        RECT 214.910 296.000 215.190 300.000 ;
    END
  END mports_o[45]
  PIN mports_o[46]
    DIRECTION OUTPUT TRISTATE ;
    USE SIGNAL ;
    ANTENNADIFFAREA 0.795200 ;
    PORT
      LAYER met2 ;
        RECT 215.830 296.000 216.110 300.000 ;
    END
  END mports_o[46]
  PIN mports_o[47]
    DIRECTION OUTPUT TRISTATE ;
    USE SIGNAL ;
    ANTENNADIFFAREA 0.795200 ;
    PORT
      LAYER met2 ;
        RECT 216.750 296.000 217.030 300.000 ;
    END
  END mports_o[47]
  PIN mports_o[48]
    DIRECTION OUTPUT TRISTATE ;
    USE SIGNAL ;
    ANTENNADIFFAREA 0.795200 ;
    PORT
      LAYER met2 ;
        RECT 217.670 296.000 217.950 300.000 ;
    END
  END mports_o[48]
  PIN mports_o[49]
    DIRECTION OUTPUT TRISTATE ;
    USE SIGNAL ;
    ANTENNADIFFAREA 0.795200 ;
    PORT
      LAYER met2 ;
        RECT 218.590 296.000 218.870 300.000 ;
    END
  END mports_o[49]
  PIN mports_o[4]
    DIRECTION OUTPUT TRISTATE ;
    USE SIGNAL ;
    ANTENNADIFFAREA 0.795200 ;
    PORT
      LAYER met2 ;
        RECT 303.230 296.000 303.510 300.000 ;
    END
  END mports_o[4]
  PIN mports_o[50]
    DIRECTION OUTPUT TRISTATE ;
    USE SIGNAL ;
    ANTENNADIFFAREA 0.795200 ;
    PORT
      LAYER met2 ;
        RECT 219.510 296.000 219.790 300.000 ;
    END
  END mports_o[50]
  PIN mports_o[51]
    DIRECTION OUTPUT TRISTATE ;
    USE SIGNAL ;
    ANTENNADIFFAREA 0.795200 ;
    PORT
      LAYER met2 ;
        RECT 220.430 296.000 220.710 300.000 ;
    END
  END mports_o[51]
  PIN mports_o[52]
    DIRECTION OUTPUT TRISTATE ;
    USE SIGNAL ;
    ANTENNADIFFAREA 0.795200 ;
    PORT
      LAYER met2 ;
        RECT 221.350 296.000 221.630 300.000 ;
    END
  END mports_o[52]
  PIN mports_o[53]
    DIRECTION OUTPUT TRISTATE ;
    USE SIGNAL ;
    ANTENNADIFFAREA 0.795200 ;
    PORT
      LAYER met2 ;
        RECT 222.270 296.000 222.550 300.000 ;
    END
  END mports_o[53]
  PIN mports_o[54]
    DIRECTION OUTPUT TRISTATE ;
    USE SIGNAL ;
    ANTENNADIFFAREA 0.795200 ;
    PORT
      LAYER met2 ;
        RECT 223.190 296.000 223.470 300.000 ;
    END
  END mports_o[54]
  PIN mports_o[55]
    DIRECTION OUTPUT TRISTATE ;
    USE SIGNAL ;
    ANTENNADIFFAREA 0.795200 ;
    PORT
      LAYER met2 ;
        RECT 224.110 296.000 224.390 300.000 ;
    END
  END mports_o[55]
  PIN mports_o[56]
    DIRECTION OUTPUT TRISTATE ;
    USE SIGNAL ;
    ANTENNADIFFAREA 0.795200 ;
    PORT
      LAYER met2 ;
        RECT 225.030 296.000 225.310 300.000 ;
    END
  END mports_o[56]
  PIN mports_o[57]
    DIRECTION OUTPUT TRISTATE ;
    USE SIGNAL ;
    ANTENNADIFFAREA 0.795200 ;
    PORT
      LAYER met2 ;
        RECT 225.950 296.000 226.230 300.000 ;
    END
  END mports_o[57]
  PIN mports_o[58]
    DIRECTION OUTPUT TRISTATE ;
    USE SIGNAL ;
    ANTENNADIFFAREA 0.795200 ;
    PORT
      LAYER met2 ;
        RECT 226.870 296.000 227.150 300.000 ;
    END
  END mports_o[58]
  PIN mports_o[59]
    DIRECTION OUTPUT TRISTATE ;
    USE SIGNAL ;
    ANTENNADIFFAREA 0.795200 ;
    PORT
      LAYER met2 ;
        RECT 227.790 296.000 228.070 300.000 ;
    END
  END mports_o[59]
  PIN mports_o[5]
    DIRECTION OUTPUT TRISTATE ;
    USE SIGNAL ;
    ANTENNADIFFAREA 0.795200 ;
    PORT
      LAYER met2 ;
        RECT 304.150 296.000 304.430 300.000 ;
    END
  END mports_o[5]
  PIN mports_o[60]
    DIRECTION OUTPUT TRISTATE ;
    USE SIGNAL ;
    ANTENNADIFFAREA 0.795200 ;
    PORT
      LAYER met2 ;
        RECT 228.710 296.000 228.990 300.000 ;
    END
  END mports_o[60]
  PIN mports_o[61]
    DIRECTION OUTPUT TRISTATE ;
    USE SIGNAL ;
    ANTENNADIFFAREA 0.795200 ;
    PORT
      LAYER met2 ;
        RECT 229.630 296.000 229.910 300.000 ;
    END
  END mports_o[61]
  PIN mports_o[62]
    DIRECTION OUTPUT TRISTATE ;
    USE SIGNAL ;
    ANTENNADIFFAREA 0.795200 ;
    PORT
      LAYER met2 ;
        RECT 230.550 296.000 230.830 300.000 ;
    END
  END mports_o[62]
  PIN mports_o[63]
    DIRECTION OUTPUT TRISTATE ;
    USE SIGNAL ;
    ANTENNADIFFAREA 0.795200 ;
    PORT
      LAYER met2 ;
        RECT 231.470 296.000 231.750 300.000 ;
    END
  END mports_o[63]
  PIN mports_o[64]
    DIRECTION OUTPUT TRISTATE ;
    USE SIGNAL ;
    ANTENNADIFFAREA 0.795200 ;
    PORT
      LAYER met2 ;
        RECT 232.390 296.000 232.670 300.000 ;
    END
  END mports_o[64]
  PIN mports_o[65]
    DIRECTION OUTPUT TRISTATE ;
    USE SIGNAL ;
    ANTENNADIFFAREA 0.795200 ;
    PORT
      LAYER met2 ;
        RECT 233.310 296.000 233.590 300.000 ;
    END
  END mports_o[65]
  PIN mports_o[66]
    DIRECTION OUTPUT TRISTATE ;
    USE SIGNAL ;
    ANTENNADIFFAREA 0.795200 ;
    PORT
      LAYER met2 ;
        RECT 234.230 296.000 234.510 300.000 ;
    END
  END mports_o[66]
  PIN mports_o[67]
    DIRECTION OUTPUT TRISTATE ;
    USE SIGNAL ;
    ANTENNADIFFAREA 0.795200 ;
    PORT
      LAYER met2 ;
        RECT 235.150 296.000 235.430 300.000 ;
    END
  END mports_o[67]
  PIN mports_o[68]
    DIRECTION OUTPUT TRISTATE ;
    USE SIGNAL ;
    ANTENNADIFFAREA 0.795200 ;
    PORT
      LAYER met2 ;
        RECT 19.410 0.000 19.690 4.000 ;
    END
  END mports_o[68]
  PIN mports_o[69]
    DIRECTION OUTPUT TRISTATE ;
    USE SIGNAL ;
    ANTENNADIFFAREA 0.795200 ;
    PORT
      LAYER met2 ;
        RECT 22.170 0.000 22.450 4.000 ;
    END
  END mports_o[69]
  PIN mports_o[6]
    DIRECTION OUTPUT TRISTATE ;
    USE SIGNAL ;
    ANTENNADIFFAREA 0.795200 ;
    PORT
      LAYER met2 ;
        RECT 305.070 296.000 305.350 300.000 ;
    END
  END mports_o[6]
  PIN mports_o[70]
    DIRECTION OUTPUT TRISTATE ;
    USE SIGNAL ;
    ANTENNADIFFAREA 0.795200 ;
    PORT
      LAYER met2 ;
        RECT 24.930 0.000 25.210 4.000 ;
    END
  END mports_o[70]
  PIN mports_o[71]
    DIRECTION OUTPUT TRISTATE ;
    USE SIGNAL ;
    ANTENNADIFFAREA 0.795200 ;
    PORT
      LAYER met2 ;
        RECT 27.690 0.000 27.970 4.000 ;
    END
  END mports_o[71]
  PIN mports_o[72]
    DIRECTION OUTPUT TRISTATE ;
    USE SIGNAL ;
    ANTENNADIFFAREA 0.795200 ;
    PORT
      LAYER met2 ;
        RECT 30.450 0.000 30.730 4.000 ;
    END
  END mports_o[72]
  PIN mports_o[73]
    DIRECTION OUTPUT TRISTATE ;
    USE SIGNAL ;
    ANTENNADIFFAREA 0.795200 ;
    PORT
      LAYER met2 ;
        RECT 33.210 0.000 33.490 4.000 ;
    END
  END mports_o[73]
  PIN mports_o[74]
    DIRECTION OUTPUT TRISTATE ;
    USE SIGNAL ;
    ANTENNADIFFAREA 0.795200 ;
    PORT
      LAYER met2 ;
        RECT 35.970 0.000 36.250 4.000 ;
    END
  END mports_o[74]
  PIN mports_o[75]
    DIRECTION OUTPUT TRISTATE ;
    USE SIGNAL ;
    ANTENNADIFFAREA 0.795200 ;
    PORT
      LAYER met2 ;
        RECT 38.730 0.000 39.010 4.000 ;
    END
  END mports_o[75]
  PIN mports_o[76]
    DIRECTION OUTPUT TRISTATE ;
    USE SIGNAL ;
    ANTENNADIFFAREA 0.795200 ;
    PORT
      LAYER met2 ;
        RECT 41.490 0.000 41.770 4.000 ;
    END
  END mports_o[76]
  PIN mports_o[77]
    DIRECTION OUTPUT TRISTATE ;
    USE SIGNAL ;
    ANTENNADIFFAREA 0.795200 ;
    PORT
      LAYER met2 ;
        RECT 44.250 0.000 44.530 4.000 ;
    END
  END mports_o[77]
  PIN mports_o[78]
    DIRECTION OUTPUT TRISTATE ;
    USE SIGNAL ;
    ANTENNADIFFAREA 0.795200 ;
    PORT
      LAYER met2 ;
        RECT 47.010 0.000 47.290 4.000 ;
    END
  END mports_o[78]
  PIN mports_o[79]
    DIRECTION OUTPUT TRISTATE ;
    USE SIGNAL ;
    ANTENNADIFFAREA 0.795200 ;
    PORT
      LAYER met2 ;
        RECT 49.770 0.000 50.050 4.000 ;
    END
  END mports_o[79]
  PIN mports_o[7]
    DIRECTION OUTPUT TRISTATE ;
    USE SIGNAL ;
    ANTENNADIFFAREA 0.795200 ;
    PORT
      LAYER met2 ;
        RECT 305.990 296.000 306.270 300.000 ;
    END
  END mports_o[7]
  PIN mports_o[80]
    DIRECTION OUTPUT TRISTATE ;
    USE SIGNAL ;
    ANTENNADIFFAREA 0.795200 ;
    PORT
      LAYER met2 ;
        RECT 52.530 0.000 52.810 4.000 ;
    END
  END mports_o[80]
  PIN mports_o[81]
    DIRECTION OUTPUT TRISTATE ;
    USE SIGNAL ;
    ANTENNADIFFAREA 0.795200 ;
    PORT
      LAYER met2 ;
        RECT 55.290 0.000 55.570 4.000 ;
    END
  END mports_o[81]
  PIN mports_o[82]
    DIRECTION OUTPUT TRISTATE ;
    USE SIGNAL ;
    ANTENNADIFFAREA 0.795200 ;
    PORT
      LAYER met2 ;
        RECT 58.050 0.000 58.330 4.000 ;
    END
  END mports_o[82]
  PIN mports_o[83]
    DIRECTION OUTPUT TRISTATE ;
    USE SIGNAL ;
    ANTENNADIFFAREA 0.795200 ;
    PORT
      LAYER met2 ;
        RECT 60.810 0.000 61.090 4.000 ;
    END
  END mports_o[83]
  PIN mports_o[84]
    DIRECTION OUTPUT TRISTATE ;
    USE SIGNAL ;
    ANTENNADIFFAREA 0.795200 ;
    PORT
      LAYER met2 ;
        RECT 63.570 0.000 63.850 4.000 ;
    END
  END mports_o[84]
  PIN mports_o[85]
    DIRECTION OUTPUT TRISTATE ;
    USE SIGNAL ;
    ANTENNADIFFAREA 0.795200 ;
    PORT
      LAYER met2 ;
        RECT 66.330 0.000 66.610 4.000 ;
    END
  END mports_o[85]
  PIN mports_o[86]
    DIRECTION OUTPUT TRISTATE ;
    USE SIGNAL ;
    ANTENNADIFFAREA 0.795200 ;
    PORT
      LAYER met2 ;
        RECT 69.090 0.000 69.370 4.000 ;
    END
  END mports_o[86]
  PIN mports_o[87]
    DIRECTION OUTPUT TRISTATE ;
    USE SIGNAL ;
    ANTENNADIFFAREA 0.795200 ;
    PORT
      LAYER met2 ;
        RECT 71.850 0.000 72.130 4.000 ;
    END
  END mports_o[87]
  PIN mports_o[88]
    DIRECTION OUTPUT TRISTATE ;
    USE SIGNAL ;
    ANTENNADIFFAREA 0.795200 ;
    PORT
      LAYER met2 ;
        RECT 74.610 0.000 74.890 4.000 ;
    END
  END mports_o[88]
  PIN mports_o[89]
    DIRECTION OUTPUT TRISTATE ;
    USE SIGNAL ;
    ANTENNADIFFAREA 0.795200 ;
    PORT
      LAYER met2 ;
        RECT 77.370 0.000 77.650 4.000 ;
    END
  END mports_o[89]
  PIN mports_o[8]
    DIRECTION OUTPUT TRISTATE ;
    USE SIGNAL ;
    ANTENNADIFFAREA 0.795200 ;
    PORT
      LAYER met2 ;
        RECT 306.910 296.000 307.190 300.000 ;
    END
  END mports_o[8]
  PIN mports_o[90]
    DIRECTION OUTPUT TRISTATE ;
    USE SIGNAL ;
    ANTENNADIFFAREA 0.795200 ;
    PORT
      LAYER met2 ;
        RECT 80.130 0.000 80.410 4.000 ;
    END
  END mports_o[90]
  PIN mports_o[91]
    DIRECTION OUTPUT TRISTATE ;
    USE SIGNAL ;
    ANTENNADIFFAREA 0.795200 ;
    PORT
      LAYER met2 ;
        RECT 82.890 0.000 83.170 4.000 ;
    END
  END mports_o[91]
  PIN mports_o[92]
    DIRECTION OUTPUT TRISTATE ;
    USE SIGNAL ;
    ANTENNADIFFAREA 0.795200 ;
    PORT
      LAYER met2 ;
        RECT 85.650 0.000 85.930 4.000 ;
    END
  END mports_o[92]
  PIN mports_o[93]
    DIRECTION OUTPUT TRISTATE ;
    USE SIGNAL ;
    ANTENNADIFFAREA 0.795200 ;
    PORT
      LAYER met2 ;
        RECT 88.410 0.000 88.690 4.000 ;
    END
  END mports_o[93]
  PIN mports_o[94]
    DIRECTION OUTPUT TRISTATE ;
    USE SIGNAL ;
    ANTENNADIFFAREA 0.795200 ;
    PORT
      LAYER met2 ;
        RECT 91.170 0.000 91.450 4.000 ;
    END
  END mports_o[94]
  PIN mports_o[95]
    DIRECTION OUTPUT TRISTATE ;
    USE SIGNAL ;
    ANTENNADIFFAREA 0.795200 ;
    PORT
      LAYER met2 ;
        RECT 93.930 0.000 94.210 4.000 ;
    END
  END mports_o[95]
  PIN mports_o[96]
    DIRECTION OUTPUT TRISTATE ;
    USE SIGNAL ;
    ANTENNADIFFAREA 0.795200 ;
    PORT
      LAYER met2 ;
        RECT 96.690 0.000 96.970 4.000 ;
    END
  END mports_o[96]
  PIN mports_o[97]
    DIRECTION OUTPUT TRISTATE ;
    USE SIGNAL ;
    ANTENNADIFFAREA 0.795200 ;
    PORT
      LAYER met2 ;
        RECT 99.450 0.000 99.730 4.000 ;
    END
  END mports_o[97]
  PIN mports_o[98]
    DIRECTION OUTPUT TRISTATE ;
    USE SIGNAL ;
    ANTENNADIFFAREA 0.795200 ;
    PORT
      LAYER met2 ;
        RECT 102.210 0.000 102.490 4.000 ;
    END
  END mports_o[98]
  PIN mports_o[99]
    DIRECTION OUTPUT TRISTATE ;
    USE SIGNAL ;
    ANTENNADIFFAREA 0.795200 ;
    PORT
      LAYER met2 ;
        RECT 104.970 0.000 105.250 4.000 ;
    END
  END mports_o[99]
  PIN mports_o[9]
    DIRECTION OUTPUT TRISTATE ;
    USE SIGNAL ;
    ANTENNADIFFAREA 0.795200 ;
    PORT
      LAYER met2 ;
        RECT 307.830 296.000 308.110 300.000 ;
    END
  END mports_o[9]
  PIN nrst_i
    DIRECTION INPUT ;
    USE SIGNAL ;
    ANTENNAGATEAREA 0.159000 ;
    PORT
      LAYER met2 ;
        RECT 16.650 0.000 16.930 4.000 ;
    END
  END nrst_i
  PIN sports_i[0]
    DIRECTION INPUT ;
    USE SIGNAL ;
    ANTENNAGATEAREA 0.196500 ;
    PORT
      LAYER met3 ;
        RECT 596.000 151.000 600.000 151.600 ;
    END
  END sports_i[0]
  PIN sports_i[100]
    DIRECTION INPUT ;
    USE SIGNAL ;
    ANTENNAGATEAREA 0.247500 ;
    PORT
      LAYER met3 ;
        RECT 596.000 287.000 600.000 287.600 ;
    END
  END sports_i[100]
  PIN sports_i[101]
    DIRECTION INPUT ;
    USE SIGNAL ;
    ANTENNAGATEAREA 0.213000 ;
    PORT
      LAYER met3 ;
        RECT 596.000 288.360 600.000 288.960 ;
    END
  END sports_i[101]
  PIN sports_i[10]
    DIRECTION INPUT ;
    USE SIGNAL ;
    ANTENNAGATEAREA 0.196500 ;
    PORT
      LAYER met3 ;
        RECT 596.000 164.600 600.000 165.200 ;
    END
  END sports_i[10]
  PIN sports_i[11]
    DIRECTION INPUT ;
    USE SIGNAL ;
    ANTENNAGATEAREA 0.196500 ;
    PORT
      LAYER met3 ;
        RECT 596.000 165.960 600.000 166.560 ;
    END
  END sports_i[11]
  PIN sports_i[12]
    DIRECTION INPUT ;
    USE SIGNAL ;
    ANTENNAGATEAREA 0.196500 ;
    PORT
      LAYER met3 ;
        RECT 596.000 167.320 600.000 167.920 ;
    END
  END sports_i[12]
  PIN sports_i[13]
    DIRECTION INPUT ;
    USE SIGNAL ;
    ANTENNAGATEAREA 0.196500 ;
    PORT
      LAYER met3 ;
        RECT 596.000 168.680 600.000 169.280 ;
    END
  END sports_i[13]
  PIN sports_i[14]
    DIRECTION INPUT ;
    USE SIGNAL ;
    ANTENNAGATEAREA 0.196500 ;
    PORT
      LAYER met3 ;
        RECT 596.000 170.040 600.000 170.640 ;
    END
  END sports_i[14]
  PIN sports_i[15]
    DIRECTION INPUT ;
    USE SIGNAL ;
    ANTENNAGATEAREA 0.196500 ;
    PORT
      LAYER met3 ;
        RECT 596.000 171.400 600.000 172.000 ;
    END
  END sports_i[15]
  PIN sports_i[16]
    DIRECTION INPUT ;
    USE SIGNAL ;
    ANTENNAGATEAREA 0.196500 ;
    PORT
      LAYER met3 ;
        RECT 596.000 172.760 600.000 173.360 ;
    END
  END sports_i[16]
  PIN sports_i[17]
    DIRECTION INPUT ;
    USE SIGNAL ;
    ANTENNAGATEAREA 0.196500 ;
    PORT
      LAYER met3 ;
        RECT 596.000 174.120 600.000 174.720 ;
    END
  END sports_i[17]
  PIN sports_i[18]
    DIRECTION INPUT ;
    USE SIGNAL ;
    ANTENNAGATEAREA 0.196500 ;
    PORT
      LAYER met3 ;
        RECT 596.000 175.480 600.000 176.080 ;
    END
  END sports_i[18]
  PIN sports_i[19]
    DIRECTION INPUT ;
    USE SIGNAL ;
    ANTENNAGATEAREA 0.196500 ;
    PORT
      LAYER met3 ;
        RECT 596.000 176.840 600.000 177.440 ;
    END
  END sports_i[19]
  PIN sports_i[1]
    DIRECTION INPUT ;
    USE SIGNAL ;
    ANTENNAGATEAREA 0.196500 ;
    PORT
      LAYER met3 ;
        RECT 596.000 152.360 600.000 152.960 ;
    END
  END sports_i[1]
  PIN sports_i[20]
    DIRECTION INPUT ;
    USE SIGNAL ;
    ANTENNAGATEAREA 0.196500 ;
    PORT
      LAYER met3 ;
        RECT 596.000 178.200 600.000 178.800 ;
    END
  END sports_i[20]
  PIN sports_i[21]
    DIRECTION INPUT ;
    USE SIGNAL ;
    ANTENNAGATEAREA 0.196500 ;
    PORT
      LAYER met3 ;
        RECT 596.000 179.560 600.000 180.160 ;
    END
  END sports_i[21]
  PIN sports_i[22]
    DIRECTION INPUT ;
    USE SIGNAL ;
    ANTENNAGATEAREA 0.196500 ;
    PORT
      LAYER met3 ;
        RECT 596.000 180.920 600.000 181.520 ;
    END
  END sports_i[22]
  PIN sports_i[23]
    DIRECTION INPUT ;
    USE SIGNAL ;
    ANTENNAGATEAREA 0.196500 ;
    PORT
      LAYER met3 ;
        RECT 596.000 182.280 600.000 182.880 ;
    END
  END sports_i[23]
  PIN sports_i[24]
    DIRECTION INPUT ;
    USE SIGNAL ;
    ANTENNAGATEAREA 0.196500 ;
    PORT
      LAYER met3 ;
        RECT 596.000 183.640 600.000 184.240 ;
    END
  END sports_i[24]
  PIN sports_i[25]
    DIRECTION INPUT ;
    USE SIGNAL ;
    ANTENNAGATEAREA 0.196500 ;
    PORT
      LAYER met3 ;
        RECT 596.000 185.000 600.000 185.600 ;
    END
  END sports_i[25]
  PIN sports_i[26]
    DIRECTION INPUT ;
    USE SIGNAL ;
    ANTENNAGATEAREA 0.196500 ;
    PORT
      LAYER met3 ;
        RECT 596.000 186.360 600.000 186.960 ;
    END
  END sports_i[26]
  PIN sports_i[27]
    DIRECTION INPUT ;
    USE SIGNAL ;
    ANTENNAGATEAREA 0.126000 ;
    PORT
      LAYER met3 ;
        RECT 596.000 187.720 600.000 188.320 ;
    END
  END sports_i[27]
  PIN sports_i[28]
    DIRECTION INPUT ;
    USE SIGNAL ;
    ANTENNAGATEAREA 0.196500 ;
    PORT
      LAYER met3 ;
        RECT 596.000 189.080 600.000 189.680 ;
    END
  END sports_i[28]
  PIN sports_i[29]
    DIRECTION INPUT ;
    USE SIGNAL ;
    ANTENNAGATEAREA 0.196500 ;
    PORT
      LAYER met3 ;
        RECT 596.000 190.440 600.000 191.040 ;
    END
  END sports_i[29]
  PIN sports_i[2]
    DIRECTION INPUT ;
    USE SIGNAL ;
    ANTENNAGATEAREA 0.196500 ;
    PORT
      LAYER met3 ;
        RECT 596.000 153.720 600.000 154.320 ;
    END
  END sports_i[2]
  PIN sports_i[30]
    DIRECTION INPUT ;
    USE SIGNAL ;
    ANTENNAGATEAREA 0.196500 ;
    PORT
      LAYER met3 ;
        RECT 596.000 191.800 600.000 192.400 ;
    END
  END sports_i[30]
  PIN sports_i[31]
    DIRECTION INPUT ;
    USE SIGNAL ;
    ANTENNAGATEAREA 0.126000 ;
    PORT
      LAYER met3 ;
        RECT 596.000 193.160 600.000 193.760 ;
    END
  END sports_i[31]
  PIN sports_i[32]
    DIRECTION INPUT ;
    USE SIGNAL ;
    ANTENNAGATEAREA 0.247500 ;
    PORT
      LAYER met3 ;
        RECT 596.000 194.520 600.000 195.120 ;
    END
  END sports_i[32]
  PIN sports_i[33]
    DIRECTION INPUT ;
    USE SIGNAL ;
    ANTENNAGATEAREA 0.196500 ;
    PORT
      LAYER met3 ;
        RECT 596.000 195.880 600.000 196.480 ;
    END
  END sports_i[33]
  PIN sports_i[34]
    DIRECTION INPUT ;
    USE SIGNAL ;
    ANTENNAGATEAREA 0.126000 ;
    PORT
      LAYER met3 ;
        RECT 596.000 197.240 600.000 197.840 ;
    END
  END sports_i[34]
  PIN sports_i[35]
    DIRECTION INPUT ;
    USE SIGNAL ;
    ANTENNAGATEAREA 0.126000 ;
    PORT
      LAYER met3 ;
        RECT 596.000 198.600 600.000 199.200 ;
    END
  END sports_i[35]
  PIN sports_i[36]
    DIRECTION INPUT ;
    USE SIGNAL ;
    ANTENNAGATEAREA 0.213000 ;
    PORT
      LAYER met3 ;
        RECT 596.000 199.960 600.000 200.560 ;
    END
  END sports_i[36]
  PIN sports_i[37]
    DIRECTION INPUT ;
    USE SIGNAL ;
    ANTENNAGATEAREA 0.213000 ;
    PORT
      LAYER met3 ;
        RECT 596.000 201.320 600.000 201.920 ;
    END
  END sports_i[37]
  PIN sports_i[38]
    DIRECTION INPUT ;
    USE SIGNAL ;
    ANTENNAGATEAREA 0.213000 ;
    PORT
      LAYER met3 ;
        RECT 596.000 202.680 600.000 203.280 ;
    END
  END sports_i[38]
  PIN sports_i[39]
    DIRECTION INPUT ;
    USE SIGNAL ;
    ANTENNAGATEAREA 0.213000 ;
    PORT
      LAYER met3 ;
        RECT 596.000 204.040 600.000 204.640 ;
    END
  END sports_i[39]
  PIN sports_i[3]
    DIRECTION INPUT ;
    USE SIGNAL ;
    ANTENNAGATEAREA 0.196500 ;
    PORT
      LAYER met3 ;
        RECT 596.000 155.080 600.000 155.680 ;
    END
  END sports_i[3]
  PIN sports_i[40]
    DIRECTION INPUT ;
    USE SIGNAL ;
    ANTENNAGATEAREA 0.213000 ;
    PORT
      LAYER met3 ;
        RECT 596.000 205.400 600.000 206.000 ;
    END
  END sports_i[40]
  PIN sports_i[41]
    DIRECTION INPUT ;
    USE SIGNAL ;
    ANTENNAGATEAREA 0.126000 ;
    PORT
      LAYER met3 ;
        RECT 596.000 206.760 600.000 207.360 ;
    END
  END sports_i[41]
  PIN sports_i[42]
    DIRECTION INPUT ;
    USE SIGNAL ;
    ANTENNAGATEAREA 0.213000 ;
    PORT
      LAYER met3 ;
        RECT 596.000 208.120 600.000 208.720 ;
    END
  END sports_i[42]
  PIN sports_i[43]
    DIRECTION INPUT ;
    USE SIGNAL ;
    ANTENNAGATEAREA 0.126000 ;
    PORT
      LAYER met3 ;
        RECT 596.000 209.480 600.000 210.080 ;
    END
  END sports_i[43]
  PIN sports_i[44]
    DIRECTION INPUT ;
    USE SIGNAL ;
    ANTENNAGATEAREA 0.126000 ;
    PORT
      LAYER met3 ;
        RECT 596.000 210.840 600.000 211.440 ;
    END
  END sports_i[44]
  PIN sports_i[45]
    DIRECTION INPUT ;
    USE SIGNAL ;
    ANTENNAGATEAREA 0.213000 ;
    PORT
      LAYER met3 ;
        RECT 596.000 212.200 600.000 212.800 ;
    END
  END sports_i[45]
  PIN sports_i[46]
    DIRECTION INPUT ;
    USE SIGNAL ;
    ANTENNAGATEAREA 0.213000 ;
    PORT
      LAYER met3 ;
        RECT 596.000 213.560 600.000 214.160 ;
    END
  END sports_i[46]
  PIN sports_i[47]
    DIRECTION INPUT ;
    USE SIGNAL ;
    ANTENNAGATEAREA 0.126000 ;
    PORT
      LAYER met3 ;
        RECT 596.000 214.920 600.000 215.520 ;
    END
  END sports_i[47]
  PIN sports_i[48]
    DIRECTION INPUT ;
    USE SIGNAL ;
    ANTENNAGATEAREA 0.213000 ;
    PORT
      LAYER met3 ;
        RECT 596.000 216.280 600.000 216.880 ;
    END
  END sports_i[48]
  PIN sports_i[49]
    DIRECTION INPUT ;
    USE SIGNAL ;
    ANTENNAGATEAREA 0.196500 ;
    PORT
      LAYER met3 ;
        RECT 596.000 217.640 600.000 218.240 ;
    END
  END sports_i[49]
  PIN sports_i[4]
    DIRECTION INPUT ;
    USE SIGNAL ;
    ANTENNAGATEAREA 0.196500 ;
    PORT
      LAYER met3 ;
        RECT 596.000 156.440 600.000 157.040 ;
    END
  END sports_i[4]
  PIN sports_i[50]
    DIRECTION INPUT ;
    USE SIGNAL ;
    ANTENNAGATEAREA 0.213000 ;
    PORT
      LAYER met3 ;
        RECT 596.000 219.000 600.000 219.600 ;
    END
  END sports_i[50]
  PIN sports_i[51]
    DIRECTION INPUT ;
    USE SIGNAL ;
    ANTENNAGATEAREA 0.213000 ;
    PORT
      LAYER met3 ;
        RECT 596.000 220.360 600.000 220.960 ;
    END
  END sports_i[51]
  PIN sports_i[52]
    DIRECTION INPUT ;
    USE SIGNAL ;
    ANTENNAGATEAREA 0.126000 ;
    PORT
      LAYER met3 ;
        RECT 596.000 221.720 600.000 222.320 ;
    END
  END sports_i[52]
  PIN sports_i[53]
    DIRECTION INPUT ;
    USE SIGNAL ;
    ANTENNAGATEAREA 0.126000 ;
    PORT
      LAYER met3 ;
        RECT 596.000 223.080 600.000 223.680 ;
    END
  END sports_i[53]
  PIN sports_i[54]
    DIRECTION INPUT ;
    USE SIGNAL ;
    ANTENNAGATEAREA 0.126000 ;
    PORT
      LAYER met3 ;
        RECT 596.000 224.440 600.000 225.040 ;
    END
  END sports_i[54]
  PIN sports_i[55]
    DIRECTION INPUT ;
    USE SIGNAL ;
    ANTENNAGATEAREA 0.196500 ;
    PORT
      LAYER met3 ;
        RECT 596.000 225.800 600.000 226.400 ;
    END
  END sports_i[55]
  PIN sports_i[56]
    DIRECTION INPUT ;
    USE SIGNAL ;
    ANTENNAGATEAREA 0.196500 ;
    PORT
      LAYER met3 ;
        RECT 596.000 227.160 600.000 227.760 ;
    END
  END sports_i[56]
  PIN sports_i[57]
    DIRECTION INPUT ;
    USE SIGNAL ;
    ANTENNAGATEAREA 0.196500 ;
    PORT
      LAYER met3 ;
        RECT 596.000 228.520 600.000 229.120 ;
    END
  END sports_i[57]
  PIN sports_i[58]
    DIRECTION INPUT ;
    USE SIGNAL ;
    ANTENNAGATEAREA 0.126000 ;
    PORT
      LAYER met3 ;
        RECT 596.000 229.880 600.000 230.480 ;
    END
  END sports_i[58]
  PIN sports_i[59]
    DIRECTION INPUT ;
    USE SIGNAL ;
    ANTENNAGATEAREA 0.126000 ;
    PORT
      LAYER met3 ;
        RECT 596.000 231.240 600.000 231.840 ;
    END
  END sports_i[59]
  PIN sports_i[5]
    DIRECTION INPUT ;
    USE SIGNAL ;
    ANTENNAGATEAREA 0.196500 ;
    PORT
      LAYER met3 ;
        RECT 596.000 157.800 600.000 158.400 ;
    END
  END sports_i[5]
  PIN sports_i[60]
    DIRECTION INPUT ;
    USE SIGNAL ;
    ANTENNAGATEAREA 0.196500 ;
    PORT
      LAYER met3 ;
        RECT 596.000 232.600 600.000 233.200 ;
    END
  END sports_i[60]
  PIN sports_i[61]
    DIRECTION INPUT ;
    USE SIGNAL ;
    ANTENNAGATEAREA 0.196500 ;
    PORT
      LAYER met3 ;
        RECT 596.000 233.960 600.000 234.560 ;
    END
  END sports_i[61]
  PIN sports_i[62]
    DIRECTION INPUT ;
    USE SIGNAL ;
    ANTENNAGATEAREA 0.196500 ;
    PORT
      LAYER met3 ;
        RECT 596.000 235.320 600.000 235.920 ;
    END
  END sports_i[62]
  PIN sports_i[63]
    DIRECTION INPUT ;
    USE SIGNAL ;
    ANTENNAGATEAREA 0.196500 ;
    PORT
      LAYER met3 ;
        RECT 596.000 236.680 600.000 237.280 ;
    END
  END sports_i[63]
  PIN sports_i[64]
    DIRECTION INPUT ;
    USE SIGNAL ;
    ANTENNAGATEAREA 0.196500 ;
    PORT
      LAYER met3 ;
        RECT 596.000 238.040 600.000 238.640 ;
    END
  END sports_i[64]
  PIN sports_i[65]
    DIRECTION INPUT ;
    USE SIGNAL ;
    ANTENNAGATEAREA 0.196500 ;
    PORT
      LAYER met3 ;
        RECT 596.000 239.400 600.000 240.000 ;
    END
  END sports_i[65]
  PIN sports_i[66]
    DIRECTION INPUT ;
    USE SIGNAL ;
    ANTENNAGATEAREA 0.247500 ;
    PORT
      LAYER met3 ;
        RECT 596.000 240.760 600.000 241.360 ;
    END
  END sports_i[66]
  PIN sports_i[67]
    DIRECTION INPUT ;
    USE SIGNAL ;
    ANTENNAGATEAREA 0.196500 ;
    PORT
      LAYER met3 ;
        RECT 596.000 242.120 600.000 242.720 ;
    END
  END sports_i[67]
  PIN sports_i[68]
    DIRECTION INPUT ;
    USE SIGNAL ;
    ANTENNAGATEAREA 0.159000 ;
    PORT
      LAYER met3 ;
        RECT 596.000 243.480 600.000 244.080 ;
    END
  END sports_i[68]
  PIN sports_i[69]
    DIRECTION INPUT ;
    USE SIGNAL ;
    ANTENNAGATEAREA 0.213000 ;
    PORT
      LAYER met3 ;
        RECT 596.000 244.840 600.000 245.440 ;
    END
  END sports_i[69]
  PIN sports_i[6]
    DIRECTION INPUT ;
    USE SIGNAL ;
    ANTENNAGATEAREA 0.196500 ;
    PORT
      LAYER met3 ;
        RECT 596.000 159.160 600.000 159.760 ;
    END
  END sports_i[6]
  PIN sports_i[70]
    DIRECTION INPUT ;
    USE SIGNAL ;
    ANTENNAGATEAREA 0.159000 ;
    PORT
      LAYER met3 ;
        RECT 596.000 246.200 600.000 246.800 ;
    END
  END sports_i[70]
  PIN sports_i[71]
    DIRECTION INPUT ;
    USE SIGNAL ;
    ANTENNAGATEAREA 0.159000 ;
    PORT
      LAYER met3 ;
        RECT 596.000 247.560 600.000 248.160 ;
    END
  END sports_i[71]
  PIN sports_i[72]
    DIRECTION INPUT ;
    USE SIGNAL ;
    ANTENNAGATEAREA 0.213000 ;
    PORT
      LAYER met3 ;
        RECT 596.000 248.920 600.000 249.520 ;
    END
  END sports_i[72]
  PIN sports_i[73]
    DIRECTION INPUT ;
    USE SIGNAL ;
    ANTENNAGATEAREA 0.213000 ;
    PORT
      LAYER met3 ;
        RECT 596.000 250.280 600.000 250.880 ;
    END
  END sports_i[73]
  PIN sports_i[74]
    DIRECTION INPUT ;
    USE SIGNAL ;
    ANTENNAGATEAREA 0.159000 ;
    PORT
      LAYER met3 ;
        RECT 596.000 251.640 600.000 252.240 ;
    END
  END sports_i[74]
  PIN sports_i[75]
    DIRECTION INPUT ;
    USE SIGNAL ;
    ANTENNAGATEAREA 0.213000 ;
    PORT
      LAYER met3 ;
        RECT 596.000 253.000 600.000 253.600 ;
    END
  END sports_i[75]
  PIN sports_i[76]
    DIRECTION INPUT ;
    USE SIGNAL ;
    ANTENNAGATEAREA 0.213000 ;
    PORT
      LAYER met3 ;
        RECT 596.000 254.360 600.000 254.960 ;
    END
  END sports_i[76]
  PIN sports_i[77]
    DIRECTION INPUT ;
    USE SIGNAL ;
    ANTENNAGATEAREA 0.213000 ;
    PORT
      LAYER met3 ;
        RECT 596.000 255.720 600.000 256.320 ;
    END
  END sports_i[77]
  PIN sports_i[78]
    DIRECTION INPUT ;
    USE SIGNAL ;
    ANTENNAGATEAREA 0.213000 ;
    PORT
      LAYER met3 ;
        RECT 596.000 257.080 600.000 257.680 ;
    END
  END sports_i[78]
  PIN sports_i[79]
    DIRECTION INPUT ;
    USE SIGNAL ;
    ANTENNAGATEAREA 0.159000 ;
    PORT
      LAYER met3 ;
        RECT 596.000 258.440 600.000 259.040 ;
    END
  END sports_i[79]
  PIN sports_i[7]
    DIRECTION INPUT ;
    USE SIGNAL ;
    ANTENNAGATEAREA 0.196500 ;
    PORT
      LAYER met3 ;
        RECT 596.000 160.520 600.000 161.120 ;
    END
  END sports_i[7]
  PIN sports_i[80]
    DIRECTION INPUT ;
    USE SIGNAL ;
    ANTENNAGATEAREA 0.159000 ;
    PORT
      LAYER met3 ;
        RECT 596.000 259.800 600.000 260.400 ;
    END
  END sports_i[80]
  PIN sports_i[81]
    DIRECTION INPUT ;
    USE SIGNAL ;
    ANTENNAGATEAREA 0.213000 ;
    PORT
      LAYER met3 ;
        RECT 596.000 261.160 600.000 261.760 ;
    END
  END sports_i[81]
  PIN sports_i[82]
    DIRECTION INPUT ;
    USE SIGNAL ;
    ANTENNAGATEAREA 0.159000 ;
    PORT
      LAYER met3 ;
        RECT 596.000 262.520 600.000 263.120 ;
    END
  END sports_i[82]
  PIN sports_i[83]
    DIRECTION INPUT ;
    USE SIGNAL ;
    ANTENNAGATEAREA 0.159000 ;
    PORT
      LAYER met3 ;
        RECT 596.000 263.880 600.000 264.480 ;
    END
  END sports_i[83]
  PIN sports_i[84]
    DIRECTION INPUT ;
    USE SIGNAL ;
    ANTENNAGATEAREA 0.159000 ;
    PORT
      LAYER met3 ;
        RECT 596.000 265.240 600.000 265.840 ;
    END
  END sports_i[84]
  PIN sports_i[85]
    DIRECTION INPUT ;
    USE SIGNAL ;
    ANTENNAGATEAREA 0.159000 ;
    PORT
      LAYER met3 ;
        RECT 596.000 266.600 600.000 267.200 ;
    END
  END sports_i[85]
  PIN sports_i[86]
    DIRECTION INPUT ;
    USE SIGNAL ;
    ANTENNAGATEAREA 0.213000 ;
    PORT
      LAYER met3 ;
        RECT 596.000 267.960 600.000 268.560 ;
    END
  END sports_i[86]
  PIN sports_i[87]
    DIRECTION INPUT ;
    USE SIGNAL ;
    ANTENNAGATEAREA 0.213000 ;
    PORT
      LAYER met3 ;
        RECT 596.000 269.320 600.000 269.920 ;
    END
  END sports_i[87]
  PIN sports_i[88]
    DIRECTION INPUT ;
    USE SIGNAL ;
    ANTENNAGATEAREA 0.213000 ;
    PORT
      LAYER met3 ;
        RECT 596.000 270.680 600.000 271.280 ;
    END
  END sports_i[88]
  PIN sports_i[89]
    DIRECTION INPUT ;
    USE SIGNAL ;
    ANTENNAGATEAREA 0.213000 ;
    PORT
      LAYER met3 ;
        RECT 596.000 272.040 600.000 272.640 ;
    END
  END sports_i[89]
  PIN sports_i[8]
    DIRECTION INPUT ;
    USE SIGNAL ;
    ANTENNAGATEAREA 0.196500 ;
    PORT
      LAYER met3 ;
        RECT 596.000 161.880 600.000 162.480 ;
    END
  END sports_i[8]
  PIN sports_i[90]
    DIRECTION INPUT ;
    USE SIGNAL ;
    ANTENNAGATEAREA 0.213000 ;
    PORT
      LAYER met3 ;
        RECT 596.000 273.400 600.000 274.000 ;
    END
  END sports_i[90]
  PIN sports_i[91]
    DIRECTION INPUT ;
    USE SIGNAL ;
    ANTENNAGATEAREA 0.213000 ;
    PORT
      LAYER met3 ;
        RECT 596.000 274.760 600.000 275.360 ;
    END
  END sports_i[91]
  PIN sports_i[92]
    DIRECTION INPUT ;
    USE SIGNAL ;
    ANTENNAGATEAREA 0.213000 ;
    PORT
      LAYER met3 ;
        RECT 596.000 276.120 600.000 276.720 ;
    END
  END sports_i[92]
  PIN sports_i[93]
    DIRECTION INPUT ;
    USE SIGNAL ;
    ANTENNAGATEAREA 0.213000 ;
    PORT
      LAYER met3 ;
        RECT 596.000 277.480 600.000 278.080 ;
    END
  END sports_i[93]
  PIN sports_i[94]
    DIRECTION INPUT ;
    USE SIGNAL ;
    ANTENNAGATEAREA 0.213000 ;
    PORT
      LAYER met3 ;
        RECT 596.000 278.840 600.000 279.440 ;
    END
  END sports_i[94]
  PIN sports_i[95]
    DIRECTION INPUT ;
    USE SIGNAL ;
    ANTENNAGATEAREA 0.213000 ;
    PORT
      LAYER met3 ;
        RECT 596.000 280.200 600.000 280.800 ;
    END
  END sports_i[95]
  PIN sports_i[96]
    DIRECTION INPUT ;
    USE SIGNAL ;
    ANTENNAGATEAREA 0.213000 ;
    PORT
      LAYER met3 ;
        RECT 596.000 281.560 600.000 282.160 ;
    END
  END sports_i[96]
  PIN sports_i[97]
    DIRECTION INPUT ;
    USE SIGNAL ;
    ANTENNAGATEAREA 0.213000 ;
    PORT
      LAYER met3 ;
        RECT 596.000 282.920 600.000 283.520 ;
    END
  END sports_i[97]
  PIN sports_i[98]
    DIRECTION INPUT ;
    USE SIGNAL ;
    ANTENNAGATEAREA 0.213000 ;
    PORT
      LAYER met3 ;
        RECT 596.000 284.280 600.000 284.880 ;
    END
  END sports_i[98]
  PIN sports_i[99]
    DIRECTION INPUT ;
    USE SIGNAL ;
    ANTENNAGATEAREA 0.213000 ;
    PORT
      LAYER met3 ;
        RECT 596.000 285.640 600.000 286.240 ;
    END
  END sports_i[99]
  PIN sports_i[9]
    DIRECTION INPUT ;
    USE SIGNAL ;
    ANTENNAGATEAREA 0.196500 ;
    PORT
      LAYER met3 ;
        RECT 596.000 163.240 600.000 163.840 ;
    END
  END sports_i[9]
  PIN sports_o[0]
    DIRECTION OUTPUT TRISTATE ;
    USE SIGNAL ;
    ANTENNADIFFAREA 0.795200 ;
    PORT
      LAYER met2 ;
        RECT 394.310 296.000 394.590 300.000 ;
    END
  END sports_o[0]
  PIN sports_o[100]
    DIRECTION OUTPUT TRISTATE ;
    USE SIGNAL ;
    ANTENNADIFFAREA 0.795200 ;
    PORT
      LAYER met2 ;
        RECT 486.310 296.000 486.590 300.000 ;
    END
  END sports_o[100]
  PIN sports_o[101]
    DIRECTION OUTPUT TRISTATE ;
    USE SIGNAL ;
    ANTENNADIFFAREA 0.795200 ;
    PORT
      LAYER met2 ;
        RECT 487.230 296.000 487.510 300.000 ;
    END
  END sports_o[101]
  PIN sports_o[102]
    DIRECTION OUTPUT TRISTATE ;
    USE SIGNAL ;
    ANTENNADIFFAREA 0.795200 ;
    PORT
      LAYER met2 ;
        RECT 488.150 296.000 488.430 300.000 ;
    END
  END sports_o[102]
  PIN sports_o[103]
    DIRECTION OUTPUT TRISTATE ;
    USE SIGNAL ;
    ANTENNADIFFAREA 0.795200 ;
    PORT
      LAYER met2 ;
        RECT 489.070 296.000 489.350 300.000 ;
    END
  END sports_o[103]
  PIN sports_o[104]
    DIRECTION OUTPUT TRISTATE ;
    USE SIGNAL ;
    ANTENNADIFFAREA 0.795200 ;
    PORT
      LAYER met2 ;
        RECT 489.990 296.000 490.270 300.000 ;
    END
  END sports_o[104]
  PIN sports_o[105]
    DIRECTION OUTPUT TRISTATE ;
    USE SIGNAL ;
    ANTENNADIFFAREA 0.795200 ;
    PORT
      LAYER met2 ;
        RECT 490.910 296.000 491.190 300.000 ;
    END
  END sports_o[105]
  PIN sports_o[106]
    DIRECTION OUTPUT TRISTATE ;
    USE SIGNAL ;
    ANTENNADIFFAREA 0.795200 ;
    PORT
      LAYER met2 ;
        RECT 491.830 296.000 492.110 300.000 ;
    END
  END sports_o[106]
  PIN sports_o[107]
    DIRECTION OUTPUT TRISTATE ;
    USE SIGNAL ;
    ANTENNADIFFAREA 0.795200 ;
    PORT
      LAYER met2 ;
        RECT 492.750 296.000 493.030 300.000 ;
    END
  END sports_o[107]
  PIN sports_o[108]
    DIRECTION OUTPUT TRISTATE ;
    USE SIGNAL ;
    ANTENNADIFFAREA 0.795200 ;
    PORT
      LAYER met2 ;
        RECT 493.670 296.000 493.950 300.000 ;
    END
  END sports_o[108]
  PIN sports_o[109]
    DIRECTION OUTPUT TRISTATE ;
    USE SIGNAL ;
    ANTENNADIFFAREA 0.795200 ;
    PORT
      LAYER met2 ;
        RECT 494.590 296.000 494.870 300.000 ;
    END
  END sports_o[109]
  PIN sports_o[10]
    DIRECTION OUTPUT TRISTATE ;
    USE SIGNAL ;
    ANTENNADIFFAREA 0.795200 ;
    PORT
      LAYER met2 ;
        RECT 403.510 296.000 403.790 300.000 ;
    END
  END sports_o[10]
  PIN sports_o[110]
    DIRECTION OUTPUT TRISTATE ;
    USE SIGNAL ;
    ANTENNADIFFAREA 0.795200 ;
    PORT
      LAYER met2 ;
        RECT 495.510 296.000 495.790 300.000 ;
    END
  END sports_o[110]
  PIN sports_o[111]
    DIRECTION OUTPUT TRISTATE ;
    USE SIGNAL ;
    ANTENNADIFFAREA 0.795200 ;
    PORT
      LAYER met2 ;
        RECT 496.430 296.000 496.710 300.000 ;
    END
  END sports_o[111]
  PIN sports_o[112]
    DIRECTION OUTPUT TRISTATE ;
    USE SIGNAL ;
    ANTENNADIFFAREA 0.795200 ;
    PORT
      LAYER met2 ;
        RECT 497.350 296.000 497.630 300.000 ;
    END
  END sports_o[112]
  PIN sports_o[113]
    DIRECTION OUTPUT TRISTATE ;
    USE SIGNAL ;
    ANTENNADIFFAREA 0.795200 ;
    PORT
      LAYER met2 ;
        RECT 498.270 296.000 498.550 300.000 ;
    END
  END sports_o[113]
  PIN sports_o[114]
    DIRECTION OUTPUT TRISTATE ;
    USE SIGNAL ;
    ANTENNADIFFAREA 0.795200 ;
    PORT
      LAYER met2 ;
        RECT 499.190 296.000 499.470 300.000 ;
    END
  END sports_o[114]
  PIN sports_o[115]
    DIRECTION OUTPUT TRISTATE ;
    USE SIGNAL ;
    ANTENNADIFFAREA 0.795200 ;
    PORT
      LAYER met2 ;
        RECT 500.110 296.000 500.390 300.000 ;
    END
  END sports_o[115]
  PIN sports_o[116]
    DIRECTION OUTPUT TRISTATE ;
    USE SIGNAL ;
    ANTENNADIFFAREA 0.795200 ;
    PORT
      LAYER met2 ;
        RECT 501.030 296.000 501.310 300.000 ;
    END
  END sports_o[116]
  PIN sports_o[117]
    DIRECTION OUTPUT TRISTATE ;
    USE SIGNAL ;
    ANTENNADIFFAREA 0.795200 ;
    PORT
      LAYER met2 ;
        RECT 501.950 296.000 502.230 300.000 ;
    END
  END sports_o[117]
  PIN sports_o[118]
    DIRECTION OUTPUT TRISTATE ;
    USE SIGNAL ;
    ANTENNADIFFAREA 0.795200 ;
    PORT
      LAYER met2 ;
        RECT 502.870 296.000 503.150 300.000 ;
    END
  END sports_o[118]
  PIN sports_o[119]
    DIRECTION OUTPUT TRISTATE ;
    USE SIGNAL ;
    ANTENNADIFFAREA 0.795200 ;
    PORT
      LAYER met2 ;
        RECT 503.790 296.000 504.070 300.000 ;
    END
  END sports_o[119]
  PIN sports_o[11]
    DIRECTION OUTPUT TRISTATE ;
    USE SIGNAL ;
    ANTENNADIFFAREA 0.795200 ;
    PORT
      LAYER met2 ;
        RECT 404.430 296.000 404.710 300.000 ;
    END
  END sports_o[11]
  PIN sports_o[120]
    DIRECTION OUTPUT TRISTATE ;
    USE SIGNAL ;
    ANTENNADIFFAREA 0.795200 ;
    PORT
      LAYER met2 ;
        RECT 504.710 296.000 504.990 300.000 ;
    END
  END sports_o[120]
  PIN sports_o[121]
    DIRECTION OUTPUT TRISTATE ;
    USE SIGNAL ;
    ANTENNADIFFAREA 0.795200 ;
    PORT
      LAYER met2 ;
        RECT 505.630 296.000 505.910 300.000 ;
    END
  END sports_o[121]
  PIN sports_o[122]
    DIRECTION OUTPUT TRISTATE ;
    USE SIGNAL ;
    ANTENNADIFFAREA 0.795200 ;
    PORT
      LAYER met2 ;
        RECT 506.550 296.000 506.830 300.000 ;
    END
  END sports_o[122]
  PIN sports_o[123]
    DIRECTION OUTPUT TRISTATE ;
    USE SIGNAL ;
    ANTENNADIFFAREA 0.795200 ;
    PORT
      LAYER met2 ;
        RECT 507.470 296.000 507.750 300.000 ;
    END
  END sports_o[123]
  PIN sports_o[124]
    DIRECTION OUTPUT TRISTATE ;
    USE SIGNAL ;
    ANTENNADIFFAREA 0.795200 ;
    PORT
      LAYER met2 ;
        RECT 508.390 296.000 508.670 300.000 ;
    END
  END sports_o[124]
  PIN sports_o[125]
    DIRECTION OUTPUT TRISTATE ;
    USE SIGNAL ;
    ANTENNADIFFAREA 0.795200 ;
    PORT
      LAYER met2 ;
        RECT 509.310 296.000 509.590 300.000 ;
    END
  END sports_o[125]
  PIN sports_o[126]
    DIRECTION OUTPUT TRISTATE ;
    USE SIGNAL ;
    ANTENNADIFFAREA 0.795200 ;
    PORT
      LAYER met2 ;
        RECT 510.230 296.000 510.510 300.000 ;
    END
  END sports_o[126]
  PIN sports_o[127]
    DIRECTION OUTPUT TRISTATE ;
    USE SIGNAL ;
    ANTENNADIFFAREA 0.795200 ;
    PORT
      LAYER met2 ;
        RECT 511.150 296.000 511.430 300.000 ;
    END
  END sports_o[127]
  PIN sports_o[128]
    DIRECTION OUTPUT TRISTATE ;
    USE SIGNAL ;
    ANTENNADIFFAREA 0.795200 ;
    PORT
      LAYER met2 ;
        RECT 512.070 296.000 512.350 300.000 ;
    END
  END sports_o[128]
  PIN sports_o[129]
    DIRECTION OUTPUT TRISTATE ;
    USE SIGNAL ;
    ANTENNADIFFAREA 0.795200 ;
    PORT
      LAYER met2 ;
        RECT 512.990 296.000 513.270 300.000 ;
    END
  END sports_o[129]
  PIN sports_o[12]
    DIRECTION OUTPUT TRISTATE ;
    USE SIGNAL ;
    ANTENNADIFFAREA 0.795200 ;
    PORT
      LAYER met2 ;
        RECT 405.350 296.000 405.630 300.000 ;
    END
  END sports_o[12]
  PIN sports_o[130]
    DIRECTION OUTPUT TRISTATE ;
    USE SIGNAL ;
    ANTENNADIFFAREA 0.795200 ;
    PORT
      LAYER met2 ;
        RECT 513.910 296.000 514.190 300.000 ;
    END
  END sports_o[130]
  PIN sports_o[131]
    DIRECTION OUTPUT TRISTATE ;
    USE SIGNAL ;
    ANTENNADIFFAREA 0.795200 ;
    PORT
      LAYER met2 ;
        RECT 514.830 296.000 515.110 300.000 ;
    END
  END sports_o[131]
  PIN sports_o[132]
    DIRECTION OUTPUT TRISTATE ;
    USE SIGNAL ;
    ANTENNADIFFAREA 0.795200 ;
    PORT
      LAYER met2 ;
        RECT 515.750 296.000 516.030 300.000 ;
    END
  END sports_o[132]
  PIN sports_o[133]
    DIRECTION OUTPUT TRISTATE ;
    USE SIGNAL ;
    ANTENNADIFFAREA 0.795200 ;
    PORT
      LAYER met2 ;
        RECT 516.670 296.000 516.950 300.000 ;
    END
  END sports_o[133]
  PIN sports_o[134]
    DIRECTION OUTPUT TRISTATE ;
    USE SIGNAL ;
    ANTENNADIFFAREA 0.795200 ;
    PORT
      LAYER met2 ;
        RECT 517.590 296.000 517.870 300.000 ;
    END
  END sports_o[134]
  PIN sports_o[135]
    DIRECTION OUTPUT TRISTATE ;
    USE SIGNAL ;
    ANTENNADIFFAREA 0.795200 ;
    PORT
      LAYER met2 ;
        RECT 518.510 296.000 518.790 300.000 ;
    END
  END sports_o[135]
  PIN sports_o[136]
    DIRECTION OUTPUT TRISTATE ;
    USE SIGNAL ;
    ANTENNADIFFAREA 0.795200 ;
    PORT
      LAYER met2 ;
        RECT 519.430 296.000 519.710 300.000 ;
    END
  END sports_o[136]
  PIN sports_o[137]
    DIRECTION OUTPUT TRISTATE ;
    USE SIGNAL ;
    ANTENNADIFFAREA 0.795200 ;
    PORT
      LAYER met2 ;
        RECT 520.350 296.000 520.630 300.000 ;
    END
  END sports_o[137]
  PIN sports_o[138]
    DIRECTION OUTPUT TRISTATE ;
    USE SIGNAL ;
    ANTENNADIFFAREA 0.795200 ;
    PORT
      LAYER met2 ;
        RECT 521.270 296.000 521.550 300.000 ;
    END
  END sports_o[138]
  PIN sports_o[139]
    DIRECTION OUTPUT TRISTATE ;
    USE SIGNAL ;
    ANTENNADIFFAREA 0.795200 ;
    PORT
      LAYER met2 ;
        RECT 522.190 296.000 522.470 300.000 ;
    END
  END sports_o[139]
  PIN sports_o[13]
    DIRECTION OUTPUT TRISTATE ;
    USE SIGNAL ;
    ANTENNADIFFAREA 0.795200 ;
    PORT
      LAYER met2 ;
        RECT 406.270 296.000 406.550 300.000 ;
    END
  END sports_o[13]
  PIN sports_o[140]
    DIRECTION OUTPUT TRISTATE ;
    USE SIGNAL ;
    ANTENNADIFFAREA 0.795200 ;
    PORT
      LAYER met2 ;
        RECT 523.110 296.000 523.390 300.000 ;
    END
  END sports_o[140]
  PIN sports_o[141]
    DIRECTION OUTPUT TRISTATE ;
    USE SIGNAL ;
    ANTENNADIFFAREA 0.795200 ;
    PORT
      LAYER met2 ;
        RECT 524.030 296.000 524.310 300.000 ;
    END
  END sports_o[141]
  PIN sports_o[142]
    DIRECTION OUTPUT TRISTATE ;
    USE SIGNAL ;
    ANTENNADIFFAREA 0.795200 ;
    PORT
      LAYER met2 ;
        RECT 524.950 296.000 525.230 300.000 ;
    END
  END sports_o[142]
  PIN sports_o[143]
    DIRECTION OUTPUT TRISTATE ;
    USE SIGNAL ;
    ANTENNADIFFAREA 0.795200 ;
    PORT
      LAYER met2 ;
        RECT 525.870 296.000 526.150 300.000 ;
    END
  END sports_o[143]
  PIN sports_o[144]
    DIRECTION OUTPUT TRISTATE ;
    USE SIGNAL ;
    ANTENNADIFFAREA 0.795200 ;
    PORT
      LAYER met2 ;
        RECT 526.790 296.000 527.070 300.000 ;
    END
  END sports_o[144]
  PIN sports_o[145]
    DIRECTION OUTPUT TRISTATE ;
    USE SIGNAL ;
    ANTENNADIFFAREA 0.795200 ;
    PORT
      LAYER met2 ;
        RECT 527.710 296.000 527.990 300.000 ;
    END
  END sports_o[145]
  PIN sports_o[146]
    DIRECTION OUTPUT TRISTATE ;
    USE SIGNAL ;
    ANTENNADIFFAREA 0.795200 ;
    PORT
      LAYER met2 ;
        RECT 528.630 296.000 528.910 300.000 ;
    END
  END sports_o[146]
  PIN sports_o[147]
    DIRECTION OUTPUT TRISTATE ;
    USE SIGNAL ;
    ANTENNADIFFAREA 0.795200 ;
    PORT
      LAYER met2 ;
        RECT 529.550 296.000 529.830 300.000 ;
    END
  END sports_o[147]
  PIN sports_o[148]
    DIRECTION OUTPUT TRISTATE ;
    USE SIGNAL ;
    ANTENNADIFFAREA 0.795200 ;
    PORT
      LAYER met2 ;
        RECT 530.470 296.000 530.750 300.000 ;
    END
  END sports_o[148]
  PIN sports_o[149]
    DIRECTION OUTPUT TRISTATE ;
    USE SIGNAL ;
    ANTENNADIFFAREA 0.795200 ;
    PORT
      LAYER met2 ;
        RECT 531.390 296.000 531.670 300.000 ;
    END
  END sports_o[149]
  PIN sports_o[14]
    DIRECTION OUTPUT TRISTATE ;
    USE SIGNAL ;
    ANTENNADIFFAREA 0.795200 ;
    PORT
      LAYER met2 ;
        RECT 407.190 296.000 407.470 300.000 ;
    END
  END sports_o[14]
  PIN sports_o[150]
    DIRECTION OUTPUT TRISTATE ;
    USE SIGNAL ;
    ANTENNADIFFAREA 0.795200 ;
    PORT
      LAYER met2 ;
        RECT 532.310 296.000 532.590 300.000 ;
    END
  END sports_o[150]
  PIN sports_o[151]
    DIRECTION OUTPUT TRISTATE ;
    USE SIGNAL ;
    ANTENNADIFFAREA 0.795200 ;
    PORT
      LAYER met2 ;
        RECT 533.230 296.000 533.510 300.000 ;
    END
  END sports_o[151]
  PIN sports_o[152]
    DIRECTION OUTPUT TRISTATE ;
    USE SIGNAL ;
    ANTENNADIFFAREA 0.795200 ;
    PORT
      LAYER met2 ;
        RECT 534.150 296.000 534.430 300.000 ;
    END
  END sports_o[152]
  PIN sports_o[153]
    DIRECTION OUTPUT TRISTATE ;
    USE SIGNAL ;
    ANTENNADIFFAREA 0.795200 ;
    PORT
      LAYER met2 ;
        RECT 535.070 296.000 535.350 300.000 ;
    END
  END sports_o[153]
  PIN sports_o[154]
    DIRECTION OUTPUT TRISTATE ;
    USE SIGNAL ;
    ANTENNADIFFAREA 0.795200 ;
    PORT
      LAYER met2 ;
        RECT 535.990 296.000 536.270 300.000 ;
    END
  END sports_o[154]
  PIN sports_o[155]
    DIRECTION OUTPUT TRISTATE ;
    USE SIGNAL ;
    ANTENNADIFFAREA 0.795200 ;
    PORT
      LAYER met2 ;
        RECT 536.910 296.000 537.190 300.000 ;
    END
  END sports_o[155]
  PIN sports_o[156]
    DIRECTION OUTPUT TRISTATE ;
    USE SIGNAL ;
    ANTENNADIFFAREA 0.795200 ;
    PORT
      LAYER met2 ;
        RECT 537.830 296.000 538.110 300.000 ;
    END
  END sports_o[156]
  PIN sports_o[157]
    DIRECTION OUTPUT TRISTATE ;
    USE SIGNAL ;
    ANTENNADIFFAREA 0.795200 ;
    PORT
      LAYER met2 ;
        RECT 538.750 296.000 539.030 300.000 ;
    END
  END sports_o[157]
  PIN sports_o[158]
    DIRECTION OUTPUT TRISTATE ;
    USE SIGNAL ;
    ANTENNADIFFAREA 0.795200 ;
    PORT
      LAYER met2 ;
        RECT 539.670 296.000 539.950 300.000 ;
    END
  END sports_o[158]
  PIN sports_o[159]
    DIRECTION OUTPUT TRISTATE ;
    USE SIGNAL ;
    ANTENNADIFFAREA 0.795200 ;
    PORT
      LAYER met2 ;
        RECT 540.590 296.000 540.870 300.000 ;
    END
  END sports_o[159]
  PIN sports_o[15]
    DIRECTION OUTPUT TRISTATE ;
    USE SIGNAL ;
    ANTENNADIFFAREA 0.795200 ;
    PORT
      LAYER met2 ;
        RECT 408.110 296.000 408.390 300.000 ;
    END
  END sports_o[15]
  PIN sports_o[160]
    DIRECTION OUTPUT TRISTATE ;
    USE SIGNAL ;
    ANTENNADIFFAREA 0.795200 ;
    PORT
      LAYER met2 ;
        RECT 541.510 296.000 541.790 300.000 ;
    END
  END sports_o[160]
  PIN sports_o[161]
    DIRECTION OUTPUT TRISTATE ;
    USE SIGNAL ;
    ANTENNADIFFAREA 0.795200 ;
    PORT
      LAYER met2 ;
        RECT 542.430 296.000 542.710 300.000 ;
    END
  END sports_o[161]
  PIN sports_o[162]
    DIRECTION OUTPUT TRISTATE ;
    USE SIGNAL ;
    ANTENNADIFFAREA 0.795200 ;
    PORT
      LAYER met2 ;
        RECT 543.350 296.000 543.630 300.000 ;
    END
  END sports_o[162]
  PIN sports_o[163]
    DIRECTION OUTPUT TRISTATE ;
    USE SIGNAL ;
    ANTENNADIFFAREA 0.795200 ;
    PORT
      LAYER met2 ;
        RECT 544.270 296.000 544.550 300.000 ;
    END
  END sports_o[163]
  PIN sports_o[164]
    DIRECTION OUTPUT TRISTATE ;
    USE SIGNAL ;
    ANTENNADIFFAREA 0.795200 ;
    PORT
      LAYER met2 ;
        RECT 545.190 296.000 545.470 300.000 ;
    END
  END sports_o[164]
  PIN sports_o[165]
    DIRECTION OUTPUT TRISTATE ;
    USE SIGNAL ;
    ANTENNADIFFAREA 0.795200 ;
    PORT
      LAYER met2 ;
        RECT 546.110 296.000 546.390 300.000 ;
    END
  END sports_o[165]
  PIN sports_o[166]
    DIRECTION OUTPUT TRISTATE ;
    USE SIGNAL ;
    ANTENNADIFFAREA 0.795200 ;
    PORT
      LAYER met2 ;
        RECT 547.030 296.000 547.310 300.000 ;
    END
  END sports_o[166]
  PIN sports_o[167]
    DIRECTION OUTPUT TRISTATE ;
    USE SIGNAL ;
    ANTENNADIFFAREA 0.795200 ;
    PORT
      LAYER met2 ;
        RECT 547.950 296.000 548.230 300.000 ;
    END
  END sports_o[167]
  PIN sports_o[168]
    DIRECTION OUTPUT TRISTATE ;
    USE SIGNAL ;
    ANTENNADIFFAREA 0.795200 ;
    PORT
      LAYER met2 ;
        RECT 548.870 296.000 549.150 300.000 ;
    END
  END sports_o[168]
  PIN sports_o[169]
    DIRECTION OUTPUT TRISTATE ;
    USE SIGNAL ;
    ANTENNADIFFAREA 0.795200 ;
    PORT
      LAYER met2 ;
        RECT 549.790 296.000 550.070 300.000 ;
    END
  END sports_o[169]
  PIN sports_o[16]
    DIRECTION OUTPUT TRISTATE ;
    USE SIGNAL ;
    ANTENNADIFFAREA 0.795200 ;
    PORT
      LAYER met2 ;
        RECT 409.030 296.000 409.310 300.000 ;
    END
  END sports_o[16]
  PIN sports_o[170]
    DIRECTION OUTPUT TRISTATE ;
    USE SIGNAL ;
    ANTENNADIFFAREA 0.795200 ;
    PORT
      LAYER met2 ;
        RECT 550.710 296.000 550.990 300.000 ;
    END
  END sports_o[170]
  PIN sports_o[171]
    DIRECTION OUTPUT TRISTATE ;
    USE SIGNAL ;
    ANTENNADIFFAREA 0.795200 ;
    PORT
      LAYER met2 ;
        RECT 551.630 296.000 551.910 300.000 ;
    END
  END sports_o[171]
  PIN sports_o[172]
    DIRECTION OUTPUT TRISTATE ;
    USE SIGNAL ;
    ANTENNADIFFAREA 0.795200 ;
    PORT
      LAYER met2 ;
        RECT 552.550 296.000 552.830 300.000 ;
    END
  END sports_o[172]
  PIN sports_o[173]
    DIRECTION OUTPUT TRISTATE ;
    USE SIGNAL ;
    ANTENNADIFFAREA 0.795200 ;
    PORT
      LAYER met2 ;
        RECT 553.470 296.000 553.750 300.000 ;
    END
  END sports_o[173]
  PIN sports_o[174]
    DIRECTION OUTPUT TRISTATE ;
    USE SIGNAL ;
    ANTENNADIFFAREA 0.795200 ;
    PORT
      LAYER met2 ;
        RECT 554.390 296.000 554.670 300.000 ;
    END
  END sports_o[174]
  PIN sports_o[175]
    DIRECTION OUTPUT TRISTATE ;
    USE SIGNAL ;
    ANTENNADIFFAREA 0.795200 ;
    PORT
      LAYER met2 ;
        RECT 555.310 296.000 555.590 300.000 ;
    END
  END sports_o[175]
  PIN sports_o[176]
    DIRECTION OUTPUT TRISTATE ;
    USE SIGNAL ;
    ANTENNADIFFAREA 0.795200 ;
    PORT
      LAYER met2 ;
        RECT 556.230 296.000 556.510 300.000 ;
    END
  END sports_o[176]
  PIN sports_o[177]
    DIRECTION OUTPUT TRISTATE ;
    USE SIGNAL ;
    ANTENNADIFFAREA 0.795200 ;
    PORT
      LAYER met2 ;
        RECT 557.150 296.000 557.430 300.000 ;
    END
  END sports_o[177]
  PIN sports_o[178]
    DIRECTION OUTPUT TRISTATE ;
    USE SIGNAL ;
    ANTENNADIFFAREA 0.795200 ;
    PORT
      LAYER met2 ;
        RECT 558.070 296.000 558.350 300.000 ;
    END
  END sports_o[178]
  PIN sports_o[179]
    DIRECTION OUTPUT TRISTATE ;
    USE SIGNAL ;
    ANTENNADIFFAREA 0.795200 ;
    PORT
      LAYER met2 ;
        RECT 558.990 296.000 559.270 300.000 ;
    END
  END sports_o[179]
  PIN sports_o[17]
    DIRECTION OUTPUT TRISTATE ;
    USE SIGNAL ;
    ANTENNADIFFAREA 0.795200 ;
    PORT
      LAYER met2 ;
        RECT 409.950 296.000 410.230 300.000 ;
    END
  END sports_o[17]
  PIN sports_o[180]
    DIRECTION OUTPUT TRISTATE ;
    USE SIGNAL ;
    ANTENNADIFFAREA 0.795200 ;
    PORT
      LAYER met2 ;
        RECT 559.910 296.000 560.190 300.000 ;
    END
  END sports_o[180]
  PIN sports_o[181]
    DIRECTION OUTPUT TRISTATE ;
    USE SIGNAL ;
    ANTENNADIFFAREA 0.795200 ;
    PORT
      LAYER met2 ;
        RECT 560.830 296.000 561.110 300.000 ;
    END
  END sports_o[181]
  PIN sports_o[182]
    DIRECTION OUTPUT TRISTATE ;
    USE SIGNAL ;
    ANTENNADIFFAREA 0.795200 ;
    PORT
      LAYER met2 ;
        RECT 561.750 296.000 562.030 300.000 ;
    END
  END sports_o[182]
  PIN sports_o[183]
    DIRECTION OUTPUT TRISTATE ;
    USE SIGNAL ;
    ANTENNADIFFAREA 0.795200 ;
    PORT
      LAYER met2 ;
        RECT 562.670 296.000 562.950 300.000 ;
    END
  END sports_o[183]
  PIN sports_o[184]
    DIRECTION OUTPUT TRISTATE ;
    USE SIGNAL ;
    ANTENNADIFFAREA 0.795200 ;
    PORT
      LAYER met2 ;
        RECT 563.590 296.000 563.870 300.000 ;
    END
  END sports_o[184]
  PIN sports_o[185]
    DIRECTION OUTPUT TRISTATE ;
    USE SIGNAL ;
    ANTENNADIFFAREA 0.795200 ;
    PORT
      LAYER met2 ;
        RECT 564.510 296.000 564.790 300.000 ;
    END
  END sports_o[185]
  PIN sports_o[186]
    DIRECTION OUTPUT TRISTATE ;
    USE SIGNAL ;
    ANTENNADIFFAREA 0.795200 ;
    PORT
      LAYER met2 ;
        RECT 565.430 296.000 565.710 300.000 ;
    END
  END sports_o[186]
  PIN sports_o[187]
    DIRECTION OUTPUT TRISTATE ;
    USE SIGNAL ;
    ANTENNADIFFAREA 0.795200 ;
    PORT
      LAYER met2 ;
        RECT 566.350 296.000 566.630 300.000 ;
    END
  END sports_o[187]
  PIN sports_o[188]
    DIRECTION OUTPUT TRISTATE ;
    USE SIGNAL ;
    ANTENNADIFFAREA 0.795200 ;
    PORT
      LAYER met2 ;
        RECT 567.270 296.000 567.550 300.000 ;
    END
  END sports_o[188]
  PIN sports_o[189]
    DIRECTION OUTPUT TRISTATE ;
    USE SIGNAL ;
    ANTENNADIFFAREA 0.795200 ;
    PORT
      LAYER met2 ;
        RECT 568.190 296.000 568.470 300.000 ;
    END
  END sports_o[189]
  PIN sports_o[18]
    DIRECTION OUTPUT TRISTATE ;
    USE SIGNAL ;
    ANTENNADIFFAREA 0.795200 ;
    PORT
      LAYER met2 ;
        RECT 410.870 296.000 411.150 300.000 ;
    END
  END sports_o[18]
  PIN sports_o[190]
    DIRECTION OUTPUT TRISTATE ;
    USE SIGNAL ;
    ANTENNADIFFAREA 0.795200 ;
    PORT
      LAYER met2 ;
        RECT 569.110 296.000 569.390 300.000 ;
    END
  END sports_o[190]
  PIN sports_o[191]
    DIRECTION OUTPUT TRISTATE ;
    USE SIGNAL ;
    ANTENNADIFFAREA 0.795200 ;
    PORT
      LAYER met2 ;
        RECT 570.030 296.000 570.310 300.000 ;
    END
  END sports_o[191]
  PIN sports_o[192]
    DIRECTION OUTPUT TRISTATE ;
    USE SIGNAL ;
    ANTENNADIFFAREA 0.795200 ;
    PORT
      LAYER met2 ;
        RECT 570.950 296.000 571.230 300.000 ;
    END
  END sports_o[192]
  PIN sports_o[193]
    DIRECTION OUTPUT TRISTATE ;
    USE SIGNAL ;
    ANTENNADIFFAREA 0.795200 ;
    PORT
      LAYER met2 ;
        RECT 571.870 296.000 572.150 300.000 ;
    END
  END sports_o[193]
  PIN sports_o[194]
    DIRECTION OUTPUT TRISTATE ;
    USE SIGNAL ;
    ANTENNADIFFAREA 0.795200 ;
    PORT
      LAYER met2 ;
        RECT 572.790 296.000 573.070 300.000 ;
    END
  END sports_o[194]
  PIN sports_o[195]
    DIRECTION OUTPUT TRISTATE ;
    USE SIGNAL ;
    ANTENNADIFFAREA 0.795200 ;
    PORT
      LAYER met2 ;
        RECT 573.710 296.000 573.990 300.000 ;
    END
  END sports_o[195]
  PIN sports_o[196]
    DIRECTION OUTPUT TRISTATE ;
    USE SIGNAL ;
    ANTENNADIFFAREA 0.795200 ;
    PORT
      LAYER met2 ;
        RECT 574.630 296.000 574.910 300.000 ;
    END
  END sports_o[196]
  PIN sports_o[197]
    DIRECTION OUTPUT TRISTATE ;
    USE SIGNAL ;
    ANTENNADIFFAREA 0.795200 ;
    PORT
      LAYER met2 ;
        RECT 575.550 296.000 575.830 300.000 ;
    END
  END sports_o[197]
  PIN sports_o[198]
    DIRECTION OUTPUT TRISTATE ;
    USE SIGNAL ;
    ANTENNADIFFAREA 0.795200 ;
    PORT
      LAYER met2 ;
        RECT 576.470 296.000 576.750 300.000 ;
    END
  END sports_o[198]
  PIN sports_o[199]
    DIRECTION OUTPUT TRISTATE ;
    USE SIGNAL ;
    ANTENNADIFFAREA 0.795200 ;
    PORT
      LAYER met2 ;
        RECT 577.390 296.000 577.670 300.000 ;
    END
  END sports_o[199]
  PIN sports_o[19]
    DIRECTION OUTPUT TRISTATE ;
    USE SIGNAL ;
    ANTENNADIFFAREA 0.795200 ;
    PORT
      LAYER met2 ;
        RECT 411.790 296.000 412.070 300.000 ;
    END
  END sports_o[19]
  PIN sports_o[1]
    DIRECTION OUTPUT TRISTATE ;
    USE SIGNAL ;
    ANTENNADIFFAREA 0.795200 ;
    PORT
      LAYER met2 ;
        RECT 395.230 296.000 395.510 300.000 ;
    END
  END sports_o[1]
  PIN sports_o[200]
    DIRECTION OUTPUT TRISTATE ;
    USE SIGNAL ;
    ANTENNADIFFAREA 0.795200 ;
    PORT
      LAYER met2 ;
        RECT 578.310 296.000 578.590 300.000 ;
    END
  END sports_o[200]
  PIN sports_o[201]
    DIRECTION OUTPUT TRISTATE ;
    USE SIGNAL ;
    ANTENNADIFFAREA 0.795200 ;
    PORT
      LAYER met2 ;
        RECT 579.230 296.000 579.510 300.000 ;
    END
  END sports_o[201]
  PIN sports_o[202]
    DIRECTION OUTPUT TRISTATE ;
    USE SIGNAL ;
    ANTENNADIFFAREA 0.795200 ;
    PORT
      LAYER met2 ;
        RECT 580.150 296.000 580.430 300.000 ;
    END
  END sports_o[202]
  PIN sports_o[203]
    DIRECTION OUTPUT TRISTATE ;
    USE SIGNAL ;
    ANTENNADIFFAREA 0.795200 ;
    PORT
      LAYER met2 ;
        RECT 581.070 296.000 581.350 300.000 ;
    END
  END sports_o[203]
  PIN sports_o[204]
    DIRECTION OUTPUT TRISTATE ;
    USE SIGNAL ;
    ANTENNADIFFAREA 0.795200 ;
    PORT
      LAYER met2 ;
        RECT 581.990 296.000 582.270 300.000 ;
    END
  END sports_o[204]
  PIN sports_o[205]
    DIRECTION OUTPUT TRISTATE ;
    USE SIGNAL ;
    ANTENNADIFFAREA 0.795200 ;
    PORT
      LAYER met2 ;
        RECT 582.910 296.000 583.190 300.000 ;
    END
  END sports_o[205]
  PIN sports_o[206]
    DIRECTION OUTPUT TRISTATE ;
    USE SIGNAL ;
    ANTENNADIFFAREA 0.795200 ;
    PORT
      LAYER met2 ;
        RECT 583.830 296.000 584.110 300.000 ;
    END
  END sports_o[206]
  PIN sports_o[20]
    DIRECTION OUTPUT TRISTATE ;
    USE SIGNAL ;
    ANTENNADIFFAREA 0.795200 ;
    PORT
      LAYER met2 ;
        RECT 412.710 296.000 412.990 300.000 ;
    END
  END sports_o[20]
  PIN sports_o[21]
    DIRECTION OUTPUT TRISTATE ;
    USE SIGNAL ;
    ANTENNADIFFAREA 0.795200 ;
    PORT
      LAYER met2 ;
        RECT 413.630 296.000 413.910 300.000 ;
    END
  END sports_o[21]
  PIN sports_o[22]
    DIRECTION OUTPUT TRISTATE ;
    USE SIGNAL ;
    ANTENNADIFFAREA 0.795200 ;
    PORT
      LAYER met2 ;
        RECT 414.550 296.000 414.830 300.000 ;
    END
  END sports_o[22]
  PIN sports_o[23]
    DIRECTION OUTPUT TRISTATE ;
    USE SIGNAL ;
    ANTENNADIFFAREA 0.795200 ;
    PORT
      LAYER met2 ;
        RECT 415.470 296.000 415.750 300.000 ;
    END
  END sports_o[23]
  PIN sports_o[24]
    DIRECTION OUTPUT TRISTATE ;
    USE SIGNAL ;
    ANTENNADIFFAREA 0.795200 ;
    PORT
      LAYER met2 ;
        RECT 416.390 296.000 416.670 300.000 ;
    END
  END sports_o[24]
  PIN sports_o[25]
    DIRECTION OUTPUT TRISTATE ;
    USE SIGNAL ;
    ANTENNADIFFAREA 0.795200 ;
    PORT
      LAYER met2 ;
        RECT 417.310 296.000 417.590 300.000 ;
    END
  END sports_o[25]
  PIN sports_o[26]
    DIRECTION OUTPUT TRISTATE ;
    USE SIGNAL ;
    ANTENNADIFFAREA 0.795200 ;
    PORT
      LAYER met2 ;
        RECT 418.230 296.000 418.510 300.000 ;
    END
  END sports_o[26]
  PIN sports_o[27]
    DIRECTION OUTPUT TRISTATE ;
    USE SIGNAL ;
    ANTENNADIFFAREA 0.795200 ;
    PORT
      LAYER met2 ;
        RECT 419.150 296.000 419.430 300.000 ;
    END
  END sports_o[27]
  PIN sports_o[28]
    DIRECTION OUTPUT TRISTATE ;
    USE SIGNAL ;
    ANTENNADIFFAREA 0.795200 ;
    PORT
      LAYER met2 ;
        RECT 420.070 296.000 420.350 300.000 ;
    END
  END sports_o[28]
  PIN sports_o[29]
    DIRECTION OUTPUT TRISTATE ;
    USE SIGNAL ;
    ANTENNADIFFAREA 0.795200 ;
    PORT
      LAYER met2 ;
        RECT 420.990 296.000 421.270 300.000 ;
    END
  END sports_o[29]
  PIN sports_o[2]
    DIRECTION OUTPUT TRISTATE ;
    USE SIGNAL ;
    ANTENNADIFFAREA 0.795200 ;
    PORT
      LAYER met2 ;
        RECT 396.150 296.000 396.430 300.000 ;
    END
  END sports_o[2]
  PIN sports_o[30]
    DIRECTION OUTPUT TRISTATE ;
    USE SIGNAL ;
    ANTENNADIFFAREA 0.795200 ;
    PORT
      LAYER met2 ;
        RECT 421.910 296.000 422.190 300.000 ;
    END
  END sports_o[30]
  PIN sports_o[31]
    DIRECTION OUTPUT TRISTATE ;
    USE SIGNAL ;
    ANTENNADIFFAREA 0.795200 ;
    PORT
      LAYER met2 ;
        RECT 422.830 296.000 423.110 300.000 ;
    END
  END sports_o[31]
  PIN sports_o[32]
    DIRECTION OUTPUT TRISTATE ;
    USE SIGNAL ;
    ANTENNADIFFAREA 0.795200 ;
    PORT
      LAYER met2 ;
        RECT 423.750 296.000 424.030 300.000 ;
    END
  END sports_o[32]
  PIN sports_o[33]
    DIRECTION OUTPUT TRISTATE ;
    USE SIGNAL ;
    ANTENNADIFFAREA 0.795200 ;
    PORT
      LAYER met2 ;
        RECT 424.670 296.000 424.950 300.000 ;
    END
  END sports_o[33]
  PIN sports_o[34]
    DIRECTION OUTPUT TRISTATE ;
    USE SIGNAL ;
    ANTENNADIFFAREA 0.795200 ;
    PORT
      LAYER met2 ;
        RECT 425.590 296.000 425.870 300.000 ;
    END
  END sports_o[34]
  PIN sports_o[35]
    DIRECTION OUTPUT TRISTATE ;
    USE SIGNAL ;
    ANTENNADIFFAREA 0.795200 ;
    PORT
      LAYER met2 ;
        RECT 426.510 296.000 426.790 300.000 ;
    END
  END sports_o[35]
  PIN sports_o[36]
    DIRECTION OUTPUT TRISTATE ;
    USE SIGNAL ;
    ANTENNADIFFAREA 0.795200 ;
    PORT
      LAYER met2 ;
        RECT 427.430 296.000 427.710 300.000 ;
    END
  END sports_o[36]
  PIN sports_o[37]
    DIRECTION OUTPUT TRISTATE ;
    USE SIGNAL ;
    ANTENNADIFFAREA 0.795200 ;
    PORT
      LAYER met2 ;
        RECT 428.350 296.000 428.630 300.000 ;
    END
  END sports_o[37]
  PIN sports_o[38]
    DIRECTION OUTPUT TRISTATE ;
    USE SIGNAL ;
    ANTENNADIFFAREA 0.795200 ;
    PORT
      LAYER met2 ;
        RECT 429.270 296.000 429.550 300.000 ;
    END
  END sports_o[38]
  PIN sports_o[39]
    DIRECTION OUTPUT TRISTATE ;
    USE SIGNAL ;
    ANTENNADIFFAREA 0.795200 ;
    PORT
      LAYER met2 ;
        RECT 430.190 296.000 430.470 300.000 ;
    END
  END sports_o[39]
  PIN sports_o[3]
    DIRECTION OUTPUT TRISTATE ;
    USE SIGNAL ;
    ANTENNADIFFAREA 0.795200 ;
    PORT
      LAYER met2 ;
        RECT 397.070 296.000 397.350 300.000 ;
    END
  END sports_o[3]
  PIN sports_o[40]
    DIRECTION OUTPUT TRISTATE ;
    USE SIGNAL ;
    ANTENNADIFFAREA 0.795200 ;
    PORT
      LAYER met2 ;
        RECT 431.110 296.000 431.390 300.000 ;
    END
  END sports_o[40]
  PIN sports_o[41]
    DIRECTION OUTPUT TRISTATE ;
    USE SIGNAL ;
    ANTENNADIFFAREA 0.795200 ;
    PORT
      LAYER met2 ;
        RECT 432.030 296.000 432.310 300.000 ;
    END
  END sports_o[41]
  PIN sports_o[42]
    DIRECTION OUTPUT TRISTATE ;
    USE SIGNAL ;
    ANTENNADIFFAREA 0.795200 ;
    PORT
      LAYER met2 ;
        RECT 432.950 296.000 433.230 300.000 ;
    END
  END sports_o[42]
  PIN sports_o[43]
    DIRECTION OUTPUT TRISTATE ;
    USE SIGNAL ;
    ANTENNADIFFAREA 0.795200 ;
    PORT
      LAYER met2 ;
        RECT 433.870 296.000 434.150 300.000 ;
    END
  END sports_o[43]
  PIN sports_o[44]
    DIRECTION OUTPUT TRISTATE ;
    USE SIGNAL ;
    ANTENNADIFFAREA 0.795200 ;
    PORT
      LAYER met2 ;
        RECT 434.790 296.000 435.070 300.000 ;
    END
  END sports_o[44]
  PIN sports_o[45]
    DIRECTION OUTPUT TRISTATE ;
    USE SIGNAL ;
    ANTENNADIFFAREA 0.795200 ;
    PORT
      LAYER met2 ;
        RECT 435.710 296.000 435.990 300.000 ;
    END
  END sports_o[45]
  PIN sports_o[46]
    DIRECTION OUTPUT TRISTATE ;
    USE SIGNAL ;
    ANTENNADIFFAREA 0.795200 ;
    PORT
      LAYER met2 ;
        RECT 436.630 296.000 436.910 300.000 ;
    END
  END sports_o[46]
  PIN sports_o[47]
    DIRECTION OUTPUT TRISTATE ;
    USE SIGNAL ;
    ANTENNADIFFAREA 0.795200 ;
    PORT
      LAYER met2 ;
        RECT 437.550 296.000 437.830 300.000 ;
    END
  END sports_o[47]
  PIN sports_o[48]
    DIRECTION OUTPUT TRISTATE ;
    USE SIGNAL ;
    ANTENNADIFFAREA 0.795200 ;
    PORT
      LAYER met2 ;
        RECT 438.470 296.000 438.750 300.000 ;
    END
  END sports_o[48]
  PIN sports_o[49]
    DIRECTION OUTPUT TRISTATE ;
    USE SIGNAL ;
    ANTENNADIFFAREA 0.795200 ;
    PORT
      LAYER met2 ;
        RECT 439.390 296.000 439.670 300.000 ;
    END
  END sports_o[49]
  PIN sports_o[4]
    DIRECTION OUTPUT TRISTATE ;
    USE SIGNAL ;
    ANTENNADIFFAREA 0.795200 ;
    PORT
      LAYER met2 ;
        RECT 397.990 296.000 398.270 300.000 ;
    END
  END sports_o[4]
  PIN sports_o[50]
    DIRECTION OUTPUT TRISTATE ;
    USE SIGNAL ;
    ANTENNADIFFAREA 0.795200 ;
    PORT
      LAYER met2 ;
        RECT 440.310 296.000 440.590 300.000 ;
    END
  END sports_o[50]
  PIN sports_o[51]
    DIRECTION OUTPUT TRISTATE ;
    USE SIGNAL ;
    ANTENNADIFFAREA 0.795200 ;
    PORT
      LAYER met2 ;
        RECT 441.230 296.000 441.510 300.000 ;
    END
  END sports_o[51]
  PIN sports_o[52]
    DIRECTION OUTPUT TRISTATE ;
    USE SIGNAL ;
    ANTENNADIFFAREA 0.795200 ;
    PORT
      LAYER met2 ;
        RECT 442.150 296.000 442.430 300.000 ;
    END
  END sports_o[52]
  PIN sports_o[53]
    DIRECTION OUTPUT TRISTATE ;
    USE SIGNAL ;
    ANTENNADIFFAREA 0.795200 ;
    PORT
      LAYER met2 ;
        RECT 443.070 296.000 443.350 300.000 ;
    END
  END sports_o[53]
  PIN sports_o[54]
    DIRECTION OUTPUT TRISTATE ;
    USE SIGNAL ;
    ANTENNADIFFAREA 0.795200 ;
    PORT
      LAYER met2 ;
        RECT 443.990 296.000 444.270 300.000 ;
    END
  END sports_o[54]
  PIN sports_o[55]
    DIRECTION OUTPUT TRISTATE ;
    USE SIGNAL ;
    ANTENNADIFFAREA 0.795200 ;
    PORT
      LAYER met2 ;
        RECT 444.910 296.000 445.190 300.000 ;
    END
  END sports_o[55]
  PIN sports_o[56]
    DIRECTION OUTPUT TRISTATE ;
    USE SIGNAL ;
    ANTENNADIFFAREA 0.795200 ;
    PORT
      LAYER met2 ;
        RECT 445.830 296.000 446.110 300.000 ;
    END
  END sports_o[56]
  PIN sports_o[57]
    DIRECTION OUTPUT TRISTATE ;
    USE SIGNAL ;
    ANTENNADIFFAREA 0.795200 ;
    PORT
      LAYER met2 ;
        RECT 446.750 296.000 447.030 300.000 ;
    END
  END sports_o[57]
  PIN sports_o[58]
    DIRECTION OUTPUT TRISTATE ;
    USE SIGNAL ;
    ANTENNADIFFAREA 0.795200 ;
    PORT
      LAYER met2 ;
        RECT 447.670 296.000 447.950 300.000 ;
    END
  END sports_o[58]
  PIN sports_o[59]
    DIRECTION OUTPUT TRISTATE ;
    USE SIGNAL ;
    ANTENNADIFFAREA 0.795200 ;
    PORT
      LAYER met2 ;
        RECT 448.590 296.000 448.870 300.000 ;
    END
  END sports_o[59]
  PIN sports_o[5]
    DIRECTION OUTPUT TRISTATE ;
    USE SIGNAL ;
    ANTENNADIFFAREA 0.795200 ;
    PORT
      LAYER met2 ;
        RECT 398.910 296.000 399.190 300.000 ;
    END
  END sports_o[5]
  PIN sports_o[60]
    DIRECTION OUTPUT TRISTATE ;
    USE SIGNAL ;
    ANTENNADIFFAREA 0.795200 ;
    PORT
      LAYER met2 ;
        RECT 449.510 296.000 449.790 300.000 ;
    END
  END sports_o[60]
  PIN sports_o[61]
    DIRECTION OUTPUT TRISTATE ;
    USE SIGNAL ;
    ANTENNADIFFAREA 0.795200 ;
    PORT
      LAYER met2 ;
        RECT 450.430 296.000 450.710 300.000 ;
    END
  END sports_o[61]
  PIN sports_o[62]
    DIRECTION OUTPUT TRISTATE ;
    USE SIGNAL ;
    ANTENNADIFFAREA 0.795200 ;
    PORT
      LAYER met2 ;
        RECT 451.350 296.000 451.630 300.000 ;
    END
  END sports_o[62]
  PIN sports_o[63]
    DIRECTION OUTPUT TRISTATE ;
    USE SIGNAL ;
    ANTENNADIFFAREA 0.795200 ;
    PORT
      LAYER met2 ;
        RECT 452.270 296.000 452.550 300.000 ;
    END
  END sports_o[63]
  PIN sports_o[64]
    DIRECTION OUTPUT TRISTATE ;
    USE SIGNAL ;
    ANTENNADIFFAREA 0.795200 ;
    PORT
      LAYER met2 ;
        RECT 453.190 296.000 453.470 300.000 ;
    END
  END sports_o[64]
  PIN sports_o[65]
    DIRECTION OUTPUT TRISTATE ;
    USE SIGNAL ;
    ANTENNADIFFAREA 0.795200 ;
    PORT
      LAYER met2 ;
        RECT 454.110 296.000 454.390 300.000 ;
    END
  END sports_o[65]
  PIN sports_o[66]
    DIRECTION OUTPUT TRISTATE ;
    USE SIGNAL ;
    ANTENNADIFFAREA 0.795200 ;
    PORT
      LAYER met2 ;
        RECT 455.030 296.000 455.310 300.000 ;
    END
  END sports_o[66]
  PIN sports_o[67]
    DIRECTION OUTPUT TRISTATE ;
    USE SIGNAL ;
    ANTENNADIFFAREA 0.795200 ;
    PORT
      LAYER met2 ;
        RECT 455.950 296.000 456.230 300.000 ;
    END
  END sports_o[67]
  PIN sports_o[68]
    DIRECTION OUTPUT TRISTATE ;
    USE SIGNAL ;
    ANTENNADIFFAREA 0.795200 ;
    PORT
      LAYER met2 ;
        RECT 456.870 296.000 457.150 300.000 ;
    END
  END sports_o[68]
  PIN sports_o[69]
    DIRECTION OUTPUT TRISTATE ;
    USE SIGNAL ;
    ANTENNADIFFAREA 0.795200 ;
    PORT
      LAYER met2 ;
        RECT 457.790 296.000 458.070 300.000 ;
    END
  END sports_o[69]
  PIN sports_o[6]
    DIRECTION OUTPUT TRISTATE ;
    USE SIGNAL ;
    ANTENNADIFFAREA 0.795200 ;
    PORT
      LAYER met2 ;
        RECT 399.830 296.000 400.110 300.000 ;
    END
  END sports_o[6]
  PIN sports_o[70]
    DIRECTION OUTPUT TRISTATE ;
    USE SIGNAL ;
    ANTENNADIFFAREA 0.795200 ;
    PORT
      LAYER met2 ;
        RECT 458.710 296.000 458.990 300.000 ;
    END
  END sports_o[70]
  PIN sports_o[71]
    DIRECTION OUTPUT TRISTATE ;
    USE SIGNAL ;
    ANTENNADIFFAREA 0.795200 ;
    PORT
      LAYER met2 ;
        RECT 459.630 296.000 459.910 300.000 ;
    END
  END sports_o[71]
  PIN sports_o[72]
    DIRECTION OUTPUT TRISTATE ;
    USE SIGNAL ;
    ANTENNADIFFAREA 0.795200 ;
    PORT
      LAYER met2 ;
        RECT 460.550 296.000 460.830 300.000 ;
    END
  END sports_o[72]
  PIN sports_o[73]
    DIRECTION OUTPUT TRISTATE ;
    USE SIGNAL ;
    ANTENNADIFFAREA 0.795200 ;
    PORT
      LAYER met2 ;
        RECT 461.470 296.000 461.750 300.000 ;
    END
  END sports_o[73]
  PIN sports_o[74]
    DIRECTION OUTPUT TRISTATE ;
    USE SIGNAL ;
    ANTENNADIFFAREA 0.795200 ;
    PORT
      LAYER met2 ;
        RECT 462.390 296.000 462.670 300.000 ;
    END
  END sports_o[74]
  PIN sports_o[75]
    DIRECTION OUTPUT TRISTATE ;
    USE SIGNAL ;
    ANTENNADIFFAREA 0.795200 ;
    PORT
      LAYER met2 ;
        RECT 463.310 296.000 463.590 300.000 ;
    END
  END sports_o[75]
  PIN sports_o[76]
    DIRECTION OUTPUT TRISTATE ;
    USE SIGNAL ;
    ANTENNADIFFAREA 0.795200 ;
    PORT
      LAYER met2 ;
        RECT 464.230 296.000 464.510 300.000 ;
    END
  END sports_o[76]
  PIN sports_o[77]
    DIRECTION OUTPUT TRISTATE ;
    USE SIGNAL ;
    ANTENNADIFFAREA 0.795200 ;
    PORT
      LAYER met2 ;
        RECT 465.150 296.000 465.430 300.000 ;
    END
  END sports_o[77]
  PIN sports_o[78]
    DIRECTION OUTPUT TRISTATE ;
    USE SIGNAL ;
    ANTENNADIFFAREA 0.795200 ;
    PORT
      LAYER met2 ;
        RECT 466.070 296.000 466.350 300.000 ;
    END
  END sports_o[78]
  PIN sports_o[79]
    DIRECTION OUTPUT TRISTATE ;
    USE SIGNAL ;
    ANTENNADIFFAREA 0.795200 ;
    PORT
      LAYER met2 ;
        RECT 466.990 296.000 467.270 300.000 ;
    END
  END sports_o[79]
  PIN sports_o[7]
    DIRECTION OUTPUT TRISTATE ;
    USE SIGNAL ;
    ANTENNADIFFAREA 0.795200 ;
    PORT
      LAYER met2 ;
        RECT 400.750 296.000 401.030 300.000 ;
    END
  END sports_o[7]
  PIN sports_o[80]
    DIRECTION OUTPUT TRISTATE ;
    USE SIGNAL ;
    ANTENNADIFFAREA 0.795200 ;
    PORT
      LAYER met2 ;
        RECT 467.910 296.000 468.190 300.000 ;
    END
  END sports_o[80]
  PIN sports_o[81]
    DIRECTION OUTPUT TRISTATE ;
    USE SIGNAL ;
    ANTENNADIFFAREA 0.795200 ;
    PORT
      LAYER met2 ;
        RECT 468.830 296.000 469.110 300.000 ;
    END
  END sports_o[81]
  PIN sports_o[82]
    DIRECTION OUTPUT TRISTATE ;
    USE SIGNAL ;
    ANTENNADIFFAREA 0.795200 ;
    PORT
      LAYER met2 ;
        RECT 469.750 296.000 470.030 300.000 ;
    END
  END sports_o[82]
  PIN sports_o[83]
    DIRECTION OUTPUT TRISTATE ;
    USE SIGNAL ;
    ANTENNADIFFAREA 0.795200 ;
    PORT
      LAYER met2 ;
        RECT 470.670 296.000 470.950 300.000 ;
    END
  END sports_o[83]
  PIN sports_o[84]
    DIRECTION OUTPUT TRISTATE ;
    USE SIGNAL ;
    ANTENNADIFFAREA 0.795200 ;
    PORT
      LAYER met2 ;
        RECT 471.590 296.000 471.870 300.000 ;
    END
  END sports_o[84]
  PIN sports_o[85]
    DIRECTION OUTPUT TRISTATE ;
    USE SIGNAL ;
    ANTENNADIFFAREA 0.795200 ;
    PORT
      LAYER met2 ;
        RECT 472.510 296.000 472.790 300.000 ;
    END
  END sports_o[85]
  PIN sports_o[86]
    DIRECTION OUTPUT TRISTATE ;
    USE SIGNAL ;
    ANTENNADIFFAREA 0.795200 ;
    PORT
      LAYER met2 ;
        RECT 473.430 296.000 473.710 300.000 ;
    END
  END sports_o[86]
  PIN sports_o[87]
    DIRECTION OUTPUT TRISTATE ;
    USE SIGNAL ;
    ANTENNADIFFAREA 0.795200 ;
    PORT
      LAYER met2 ;
        RECT 474.350 296.000 474.630 300.000 ;
    END
  END sports_o[87]
  PIN sports_o[88]
    DIRECTION OUTPUT TRISTATE ;
    USE SIGNAL ;
    ANTENNADIFFAREA 0.795200 ;
    PORT
      LAYER met2 ;
        RECT 475.270 296.000 475.550 300.000 ;
    END
  END sports_o[88]
  PIN sports_o[89]
    DIRECTION OUTPUT TRISTATE ;
    USE SIGNAL ;
    ANTENNADIFFAREA 0.795200 ;
    PORT
      LAYER met2 ;
        RECT 476.190 296.000 476.470 300.000 ;
    END
  END sports_o[89]
  PIN sports_o[8]
    DIRECTION OUTPUT TRISTATE ;
    USE SIGNAL ;
    ANTENNADIFFAREA 0.795200 ;
    PORT
      LAYER met2 ;
        RECT 401.670 296.000 401.950 300.000 ;
    END
  END sports_o[8]
  PIN sports_o[90]
    DIRECTION OUTPUT TRISTATE ;
    USE SIGNAL ;
    ANTENNADIFFAREA 0.795200 ;
    PORT
      LAYER met2 ;
        RECT 477.110 296.000 477.390 300.000 ;
    END
  END sports_o[90]
  PIN sports_o[91]
    DIRECTION OUTPUT TRISTATE ;
    USE SIGNAL ;
    ANTENNADIFFAREA 0.795200 ;
    PORT
      LAYER met2 ;
        RECT 478.030 296.000 478.310 300.000 ;
    END
  END sports_o[91]
  PIN sports_o[92]
    DIRECTION OUTPUT TRISTATE ;
    USE SIGNAL ;
    ANTENNADIFFAREA 0.795200 ;
    PORT
      LAYER met2 ;
        RECT 478.950 296.000 479.230 300.000 ;
    END
  END sports_o[92]
  PIN sports_o[93]
    DIRECTION OUTPUT TRISTATE ;
    USE SIGNAL ;
    ANTENNADIFFAREA 0.795200 ;
    PORT
      LAYER met2 ;
        RECT 479.870 296.000 480.150 300.000 ;
    END
  END sports_o[93]
  PIN sports_o[94]
    DIRECTION OUTPUT TRISTATE ;
    USE SIGNAL ;
    ANTENNADIFFAREA 0.795200 ;
    PORT
      LAYER met2 ;
        RECT 480.790 296.000 481.070 300.000 ;
    END
  END sports_o[94]
  PIN sports_o[95]
    DIRECTION OUTPUT TRISTATE ;
    USE SIGNAL ;
    ANTENNADIFFAREA 0.795200 ;
    PORT
      LAYER met2 ;
        RECT 481.710 296.000 481.990 300.000 ;
    END
  END sports_o[95]
  PIN sports_o[96]
    DIRECTION OUTPUT TRISTATE ;
    USE SIGNAL ;
    ANTENNADIFFAREA 0.795200 ;
    PORT
      LAYER met2 ;
        RECT 482.630 296.000 482.910 300.000 ;
    END
  END sports_o[96]
  PIN sports_o[97]
    DIRECTION OUTPUT TRISTATE ;
    USE SIGNAL ;
    ANTENNADIFFAREA 0.795200 ;
    PORT
      LAYER met2 ;
        RECT 483.550 296.000 483.830 300.000 ;
    END
  END sports_o[97]
  PIN sports_o[98]
    DIRECTION OUTPUT TRISTATE ;
    USE SIGNAL ;
    ANTENNADIFFAREA 0.795200 ;
    PORT
      LAYER met2 ;
        RECT 484.470 296.000 484.750 300.000 ;
    END
  END sports_o[98]
  PIN sports_o[99]
    DIRECTION OUTPUT TRISTATE ;
    USE SIGNAL ;
    ANTENNADIFFAREA 0.795200 ;
    PORT
      LAYER met2 ;
        RECT 485.390 296.000 485.670 300.000 ;
    END
  END sports_o[99]
  PIN sports_o[9]
    DIRECTION OUTPUT TRISTATE ;
    USE SIGNAL ;
    ANTENNADIFFAREA 0.795200 ;
    PORT
      LAYER met2 ;
        RECT 402.590 296.000 402.870 300.000 ;
    END
  END sports_o[9]
  PIN vccd1
    DIRECTION INOUT ;
    USE POWER ;
    PORT
      LAYER met4 ;
        RECT -2.080 3.280 -0.480 295.920 ;
    END
    PORT
      LAYER met5 ;
        RECT -2.080 3.280 601.920 4.880 ;
    END
    PORT
      LAYER met5 ;
        RECT -2.080 294.320 601.920 295.920 ;
    END
    PORT
      LAYER met4 ;
        RECT 600.320 3.280 601.920 295.920 ;
    END
    PORT
      LAYER met4 ;
        RECT 21.040 -0.020 22.640 299.220 ;
    END
    PORT
      LAYER met4 ;
        RECT 174.640 -0.020 176.240 299.220 ;
    END
    PORT
      LAYER met4 ;
        RECT 328.240 -0.020 329.840 299.220 ;
    END
    PORT
      LAYER met4 ;
        RECT 481.840 -0.020 483.440 299.220 ;
    END
    PORT
      LAYER met5 ;
        RECT -5.380 26.730 605.220 28.330 ;
    END
    PORT
      LAYER met5 ;
        RECT -5.380 179.910 605.220 181.510 ;
    END
  END vccd1
  PIN vssd1
    DIRECTION INOUT ;
    USE GROUND ;
    PORT
      LAYER met4 ;
        RECT -5.380 -0.020 -3.780 299.220 ;
    END
    PORT
      LAYER met5 ;
        RECT -5.380 -0.020 605.220 1.580 ;
    END
    PORT
      LAYER met5 ;
        RECT -5.380 297.620 605.220 299.220 ;
    END
    PORT
      LAYER met4 ;
        RECT 603.620 -0.020 605.220 299.220 ;
    END
    PORT
      LAYER met4 ;
        RECT 24.340 -0.020 25.940 299.220 ;
    END
    PORT
      LAYER met4 ;
        RECT 177.940 -0.020 179.540 299.220 ;
    END
    PORT
      LAYER met4 ;
        RECT 331.540 -0.020 333.140 299.220 ;
    END
    PORT
      LAYER met4 ;
        RECT 485.140 -0.020 486.740 299.220 ;
    END
    PORT
      LAYER met5 ;
        RECT -5.380 30.030 605.220 31.630 ;
    END
    PORT
      LAYER met5 ;
        RECT -5.380 183.210 605.220 184.810 ;
    END
  END vssd1
  OBS
      LAYER li1 ;
        RECT 5.520 10.795 594.320 288.405 ;
      LAYER met1 ;
        RECT 4.670 6.500 599.770 292.360 ;
      LAYER met2 ;
        RECT 4.690 295.720 14.990 296.000 ;
        RECT 15.830 295.720 15.910 296.000 ;
        RECT 16.750 295.720 16.830 296.000 ;
        RECT 17.670 295.720 17.750 296.000 ;
        RECT 18.590 295.720 18.670 296.000 ;
        RECT 19.510 295.720 19.590 296.000 ;
        RECT 20.430 295.720 20.510 296.000 ;
        RECT 21.350 295.720 21.430 296.000 ;
        RECT 22.270 295.720 22.350 296.000 ;
        RECT 23.190 295.720 23.270 296.000 ;
        RECT 24.110 295.720 24.190 296.000 ;
        RECT 25.030 295.720 25.110 296.000 ;
        RECT 25.950 295.720 26.030 296.000 ;
        RECT 26.870 295.720 26.950 296.000 ;
        RECT 27.790 295.720 27.870 296.000 ;
        RECT 28.710 295.720 28.790 296.000 ;
        RECT 29.630 295.720 29.710 296.000 ;
        RECT 30.550 295.720 30.630 296.000 ;
        RECT 31.470 295.720 31.550 296.000 ;
        RECT 32.390 295.720 32.470 296.000 ;
        RECT 33.310 295.720 33.390 296.000 ;
        RECT 34.230 295.720 34.310 296.000 ;
        RECT 35.150 295.720 35.230 296.000 ;
        RECT 36.070 295.720 36.150 296.000 ;
        RECT 36.990 295.720 37.070 296.000 ;
        RECT 37.910 295.720 37.990 296.000 ;
        RECT 38.830 295.720 38.910 296.000 ;
        RECT 39.750 295.720 39.830 296.000 ;
        RECT 40.670 295.720 40.750 296.000 ;
        RECT 41.590 295.720 41.670 296.000 ;
        RECT 42.510 295.720 42.590 296.000 ;
        RECT 43.430 295.720 43.510 296.000 ;
        RECT 44.350 295.720 44.430 296.000 ;
        RECT 45.270 295.720 45.350 296.000 ;
        RECT 46.190 295.720 46.270 296.000 ;
        RECT 47.110 295.720 47.190 296.000 ;
        RECT 48.030 295.720 48.110 296.000 ;
        RECT 48.950 295.720 49.030 296.000 ;
        RECT 49.870 295.720 49.950 296.000 ;
        RECT 50.790 295.720 50.870 296.000 ;
        RECT 51.710 295.720 51.790 296.000 ;
        RECT 52.630 295.720 52.710 296.000 ;
        RECT 53.550 295.720 53.630 296.000 ;
        RECT 54.470 295.720 54.550 296.000 ;
        RECT 55.390 295.720 55.470 296.000 ;
        RECT 56.310 295.720 56.390 296.000 ;
        RECT 57.230 295.720 57.310 296.000 ;
        RECT 58.150 295.720 58.230 296.000 ;
        RECT 59.070 295.720 59.150 296.000 ;
        RECT 59.990 295.720 60.070 296.000 ;
        RECT 60.910 295.720 60.990 296.000 ;
        RECT 61.830 295.720 61.910 296.000 ;
        RECT 62.750 295.720 62.830 296.000 ;
        RECT 63.670 295.720 63.750 296.000 ;
        RECT 64.590 295.720 64.670 296.000 ;
        RECT 65.510 295.720 65.590 296.000 ;
        RECT 66.430 295.720 66.510 296.000 ;
        RECT 67.350 295.720 67.430 296.000 ;
        RECT 68.270 295.720 68.350 296.000 ;
        RECT 69.190 295.720 69.270 296.000 ;
        RECT 70.110 295.720 70.190 296.000 ;
        RECT 71.030 295.720 71.110 296.000 ;
        RECT 71.950 295.720 72.030 296.000 ;
        RECT 72.870 295.720 72.950 296.000 ;
        RECT 73.790 295.720 73.870 296.000 ;
        RECT 74.710 295.720 74.790 296.000 ;
        RECT 75.630 295.720 75.710 296.000 ;
        RECT 76.550 295.720 76.630 296.000 ;
        RECT 77.470 295.720 77.550 296.000 ;
        RECT 78.390 295.720 78.470 296.000 ;
        RECT 79.310 295.720 79.390 296.000 ;
        RECT 80.230 295.720 80.310 296.000 ;
        RECT 81.150 295.720 81.230 296.000 ;
        RECT 82.070 295.720 82.150 296.000 ;
        RECT 82.990 295.720 83.070 296.000 ;
        RECT 83.910 295.720 83.990 296.000 ;
        RECT 84.830 295.720 84.910 296.000 ;
        RECT 85.750 295.720 85.830 296.000 ;
        RECT 86.670 295.720 86.750 296.000 ;
        RECT 87.590 295.720 87.670 296.000 ;
        RECT 88.510 295.720 88.590 296.000 ;
        RECT 89.430 295.720 89.510 296.000 ;
        RECT 90.350 295.720 90.430 296.000 ;
        RECT 91.270 295.720 91.350 296.000 ;
        RECT 92.190 295.720 92.270 296.000 ;
        RECT 93.110 295.720 93.190 296.000 ;
        RECT 94.030 295.720 94.110 296.000 ;
        RECT 94.950 295.720 95.030 296.000 ;
        RECT 95.870 295.720 95.950 296.000 ;
        RECT 96.790 295.720 96.870 296.000 ;
        RECT 97.710 295.720 97.790 296.000 ;
        RECT 98.630 295.720 98.710 296.000 ;
        RECT 99.550 295.720 99.630 296.000 ;
        RECT 100.470 295.720 100.550 296.000 ;
        RECT 101.390 295.720 101.470 296.000 ;
        RECT 102.310 295.720 102.390 296.000 ;
        RECT 103.230 295.720 103.310 296.000 ;
        RECT 104.150 295.720 104.230 296.000 ;
        RECT 105.070 295.720 105.150 296.000 ;
        RECT 105.990 295.720 106.070 296.000 ;
        RECT 106.910 295.720 106.990 296.000 ;
        RECT 107.830 295.720 107.910 296.000 ;
        RECT 108.750 295.720 108.830 296.000 ;
        RECT 109.670 295.720 109.750 296.000 ;
        RECT 110.590 295.720 110.670 296.000 ;
        RECT 111.510 295.720 111.590 296.000 ;
        RECT 112.430 295.720 112.510 296.000 ;
        RECT 113.350 295.720 113.430 296.000 ;
        RECT 114.270 295.720 114.350 296.000 ;
        RECT 115.190 295.720 115.270 296.000 ;
        RECT 116.110 295.720 116.190 296.000 ;
        RECT 117.030 295.720 117.110 296.000 ;
        RECT 117.950 295.720 118.030 296.000 ;
        RECT 118.870 295.720 118.950 296.000 ;
        RECT 119.790 295.720 119.870 296.000 ;
        RECT 120.710 295.720 120.790 296.000 ;
        RECT 121.630 295.720 121.710 296.000 ;
        RECT 122.550 295.720 122.630 296.000 ;
        RECT 123.470 295.720 123.550 296.000 ;
        RECT 124.390 295.720 124.470 296.000 ;
        RECT 125.310 295.720 125.390 296.000 ;
        RECT 126.230 295.720 126.310 296.000 ;
        RECT 127.150 295.720 127.230 296.000 ;
        RECT 128.070 295.720 128.150 296.000 ;
        RECT 128.990 295.720 129.070 296.000 ;
        RECT 129.910 295.720 129.990 296.000 ;
        RECT 130.830 295.720 130.910 296.000 ;
        RECT 131.750 295.720 131.830 296.000 ;
        RECT 132.670 295.720 132.750 296.000 ;
        RECT 133.590 295.720 133.670 296.000 ;
        RECT 134.510 295.720 134.590 296.000 ;
        RECT 135.430 295.720 135.510 296.000 ;
        RECT 136.350 295.720 136.430 296.000 ;
        RECT 137.270 295.720 137.350 296.000 ;
        RECT 138.190 295.720 138.270 296.000 ;
        RECT 139.110 295.720 139.190 296.000 ;
        RECT 140.030 295.720 140.110 296.000 ;
        RECT 140.950 295.720 141.030 296.000 ;
        RECT 141.870 295.720 141.950 296.000 ;
        RECT 142.790 295.720 142.870 296.000 ;
        RECT 143.710 295.720 143.790 296.000 ;
        RECT 144.630 295.720 144.710 296.000 ;
        RECT 145.550 295.720 145.630 296.000 ;
        RECT 146.470 295.720 146.550 296.000 ;
        RECT 147.390 295.720 147.470 296.000 ;
        RECT 148.310 295.720 148.390 296.000 ;
        RECT 149.230 295.720 149.310 296.000 ;
        RECT 150.150 295.720 150.230 296.000 ;
        RECT 151.070 295.720 151.150 296.000 ;
        RECT 151.990 295.720 152.070 296.000 ;
        RECT 152.910 295.720 152.990 296.000 ;
        RECT 153.830 295.720 153.910 296.000 ;
        RECT 154.750 295.720 154.830 296.000 ;
        RECT 155.670 295.720 155.750 296.000 ;
        RECT 156.590 295.720 156.670 296.000 ;
        RECT 157.510 295.720 157.590 296.000 ;
        RECT 158.430 295.720 158.510 296.000 ;
        RECT 159.350 295.720 159.430 296.000 ;
        RECT 160.270 295.720 160.350 296.000 ;
        RECT 161.190 295.720 161.270 296.000 ;
        RECT 162.110 295.720 162.190 296.000 ;
        RECT 163.030 295.720 163.110 296.000 ;
        RECT 163.950 295.720 164.030 296.000 ;
        RECT 164.870 295.720 164.950 296.000 ;
        RECT 165.790 295.720 165.870 296.000 ;
        RECT 166.710 295.720 166.790 296.000 ;
        RECT 167.630 295.720 167.710 296.000 ;
        RECT 168.550 295.720 168.630 296.000 ;
        RECT 169.470 295.720 169.550 296.000 ;
        RECT 170.390 295.720 170.470 296.000 ;
        RECT 171.310 295.720 171.390 296.000 ;
        RECT 172.230 295.720 172.310 296.000 ;
        RECT 173.150 295.720 173.230 296.000 ;
        RECT 174.070 295.720 174.150 296.000 ;
        RECT 174.990 295.720 175.070 296.000 ;
        RECT 175.910 295.720 175.990 296.000 ;
        RECT 176.830 295.720 176.910 296.000 ;
        RECT 177.750 295.720 177.830 296.000 ;
        RECT 178.670 295.720 178.750 296.000 ;
        RECT 179.590 295.720 179.670 296.000 ;
        RECT 180.510 295.720 180.590 296.000 ;
        RECT 181.430 295.720 181.510 296.000 ;
        RECT 182.350 295.720 182.430 296.000 ;
        RECT 183.270 295.720 183.350 296.000 ;
        RECT 184.190 295.720 184.270 296.000 ;
        RECT 185.110 295.720 185.190 296.000 ;
        RECT 186.030 295.720 186.110 296.000 ;
        RECT 186.950 295.720 187.030 296.000 ;
        RECT 187.870 295.720 187.950 296.000 ;
        RECT 188.790 295.720 188.870 296.000 ;
        RECT 189.710 295.720 189.790 296.000 ;
        RECT 190.630 295.720 190.710 296.000 ;
        RECT 191.550 295.720 191.630 296.000 ;
        RECT 192.470 295.720 192.550 296.000 ;
        RECT 193.390 295.720 193.470 296.000 ;
        RECT 194.310 295.720 194.390 296.000 ;
        RECT 195.230 295.720 195.310 296.000 ;
        RECT 196.150 295.720 196.230 296.000 ;
        RECT 197.070 295.720 197.150 296.000 ;
        RECT 197.990 295.720 198.070 296.000 ;
        RECT 198.910 295.720 198.990 296.000 ;
        RECT 199.830 295.720 199.910 296.000 ;
        RECT 200.750 295.720 200.830 296.000 ;
        RECT 201.670 295.720 201.750 296.000 ;
        RECT 202.590 295.720 202.670 296.000 ;
        RECT 203.510 295.720 203.590 296.000 ;
        RECT 204.430 295.720 204.510 296.000 ;
        RECT 205.350 295.720 205.430 296.000 ;
        RECT 206.270 295.720 206.350 296.000 ;
        RECT 207.190 295.720 207.270 296.000 ;
        RECT 208.110 295.720 208.190 296.000 ;
        RECT 209.030 295.720 209.110 296.000 ;
        RECT 209.950 295.720 210.030 296.000 ;
        RECT 210.870 295.720 210.950 296.000 ;
        RECT 211.790 295.720 211.870 296.000 ;
        RECT 212.710 295.720 212.790 296.000 ;
        RECT 213.630 295.720 213.710 296.000 ;
        RECT 214.550 295.720 214.630 296.000 ;
        RECT 215.470 295.720 215.550 296.000 ;
        RECT 216.390 295.720 216.470 296.000 ;
        RECT 217.310 295.720 217.390 296.000 ;
        RECT 218.230 295.720 218.310 296.000 ;
        RECT 219.150 295.720 219.230 296.000 ;
        RECT 220.070 295.720 220.150 296.000 ;
        RECT 220.990 295.720 221.070 296.000 ;
        RECT 221.910 295.720 221.990 296.000 ;
        RECT 222.830 295.720 222.910 296.000 ;
        RECT 223.750 295.720 223.830 296.000 ;
        RECT 224.670 295.720 224.750 296.000 ;
        RECT 225.590 295.720 225.670 296.000 ;
        RECT 226.510 295.720 226.590 296.000 ;
        RECT 227.430 295.720 227.510 296.000 ;
        RECT 228.350 295.720 228.430 296.000 ;
        RECT 229.270 295.720 229.350 296.000 ;
        RECT 230.190 295.720 230.270 296.000 ;
        RECT 231.110 295.720 231.190 296.000 ;
        RECT 232.030 295.720 232.110 296.000 ;
        RECT 232.950 295.720 233.030 296.000 ;
        RECT 233.870 295.720 233.950 296.000 ;
        RECT 234.790 295.720 234.870 296.000 ;
        RECT 235.710 295.720 235.790 296.000 ;
        RECT 236.630 295.720 236.710 296.000 ;
        RECT 237.550 295.720 237.630 296.000 ;
        RECT 238.470 295.720 238.550 296.000 ;
        RECT 239.390 295.720 239.470 296.000 ;
        RECT 240.310 295.720 240.390 296.000 ;
        RECT 241.230 295.720 241.310 296.000 ;
        RECT 242.150 295.720 242.230 296.000 ;
        RECT 243.070 295.720 243.150 296.000 ;
        RECT 243.990 295.720 244.070 296.000 ;
        RECT 244.910 295.720 244.990 296.000 ;
        RECT 245.830 295.720 245.910 296.000 ;
        RECT 246.750 295.720 246.830 296.000 ;
        RECT 247.670 295.720 247.750 296.000 ;
        RECT 248.590 295.720 248.670 296.000 ;
        RECT 249.510 295.720 249.590 296.000 ;
        RECT 250.430 295.720 250.510 296.000 ;
        RECT 251.350 295.720 251.430 296.000 ;
        RECT 252.270 295.720 252.350 296.000 ;
        RECT 253.190 295.720 253.270 296.000 ;
        RECT 254.110 295.720 254.190 296.000 ;
        RECT 255.030 295.720 255.110 296.000 ;
        RECT 255.950 295.720 256.030 296.000 ;
        RECT 256.870 295.720 256.950 296.000 ;
        RECT 257.790 295.720 257.870 296.000 ;
        RECT 258.710 295.720 258.790 296.000 ;
        RECT 259.630 295.720 259.710 296.000 ;
        RECT 260.550 295.720 260.630 296.000 ;
        RECT 261.470 295.720 261.550 296.000 ;
        RECT 262.390 295.720 262.470 296.000 ;
        RECT 263.310 295.720 263.390 296.000 ;
        RECT 264.230 295.720 264.310 296.000 ;
        RECT 265.150 295.720 265.230 296.000 ;
        RECT 266.070 295.720 266.150 296.000 ;
        RECT 266.990 295.720 267.070 296.000 ;
        RECT 267.910 295.720 267.990 296.000 ;
        RECT 268.830 295.720 268.910 296.000 ;
        RECT 269.750 295.720 269.830 296.000 ;
        RECT 270.670 295.720 270.750 296.000 ;
        RECT 271.590 295.720 271.670 296.000 ;
        RECT 272.510 295.720 272.590 296.000 ;
        RECT 273.430 295.720 273.510 296.000 ;
        RECT 274.350 295.720 274.430 296.000 ;
        RECT 275.270 295.720 275.350 296.000 ;
        RECT 276.190 295.720 276.270 296.000 ;
        RECT 277.110 295.720 277.190 296.000 ;
        RECT 278.030 295.720 278.110 296.000 ;
        RECT 278.950 295.720 279.030 296.000 ;
        RECT 279.870 295.720 279.950 296.000 ;
        RECT 280.790 295.720 280.870 296.000 ;
        RECT 281.710 295.720 281.790 296.000 ;
        RECT 282.630 295.720 282.710 296.000 ;
        RECT 283.550 295.720 283.630 296.000 ;
        RECT 284.470 295.720 284.550 296.000 ;
        RECT 285.390 295.720 285.470 296.000 ;
        RECT 286.310 295.720 286.390 296.000 ;
        RECT 287.230 295.720 287.310 296.000 ;
        RECT 288.150 295.720 288.230 296.000 ;
        RECT 289.070 295.720 289.150 296.000 ;
        RECT 289.990 295.720 290.070 296.000 ;
        RECT 290.910 295.720 290.990 296.000 ;
        RECT 291.830 295.720 291.910 296.000 ;
        RECT 292.750 295.720 292.830 296.000 ;
        RECT 293.670 295.720 293.750 296.000 ;
        RECT 294.590 295.720 294.670 296.000 ;
        RECT 295.510 295.720 295.590 296.000 ;
        RECT 296.430 295.720 296.510 296.000 ;
        RECT 297.350 295.720 297.430 296.000 ;
        RECT 298.270 295.720 298.350 296.000 ;
        RECT 299.190 295.720 299.270 296.000 ;
        RECT 300.110 295.720 300.190 296.000 ;
        RECT 301.030 295.720 301.110 296.000 ;
        RECT 301.950 295.720 302.030 296.000 ;
        RECT 302.870 295.720 302.950 296.000 ;
        RECT 303.790 295.720 303.870 296.000 ;
        RECT 304.710 295.720 304.790 296.000 ;
        RECT 305.630 295.720 305.710 296.000 ;
        RECT 306.550 295.720 306.630 296.000 ;
        RECT 307.470 295.720 307.550 296.000 ;
        RECT 308.390 295.720 308.470 296.000 ;
        RECT 309.310 295.720 309.390 296.000 ;
        RECT 310.230 295.720 310.310 296.000 ;
        RECT 311.150 295.720 311.230 296.000 ;
        RECT 312.070 295.720 312.150 296.000 ;
        RECT 312.990 295.720 313.070 296.000 ;
        RECT 313.910 295.720 313.990 296.000 ;
        RECT 314.830 295.720 314.910 296.000 ;
        RECT 315.750 295.720 315.830 296.000 ;
        RECT 316.670 295.720 316.750 296.000 ;
        RECT 317.590 295.720 317.670 296.000 ;
        RECT 318.510 295.720 318.590 296.000 ;
        RECT 319.430 295.720 319.510 296.000 ;
        RECT 320.350 295.720 320.430 296.000 ;
        RECT 321.270 295.720 321.350 296.000 ;
        RECT 322.190 295.720 322.270 296.000 ;
        RECT 323.110 295.720 323.190 296.000 ;
        RECT 324.030 295.720 324.110 296.000 ;
        RECT 324.950 295.720 325.030 296.000 ;
        RECT 325.870 295.720 325.950 296.000 ;
        RECT 326.790 295.720 326.870 296.000 ;
        RECT 327.710 295.720 327.790 296.000 ;
        RECT 328.630 295.720 328.710 296.000 ;
        RECT 329.550 295.720 329.630 296.000 ;
        RECT 330.470 295.720 330.550 296.000 ;
        RECT 331.390 295.720 331.470 296.000 ;
        RECT 332.310 295.720 332.390 296.000 ;
        RECT 333.230 295.720 333.310 296.000 ;
        RECT 334.150 295.720 334.230 296.000 ;
        RECT 335.070 295.720 335.150 296.000 ;
        RECT 335.990 295.720 336.070 296.000 ;
        RECT 336.910 295.720 336.990 296.000 ;
        RECT 337.830 295.720 337.910 296.000 ;
        RECT 338.750 295.720 338.830 296.000 ;
        RECT 339.670 295.720 339.750 296.000 ;
        RECT 340.590 295.720 340.670 296.000 ;
        RECT 341.510 295.720 341.590 296.000 ;
        RECT 342.430 295.720 342.510 296.000 ;
        RECT 343.350 295.720 343.430 296.000 ;
        RECT 344.270 295.720 344.350 296.000 ;
        RECT 345.190 295.720 345.270 296.000 ;
        RECT 346.110 295.720 346.190 296.000 ;
        RECT 347.030 295.720 347.110 296.000 ;
        RECT 347.950 295.720 348.030 296.000 ;
        RECT 348.870 295.720 348.950 296.000 ;
        RECT 349.790 295.720 349.870 296.000 ;
        RECT 350.710 295.720 350.790 296.000 ;
        RECT 351.630 295.720 351.710 296.000 ;
        RECT 352.550 295.720 352.630 296.000 ;
        RECT 353.470 295.720 353.550 296.000 ;
        RECT 354.390 295.720 354.470 296.000 ;
        RECT 355.310 295.720 355.390 296.000 ;
        RECT 356.230 295.720 356.310 296.000 ;
        RECT 357.150 295.720 357.230 296.000 ;
        RECT 358.070 295.720 358.150 296.000 ;
        RECT 358.990 295.720 359.070 296.000 ;
        RECT 359.910 295.720 359.990 296.000 ;
        RECT 360.830 295.720 360.910 296.000 ;
        RECT 361.750 295.720 361.830 296.000 ;
        RECT 362.670 295.720 362.750 296.000 ;
        RECT 363.590 295.720 363.670 296.000 ;
        RECT 364.510 295.720 364.590 296.000 ;
        RECT 365.430 295.720 365.510 296.000 ;
        RECT 366.350 295.720 366.430 296.000 ;
        RECT 367.270 295.720 367.350 296.000 ;
        RECT 368.190 295.720 368.270 296.000 ;
        RECT 369.110 295.720 369.190 296.000 ;
        RECT 370.030 295.720 370.110 296.000 ;
        RECT 370.950 295.720 371.030 296.000 ;
        RECT 371.870 295.720 371.950 296.000 ;
        RECT 372.790 295.720 372.870 296.000 ;
        RECT 373.710 295.720 373.790 296.000 ;
        RECT 374.630 295.720 374.710 296.000 ;
        RECT 375.550 295.720 375.630 296.000 ;
        RECT 376.470 295.720 376.550 296.000 ;
        RECT 377.390 295.720 377.470 296.000 ;
        RECT 378.310 295.720 378.390 296.000 ;
        RECT 379.230 295.720 379.310 296.000 ;
        RECT 380.150 295.720 380.230 296.000 ;
        RECT 381.070 295.720 381.150 296.000 ;
        RECT 381.990 295.720 382.070 296.000 ;
        RECT 382.910 295.720 382.990 296.000 ;
        RECT 383.830 295.720 383.910 296.000 ;
        RECT 384.750 295.720 384.830 296.000 ;
        RECT 385.670 295.720 385.750 296.000 ;
        RECT 386.590 295.720 386.670 296.000 ;
        RECT 387.510 295.720 387.590 296.000 ;
        RECT 388.430 295.720 388.510 296.000 ;
        RECT 389.350 295.720 389.430 296.000 ;
        RECT 390.270 295.720 390.350 296.000 ;
        RECT 391.190 295.720 391.270 296.000 ;
        RECT 392.110 295.720 392.190 296.000 ;
        RECT 393.030 295.720 393.110 296.000 ;
        RECT 393.950 295.720 394.030 296.000 ;
        RECT 394.870 295.720 394.950 296.000 ;
        RECT 395.790 295.720 395.870 296.000 ;
        RECT 396.710 295.720 396.790 296.000 ;
        RECT 397.630 295.720 397.710 296.000 ;
        RECT 398.550 295.720 398.630 296.000 ;
        RECT 399.470 295.720 399.550 296.000 ;
        RECT 400.390 295.720 400.470 296.000 ;
        RECT 401.310 295.720 401.390 296.000 ;
        RECT 402.230 295.720 402.310 296.000 ;
        RECT 403.150 295.720 403.230 296.000 ;
        RECT 404.070 295.720 404.150 296.000 ;
        RECT 404.990 295.720 405.070 296.000 ;
        RECT 405.910 295.720 405.990 296.000 ;
        RECT 406.830 295.720 406.910 296.000 ;
        RECT 407.750 295.720 407.830 296.000 ;
        RECT 408.670 295.720 408.750 296.000 ;
        RECT 409.590 295.720 409.670 296.000 ;
        RECT 410.510 295.720 410.590 296.000 ;
        RECT 411.430 295.720 411.510 296.000 ;
        RECT 412.350 295.720 412.430 296.000 ;
        RECT 413.270 295.720 413.350 296.000 ;
        RECT 414.190 295.720 414.270 296.000 ;
        RECT 415.110 295.720 415.190 296.000 ;
        RECT 416.030 295.720 416.110 296.000 ;
        RECT 416.950 295.720 417.030 296.000 ;
        RECT 417.870 295.720 417.950 296.000 ;
        RECT 418.790 295.720 418.870 296.000 ;
        RECT 419.710 295.720 419.790 296.000 ;
        RECT 420.630 295.720 420.710 296.000 ;
        RECT 421.550 295.720 421.630 296.000 ;
        RECT 422.470 295.720 422.550 296.000 ;
        RECT 423.390 295.720 423.470 296.000 ;
        RECT 424.310 295.720 424.390 296.000 ;
        RECT 425.230 295.720 425.310 296.000 ;
        RECT 426.150 295.720 426.230 296.000 ;
        RECT 427.070 295.720 427.150 296.000 ;
        RECT 427.990 295.720 428.070 296.000 ;
        RECT 428.910 295.720 428.990 296.000 ;
        RECT 429.830 295.720 429.910 296.000 ;
        RECT 430.750 295.720 430.830 296.000 ;
        RECT 431.670 295.720 431.750 296.000 ;
        RECT 432.590 295.720 432.670 296.000 ;
        RECT 433.510 295.720 433.590 296.000 ;
        RECT 434.430 295.720 434.510 296.000 ;
        RECT 435.350 295.720 435.430 296.000 ;
        RECT 436.270 295.720 436.350 296.000 ;
        RECT 437.190 295.720 437.270 296.000 ;
        RECT 438.110 295.720 438.190 296.000 ;
        RECT 439.030 295.720 439.110 296.000 ;
        RECT 439.950 295.720 440.030 296.000 ;
        RECT 440.870 295.720 440.950 296.000 ;
        RECT 441.790 295.720 441.870 296.000 ;
        RECT 442.710 295.720 442.790 296.000 ;
        RECT 443.630 295.720 443.710 296.000 ;
        RECT 444.550 295.720 444.630 296.000 ;
        RECT 445.470 295.720 445.550 296.000 ;
        RECT 446.390 295.720 446.470 296.000 ;
        RECT 447.310 295.720 447.390 296.000 ;
        RECT 448.230 295.720 448.310 296.000 ;
        RECT 449.150 295.720 449.230 296.000 ;
        RECT 450.070 295.720 450.150 296.000 ;
        RECT 450.990 295.720 451.070 296.000 ;
        RECT 451.910 295.720 451.990 296.000 ;
        RECT 452.830 295.720 452.910 296.000 ;
        RECT 453.750 295.720 453.830 296.000 ;
        RECT 454.670 295.720 454.750 296.000 ;
        RECT 455.590 295.720 455.670 296.000 ;
        RECT 456.510 295.720 456.590 296.000 ;
        RECT 457.430 295.720 457.510 296.000 ;
        RECT 458.350 295.720 458.430 296.000 ;
        RECT 459.270 295.720 459.350 296.000 ;
        RECT 460.190 295.720 460.270 296.000 ;
        RECT 461.110 295.720 461.190 296.000 ;
        RECT 462.030 295.720 462.110 296.000 ;
        RECT 462.950 295.720 463.030 296.000 ;
        RECT 463.870 295.720 463.950 296.000 ;
        RECT 464.790 295.720 464.870 296.000 ;
        RECT 465.710 295.720 465.790 296.000 ;
        RECT 466.630 295.720 466.710 296.000 ;
        RECT 467.550 295.720 467.630 296.000 ;
        RECT 468.470 295.720 468.550 296.000 ;
        RECT 469.390 295.720 469.470 296.000 ;
        RECT 470.310 295.720 470.390 296.000 ;
        RECT 471.230 295.720 471.310 296.000 ;
        RECT 472.150 295.720 472.230 296.000 ;
        RECT 473.070 295.720 473.150 296.000 ;
        RECT 473.990 295.720 474.070 296.000 ;
        RECT 474.910 295.720 474.990 296.000 ;
        RECT 475.830 295.720 475.910 296.000 ;
        RECT 476.750 295.720 476.830 296.000 ;
        RECT 477.670 295.720 477.750 296.000 ;
        RECT 478.590 295.720 478.670 296.000 ;
        RECT 479.510 295.720 479.590 296.000 ;
        RECT 480.430 295.720 480.510 296.000 ;
        RECT 481.350 295.720 481.430 296.000 ;
        RECT 482.270 295.720 482.350 296.000 ;
        RECT 483.190 295.720 483.270 296.000 ;
        RECT 484.110 295.720 484.190 296.000 ;
        RECT 485.030 295.720 485.110 296.000 ;
        RECT 485.950 295.720 486.030 296.000 ;
        RECT 486.870 295.720 486.950 296.000 ;
        RECT 487.790 295.720 487.870 296.000 ;
        RECT 488.710 295.720 488.790 296.000 ;
        RECT 489.630 295.720 489.710 296.000 ;
        RECT 490.550 295.720 490.630 296.000 ;
        RECT 491.470 295.720 491.550 296.000 ;
        RECT 492.390 295.720 492.470 296.000 ;
        RECT 493.310 295.720 493.390 296.000 ;
        RECT 494.230 295.720 494.310 296.000 ;
        RECT 495.150 295.720 495.230 296.000 ;
        RECT 496.070 295.720 496.150 296.000 ;
        RECT 496.990 295.720 497.070 296.000 ;
        RECT 497.910 295.720 497.990 296.000 ;
        RECT 498.830 295.720 498.910 296.000 ;
        RECT 499.750 295.720 499.830 296.000 ;
        RECT 500.670 295.720 500.750 296.000 ;
        RECT 501.590 295.720 501.670 296.000 ;
        RECT 502.510 295.720 502.590 296.000 ;
        RECT 503.430 295.720 503.510 296.000 ;
        RECT 504.350 295.720 504.430 296.000 ;
        RECT 505.270 295.720 505.350 296.000 ;
        RECT 506.190 295.720 506.270 296.000 ;
        RECT 507.110 295.720 507.190 296.000 ;
        RECT 508.030 295.720 508.110 296.000 ;
        RECT 508.950 295.720 509.030 296.000 ;
        RECT 509.870 295.720 509.950 296.000 ;
        RECT 510.790 295.720 510.870 296.000 ;
        RECT 511.710 295.720 511.790 296.000 ;
        RECT 512.630 295.720 512.710 296.000 ;
        RECT 513.550 295.720 513.630 296.000 ;
        RECT 514.470 295.720 514.550 296.000 ;
        RECT 515.390 295.720 515.470 296.000 ;
        RECT 516.310 295.720 516.390 296.000 ;
        RECT 517.230 295.720 517.310 296.000 ;
        RECT 518.150 295.720 518.230 296.000 ;
        RECT 519.070 295.720 519.150 296.000 ;
        RECT 519.990 295.720 520.070 296.000 ;
        RECT 520.910 295.720 520.990 296.000 ;
        RECT 521.830 295.720 521.910 296.000 ;
        RECT 522.750 295.720 522.830 296.000 ;
        RECT 523.670 295.720 523.750 296.000 ;
        RECT 524.590 295.720 524.670 296.000 ;
        RECT 525.510 295.720 525.590 296.000 ;
        RECT 526.430 295.720 526.510 296.000 ;
        RECT 527.350 295.720 527.430 296.000 ;
        RECT 528.270 295.720 528.350 296.000 ;
        RECT 529.190 295.720 529.270 296.000 ;
        RECT 530.110 295.720 530.190 296.000 ;
        RECT 531.030 295.720 531.110 296.000 ;
        RECT 531.950 295.720 532.030 296.000 ;
        RECT 532.870 295.720 532.950 296.000 ;
        RECT 533.790 295.720 533.870 296.000 ;
        RECT 534.710 295.720 534.790 296.000 ;
        RECT 535.630 295.720 535.710 296.000 ;
        RECT 536.550 295.720 536.630 296.000 ;
        RECT 537.470 295.720 537.550 296.000 ;
        RECT 538.390 295.720 538.470 296.000 ;
        RECT 539.310 295.720 539.390 296.000 ;
        RECT 540.230 295.720 540.310 296.000 ;
        RECT 541.150 295.720 541.230 296.000 ;
        RECT 542.070 295.720 542.150 296.000 ;
        RECT 542.990 295.720 543.070 296.000 ;
        RECT 543.910 295.720 543.990 296.000 ;
        RECT 544.830 295.720 544.910 296.000 ;
        RECT 545.750 295.720 545.830 296.000 ;
        RECT 546.670 295.720 546.750 296.000 ;
        RECT 547.590 295.720 547.670 296.000 ;
        RECT 548.510 295.720 548.590 296.000 ;
        RECT 549.430 295.720 549.510 296.000 ;
        RECT 550.350 295.720 550.430 296.000 ;
        RECT 551.270 295.720 551.350 296.000 ;
        RECT 552.190 295.720 552.270 296.000 ;
        RECT 553.110 295.720 553.190 296.000 ;
        RECT 554.030 295.720 554.110 296.000 ;
        RECT 554.950 295.720 555.030 296.000 ;
        RECT 555.870 295.720 555.950 296.000 ;
        RECT 556.790 295.720 556.870 296.000 ;
        RECT 557.710 295.720 557.790 296.000 ;
        RECT 558.630 295.720 558.710 296.000 ;
        RECT 559.550 295.720 559.630 296.000 ;
        RECT 560.470 295.720 560.550 296.000 ;
        RECT 561.390 295.720 561.470 296.000 ;
        RECT 562.310 295.720 562.390 296.000 ;
        RECT 563.230 295.720 563.310 296.000 ;
        RECT 564.150 295.720 564.230 296.000 ;
        RECT 565.070 295.720 565.150 296.000 ;
        RECT 565.990 295.720 566.070 296.000 ;
        RECT 566.910 295.720 566.990 296.000 ;
        RECT 567.830 295.720 567.910 296.000 ;
        RECT 568.750 295.720 568.830 296.000 ;
        RECT 569.670 295.720 569.750 296.000 ;
        RECT 570.590 295.720 570.670 296.000 ;
        RECT 571.510 295.720 571.590 296.000 ;
        RECT 572.430 295.720 572.510 296.000 ;
        RECT 573.350 295.720 573.430 296.000 ;
        RECT 574.270 295.720 574.350 296.000 ;
        RECT 575.190 295.720 575.270 296.000 ;
        RECT 576.110 295.720 576.190 296.000 ;
        RECT 577.030 295.720 577.110 296.000 ;
        RECT 577.950 295.720 578.030 296.000 ;
        RECT 578.870 295.720 578.950 296.000 ;
        RECT 579.790 295.720 579.870 296.000 ;
        RECT 580.710 295.720 580.790 296.000 ;
        RECT 581.630 295.720 581.710 296.000 ;
        RECT 582.550 295.720 582.630 296.000 ;
        RECT 583.470 295.720 583.550 296.000 ;
        RECT 584.390 295.720 599.740 296.000 ;
        RECT 4.690 4.280 599.740 295.720 ;
        RECT 4.690 3.670 13.610 4.280 ;
        RECT 14.450 3.670 16.370 4.280 ;
        RECT 17.210 3.670 19.130 4.280 ;
        RECT 19.970 3.670 21.890 4.280 ;
        RECT 22.730 3.670 24.650 4.280 ;
        RECT 25.490 3.670 27.410 4.280 ;
        RECT 28.250 3.670 30.170 4.280 ;
        RECT 31.010 3.670 32.930 4.280 ;
        RECT 33.770 3.670 35.690 4.280 ;
        RECT 36.530 3.670 38.450 4.280 ;
        RECT 39.290 3.670 41.210 4.280 ;
        RECT 42.050 3.670 43.970 4.280 ;
        RECT 44.810 3.670 46.730 4.280 ;
        RECT 47.570 3.670 49.490 4.280 ;
        RECT 50.330 3.670 52.250 4.280 ;
        RECT 53.090 3.670 55.010 4.280 ;
        RECT 55.850 3.670 57.770 4.280 ;
        RECT 58.610 3.670 60.530 4.280 ;
        RECT 61.370 3.670 63.290 4.280 ;
        RECT 64.130 3.670 66.050 4.280 ;
        RECT 66.890 3.670 68.810 4.280 ;
        RECT 69.650 3.670 71.570 4.280 ;
        RECT 72.410 3.670 74.330 4.280 ;
        RECT 75.170 3.670 77.090 4.280 ;
        RECT 77.930 3.670 79.850 4.280 ;
        RECT 80.690 3.670 82.610 4.280 ;
        RECT 83.450 3.670 85.370 4.280 ;
        RECT 86.210 3.670 88.130 4.280 ;
        RECT 88.970 3.670 90.890 4.280 ;
        RECT 91.730 3.670 93.650 4.280 ;
        RECT 94.490 3.670 96.410 4.280 ;
        RECT 97.250 3.670 99.170 4.280 ;
        RECT 100.010 3.670 101.930 4.280 ;
        RECT 102.770 3.670 104.690 4.280 ;
        RECT 105.530 3.670 107.450 4.280 ;
        RECT 108.290 3.670 110.210 4.280 ;
        RECT 111.050 3.670 112.970 4.280 ;
        RECT 113.810 3.670 115.730 4.280 ;
        RECT 116.570 3.670 118.490 4.280 ;
        RECT 119.330 3.670 121.250 4.280 ;
        RECT 122.090 3.670 124.010 4.280 ;
        RECT 124.850 3.670 126.770 4.280 ;
        RECT 127.610 3.670 129.530 4.280 ;
        RECT 130.370 3.670 132.290 4.280 ;
        RECT 133.130 3.670 135.050 4.280 ;
        RECT 135.890 3.670 137.810 4.280 ;
        RECT 138.650 3.670 140.570 4.280 ;
        RECT 141.410 3.670 143.330 4.280 ;
        RECT 144.170 3.670 146.090 4.280 ;
        RECT 146.930 3.670 148.850 4.280 ;
        RECT 149.690 3.670 151.610 4.280 ;
        RECT 152.450 3.670 154.370 4.280 ;
        RECT 155.210 3.670 157.130 4.280 ;
        RECT 157.970 3.670 159.890 4.280 ;
        RECT 160.730 3.670 162.650 4.280 ;
        RECT 163.490 3.670 165.410 4.280 ;
        RECT 166.250 3.670 168.170 4.280 ;
        RECT 169.010 3.670 170.930 4.280 ;
        RECT 171.770 3.670 173.690 4.280 ;
        RECT 174.530 3.670 176.450 4.280 ;
        RECT 177.290 3.670 179.210 4.280 ;
        RECT 180.050 3.670 181.970 4.280 ;
        RECT 182.810 3.670 184.730 4.280 ;
        RECT 185.570 3.670 187.490 4.280 ;
        RECT 188.330 3.670 190.250 4.280 ;
        RECT 191.090 3.670 193.010 4.280 ;
        RECT 193.850 3.670 195.770 4.280 ;
        RECT 196.610 3.670 198.530 4.280 ;
        RECT 199.370 3.670 201.290 4.280 ;
        RECT 202.130 3.670 204.050 4.280 ;
        RECT 204.890 3.670 206.810 4.280 ;
        RECT 207.650 3.670 209.570 4.280 ;
        RECT 210.410 3.670 212.330 4.280 ;
        RECT 213.170 3.670 215.090 4.280 ;
        RECT 215.930 3.670 217.850 4.280 ;
        RECT 218.690 3.670 220.610 4.280 ;
        RECT 221.450 3.670 223.370 4.280 ;
        RECT 224.210 3.670 226.130 4.280 ;
        RECT 226.970 3.670 228.890 4.280 ;
        RECT 229.730 3.670 231.650 4.280 ;
        RECT 232.490 3.670 234.410 4.280 ;
        RECT 235.250 3.670 237.170 4.280 ;
        RECT 238.010 3.670 239.930 4.280 ;
        RECT 240.770 3.670 242.690 4.280 ;
        RECT 243.530 3.670 245.450 4.280 ;
        RECT 246.290 3.670 248.210 4.280 ;
        RECT 249.050 3.670 250.970 4.280 ;
        RECT 251.810 3.670 253.730 4.280 ;
        RECT 254.570 3.670 256.490 4.280 ;
        RECT 257.330 3.670 259.250 4.280 ;
        RECT 260.090 3.670 262.010 4.280 ;
        RECT 262.850 3.670 264.770 4.280 ;
        RECT 265.610 3.670 267.530 4.280 ;
        RECT 268.370 3.670 270.290 4.280 ;
        RECT 271.130 3.670 273.050 4.280 ;
        RECT 273.890 3.670 275.810 4.280 ;
        RECT 276.650 3.670 278.570 4.280 ;
        RECT 279.410 3.670 281.330 4.280 ;
        RECT 282.170 3.670 284.090 4.280 ;
        RECT 284.930 3.670 286.850 4.280 ;
        RECT 287.690 3.670 289.610 4.280 ;
        RECT 290.450 3.670 292.370 4.280 ;
        RECT 293.210 3.670 295.130 4.280 ;
        RECT 295.970 3.670 297.890 4.280 ;
        RECT 298.730 3.670 300.650 4.280 ;
        RECT 301.490 3.670 303.410 4.280 ;
        RECT 304.250 3.670 306.170 4.280 ;
        RECT 307.010 3.670 308.930 4.280 ;
        RECT 309.770 3.670 311.690 4.280 ;
        RECT 312.530 3.670 314.450 4.280 ;
        RECT 315.290 3.670 317.210 4.280 ;
        RECT 318.050 3.670 319.970 4.280 ;
        RECT 320.810 3.670 322.730 4.280 ;
        RECT 323.570 3.670 325.490 4.280 ;
        RECT 326.330 3.670 328.250 4.280 ;
        RECT 329.090 3.670 331.010 4.280 ;
        RECT 331.850 3.670 333.770 4.280 ;
        RECT 334.610 3.670 336.530 4.280 ;
        RECT 337.370 3.670 339.290 4.280 ;
        RECT 340.130 3.670 342.050 4.280 ;
        RECT 342.890 3.670 344.810 4.280 ;
        RECT 345.650 3.670 347.570 4.280 ;
        RECT 348.410 3.670 350.330 4.280 ;
        RECT 351.170 3.670 353.090 4.280 ;
        RECT 353.930 3.670 355.850 4.280 ;
        RECT 356.690 3.670 358.610 4.280 ;
        RECT 359.450 3.670 361.370 4.280 ;
        RECT 362.210 3.670 364.130 4.280 ;
        RECT 364.970 3.670 366.890 4.280 ;
        RECT 367.730 3.670 369.650 4.280 ;
        RECT 370.490 3.670 372.410 4.280 ;
        RECT 373.250 3.670 375.170 4.280 ;
        RECT 376.010 3.670 377.930 4.280 ;
        RECT 378.770 3.670 380.690 4.280 ;
        RECT 381.530 3.670 383.450 4.280 ;
        RECT 384.290 3.670 386.210 4.280 ;
        RECT 387.050 3.670 388.970 4.280 ;
        RECT 389.810 3.670 391.730 4.280 ;
        RECT 392.570 3.670 394.490 4.280 ;
        RECT 395.330 3.670 397.250 4.280 ;
        RECT 398.090 3.670 400.010 4.280 ;
        RECT 400.850 3.670 402.770 4.280 ;
        RECT 403.610 3.670 405.530 4.280 ;
        RECT 406.370 3.670 408.290 4.280 ;
        RECT 409.130 3.670 411.050 4.280 ;
        RECT 411.890 3.670 413.810 4.280 ;
        RECT 414.650 3.670 416.570 4.280 ;
        RECT 417.410 3.670 419.330 4.280 ;
        RECT 420.170 3.670 422.090 4.280 ;
        RECT 422.930 3.670 424.850 4.280 ;
        RECT 425.690 3.670 427.610 4.280 ;
        RECT 428.450 3.670 430.370 4.280 ;
        RECT 431.210 3.670 433.130 4.280 ;
        RECT 433.970 3.670 435.890 4.280 ;
        RECT 436.730 3.670 438.650 4.280 ;
        RECT 439.490 3.670 441.410 4.280 ;
        RECT 442.250 3.670 444.170 4.280 ;
        RECT 445.010 3.670 446.930 4.280 ;
        RECT 447.770 3.670 449.690 4.280 ;
        RECT 450.530 3.670 452.450 4.280 ;
        RECT 453.290 3.670 455.210 4.280 ;
        RECT 456.050 3.670 457.970 4.280 ;
        RECT 458.810 3.670 460.730 4.280 ;
        RECT 461.570 3.670 463.490 4.280 ;
        RECT 464.330 3.670 466.250 4.280 ;
        RECT 467.090 3.670 469.010 4.280 ;
        RECT 469.850 3.670 471.770 4.280 ;
        RECT 472.610 3.670 474.530 4.280 ;
        RECT 475.370 3.670 477.290 4.280 ;
        RECT 478.130 3.670 480.050 4.280 ;
        RECT 480.890 3.670 482.810 4.280 ;
        RECT 483.650 3.670 485.570 4.280 ;
        RECT 486.410 3.670 488.330 4.280 ;
        RECT 489.170 3.670 491.090 4.280 ;
        RECT 491.930 3.670 493.850 4.280 ;
        RECT 494.690 3.670 496.610 4.280 ;
        RECT 497.450 3.670 499.370 4.280 ;
        RECT 500.210 3.670 502.130 4.280 ;
        RECT 502.970 3.670 504.890 4.280 ;
        RECT 505.730 3.670 507.650 4.280 ;
        RECT 508.490 3.670 510.410 4.280 ;
        RECT 511.250 3.670 513.170 4.280 ;
        RECT 514.010 3.670 515.930 4.280 ;
        RECT 516.770 3.670 518.690 4.280 ;
        RECT 519.530 3.670 521.450 4.280 ;
        RECT 522.290 3.670 524.210 4.280 ;
        RECT 525.050 3.670 526.970 4.280 ;
        RECT 527.810 3.670 529.730 4.280 ;
        RECT 530.570 3.670 532.490 4.280 ;
        RECT 533.330 3.670 535.250 4.280 ;
        RECT 536.090 3.670 538.010 4.280 ;
        RECT 538.850 3.670 540.770 4.280 ;
        RECT 541.610 3.670 543.530 4.280 ;
        RECT 544.370 3.670 546.290 4.280 ;
        RECT 547.130 3.670 549.050 4.280 ;
        RECT 549.890 3.670 551.810 4.280 ;
        RECT 552.650 3.670 554.570 4.280 ;
        RECT 555.410 3.670 557.330 4.280 ;
        RECT 558.170 3.670 560.090 4.280 ;
        RECT 560.930 3.670 562.850 4.280 ;
        RECT 563.690 3.670 565.610 4.280 ;
        RECT 566.450 3.670 568.370 4.280 ;
        RECT 569.210 3.670 571.130 4.280 ;
        RECT 571.970 3.670 573.890 4.280 ;
        RECT 574.730 3.670 576.650 4.280 ;
        RECT 577.490 3.670 579.410 4.280 ;
        RECT 580.250 3.670 582.170 4.280 ;
        RECT 583.010 3.670 584.930 4.280 ;
        RECT 585.770 3.670 599.740 4.280 ;
      LAYER met3 ;
        RECT 3.990 289.360 596.000 291.545 ;
        RECT 4.400 287.960 595.600 289.360 ;
        RECT 3.990 286.640 595.600 287.960 ;
        RECT 4.400 285.240 595.600 286.640 ;
        RECT 3.990 283.920 595.600 285.240 ;
        RECT 4.400 282.520 595.600 283.920 ;
        RECT 3.990 281.200 595.600 282.520 ;
        RECT 4.400 279.800 595.600 281.200 ;
        RECT 3.990 278.480 595.600 279.800 ;
        RECT 4.400 277.080 595.600 278.480 ;
        RECT 3.990 275.760 595.600 277.080 ;
        RECT 4.400 274.360 595.600 275.760 ;
        RECT 3.990 273.040 595.600 274.360 ;
        RECT 4.400 271.640 595.600 273.040 ;
        RECT 3.990 270.320 595.600 271.640 ;
        RECT 4.400 268.920 595.600 270.320 ;
        RECT 3.990 267.600 595.600 268.920 ;
        RECT 4.400 266.200 595.600 267.600 ;
        RECT 3.990 264.880 595.600 266.200 ;
        RECT 4.400 263.480 595.600 264.880 ;
        RECT 3.990 262.160 595.600 263.480 ;
        RECT 4.400 260.760 595.600 262.160 ;
        RECT 3.990 259.440 595.600 260.760 ;
        RECT 4.400 258.040 595.600 259.440 ;
        RECT 3.990 256.720 595.600 258.040 ;
        RECT 4.400 255.320 595.600 256.720 ;
        RECT 3.990 254.000 595.600 255.320 ;
        RECT 4.400 252.600 595.600 254.000 ;
        RECT 3.990 251.280 595.600 252.600 ;
        RECT 4.400 249.880 595.600 251.280 ;
        RECT 3.990 248.560 595.600 249.880 ;
        RECT 4.400 247.160 595.600 248.560 ;
        RECT 3.990 245.840 595.600 247.160 ;
        RECT 4.400 244.440 595.600 245.840 ;
        RECT 3.990 243.120 595.600 244.440 ;
        RECT 4.400 241.720 595.600 243.120 ;
        RECT 3.990 240.400 595.600 241.720 ;
        RECT 4.400 239.000 595.600 240.400 ;
        RECT 3.990 237.680 595.600 239.000 ;
        RECT 4.400 236.280 595.600 237.680 ;
        RECT 3.990 234.960 595.600 236.280 ;
        RECT 4.400 233.560 595.600 234.960 ;
        RECT 3.990 232.240 595.600 233.560 ;
        RECT 4.400 230.840 595.600 232.240 ;
        RECT 3.990 229.520 595.600 230.840 ;
        RECT 4.400 228.120 595.600 229.520 ;
        RECT 3.990 226.800 595.600 228.120 ;
        RECT 4.400 225.400 595.600 226.800 ;
        RECT 3.990 224.080 595.600 225.400 ;
        RECT 4.400 222.680 595.600 224.080 ;
        RECT 3.990 221.360 595.600 222.680 ;
        RECT 4.400 219.960 595.600 221.360 ;
        RECT 3.990 218.640 595.600 219.960 ;
        RECT 4.400 217.240 595.600 218.640 ;
        RECT 3.990 215.920 595.600 217.240 ;
        RECT 4.400 214.520 595.600 215.920 ;
        RECT 3.990 213.200 595.600 214.520 ;
        RECT 4.400 211.800 595.600 213.200 ;
        RECT 3.990 210.480 595.600 211.800 ;
        RECT 4.400 209.080 595.600 210.480 ;
        RECT 3.990 207.760 595.600 209.080 ;
        RECT 4.400 206.360 595.600 207.760 ;
        RECT 3.990 205.040 595.600 206.360 ;
        RECT 4.400 203.640 595.600 205.040 ;
        RECT 3.990 202.320 595.600 203.640 ;
        RECT 4.400 200.920 595.600 202.320 ;
        RECT 3.990 199.600 595.600 200.920 ;
        RECT 4.400 198.200 595.600 199.600 ;
        RECT 3.990 196.880 595.600 198.200 ;
        RECT 4.400 195.480 595.600 196.880 ;
        RECT 3.990 194.160 595.600 195.480 ;
        RECT 4.400 192.760 595.600 194.160 ;
        RECT 3.990 191.440 595.600 192.760 ;
        RECT 4.400 190.040 595.600 191.440 ;
        RECT 3.990 188.720 595.600 190.040 ;
        RECT 4.400 187.320 595.600 188.720 ;
        RECT 3.990 186.000 595.600 187.320 ;
        RECT 4.400 184.600 595.600 186.000 ;
        RECT 3.990 183.280 595.600 184.600 ;
        RECT 4.400 181.880 595.600 183.280 ;
        RECT 3.990 180.560 595.600 181.880 ;
        RECT 4.400 179.160 595.600 180.560 ;
        RECT 3.990 177.840 595.600 179.160 ;
        RECT 4.400 176.440 595.600 177.840 ;
        RECT 3.990 175.120 595.600 176.440 ;
        RECT 4.400 173.720 595.600 175.120 ;
        RECT 3.990 172.400 595.600 173.720 ;
        RECT 4.400 171.000 595.600 172.400 ;
        RECT 3.990 169.680 595.600 171.000 ;
        RECT 4.400 168.280 595.600 169.680 ;
        RECT 3.990 166.960 595.600 168.280 ;
        RECT 4.400 165.560 595.600 166.960 ;
        RECT 3.990 164.240 595.600 165.560 ;
        RECT 4.400 162.840 595.600 164.240 ;
        RECT 3.990 161.520 595.600 162.840 ;
        RECT 4.400 160.120 595.600 161.520 ;
        RECT 3.990 158.800 595.600 160.120 ;
        RECT 4.400 157.400 595.600 158.800 ;
        RECT 3.990 156.080 595.600 157.400 ;
        RECT 4.400 154.680 595.600 156.080 ;
        RECT 3.990 153.360 595.600 154.680 ;
        RECT 4.400 151.960 595.600 153.360 ;
        RECT 3.990 150.640 595.600 151.960 ;
        RECT 4.400 149.240 595.600 150.640 ;
        RECT 3.990 147.920 595.600 149.240 ;
        RECT 4.400 146.520 595.600 147.920 ;
        RECT 3.990 145.200 595.600 146.520 ;
        RECT 4.400 143.800 595.600 145.200 ;
        RECT 3.990 142.480 595.600 143.800 ;
        RECT 4.400 141.080 595.600 142.480 ;
        RECT 3.990 139.760 595.600 141.080 ;
        RECT 4.400 138.360 595.600 139.760 ;
        RECT 3.990 137.040 595.600 138.360 ;
        RECT 4.400 135.640 595.600 137.040 ;
        RECT 3.990 134.320 595.600 135.640 ;
        RECT 4.400 132.920 595.600 134.320 ;
        RECT 3.990 131.600 595.600 132.920 ;
        RECT 4.400 130.200 595.600 131.600 ;
        RECT 3.990 128.880 595.600 130.200 ;
        RECT 4.400 127.480 595.600 128.880 ;
        RECT 3.990 126.160 595.600 127.480 ;
        RECT 4.400 124.760 595.600 126.160 ;
        RECT 3.990 123.440 595.600 124.760 ;
        RECT 4.400 122.040 595.600 123.440 ;
        RECT 3.990 120.720 595.600 122.040 ;
        RECT 4.400 119.320 595.600 120.720 ;
        RECT 3.990 118.000 595.600 119.320 ;
        RECT 4.400 116.600 595.600 118.000 ;
        RECT 3.990 115.280 595.600 116.600 ;
        RECT 4.400 113.880 595.600 115.280 ;
        RECT 3.990 112.560 595.600 113.880 ;
        RECT 4.400 111.160 595.600 112.560 ;
        RECT 3.990 109.840 595.600 111.160 ;
        RECT 4.400 108.440 595.600 109.840 ;
        RECT 3.990 107.120 595.600 108.440 ;
        RECT 4.400 105.720 595.600 107.120 ;
        RECT 3.990 104.400 595.600 105.720 ;
        RECT 4.400 103.000 595.600 104.400 ;
        RECT 3.990 101.680 595.600 103.000 ;
        RECT 4.400 100.280 595.600 101.680 ;
        RECT 3.990 98.960 595.600 100.280 ;
        RECT 4.400 97.560 595.600 98.960 ;
        RECT 3.990 96.240 595.600 97.560 ;
        RECT 4.400 94.840 595.600 96.240 ;
        RECT 3.990 93.520 595.600 94.840 ;
        RECT 4.400 92.120 595.600 93.520 ;
        RECT 3.990 90.800 595.600 92.120 ;
        RECT 4.400 89.400 595.600 90.800 ;
        RECT 3.990 88.080 595.600 89.400 ;
        RECT 4.400 86.680 595.600 88.080 ;
        RECT 3.990 85.360 595.600 86.680 ;
        RECT 4.400 83.960 595.600 85.360 ;
        RECT 3.990 82.640 595.600 83.960 ;
        RECT 4.400 81.240 595.600 82.640 ;
        RECT 3.990 79.920 595.600 81.240 ;
        RECT 4.400 78.520 595.600 79.920 ;
        RECT 3.990 77.200 595.600 78.520 ;
        RECT 4.400 75.800 595.600 77.200 ;
        RECT 3.990 74.480 595.600 75.800 ;
        RECT 4.400 73.080 595.600 74.480 ;
        RECT 3.990 71.760 595.600 73.080 ;
        RECT 4.400 70.360 595.600 71.760 ;
        RECT 3.990 69.040 595.600 70.360 ;
        RECT 4.400 67.640 595.600 69.040 ;
        RECT 3.990 66.320 595.600 67.640 ;
        RECT 4.400 64.920 595.600 66.320 ;
        RECT 3.990 63.600 595.600 64.920 ;
        RECT 4.400 62.200 595.600 63.600 ;
        RECT 3.990 60.880 595.600 62.200 ;
        RECT 4.400 59.480 595.600 60.880 ;
        RECT 3.990 58.160 595.600 59.480 ;
        RECT 4.400 56.760 595.600 58.160 ;
        RECT 3.990 55.440 595.600 56.760 ;
        RECT 4.400 54.040 595.600 55.440 ;
        RECT 3.990 52.720 595.600 54.040 ;
        RECT 4.400 51.320 595.600 52.720 ;
        RECT 3.990 50.000 595.600 51.320 ;
        RECT 4.400 48.600 595.600 50.000 ;
        RECT 3.990 47.280 595.600 48.600 ;
        RECT 4.400 45.880 595.600 47.280 ;
        RECT 3.990 44.560 595.600 45.880 ;
        RECT 4.400 43.160 595.600 44.560 ;
        RECT 3.990 41.840 595.600 43.160 ;
        RECT 4.400 40.440 595.600 41.840 ;
        RECT 3.990 39.120 595.600 40.440 ;
        RECT 4.400 37.720 595.600 39.120 ;
        RECT 3.990 36.400 595.600 37.720 ;
        RECT 4.400 35.000 595.600 36.400 ;
        RECT 3.990 33.680 595.600 35.000 ;
        RECT 4.400 32.280 595.600 33.680 ;
        RECT 3.990 30.960 595.600 32.280 ;
        RECT 4.400 29.560 595.600 30.960 ;
        RECT 3.990 28.240 595.600 29.560 ;
        RECT 4.400 26.840 595.600 28.240 ;
        RECT 3.990 25.520 595.600 26.840 ;
        RECT 4.400 24.120 595.600 25.520 ;
        RECT 3.990 22.800 595.600 24.120 ;
        RECT 4.400 21.400 595.600 22.800 ;
        RECT 3.990 20.080 595.600 21.400 ;
        RECT 4.400 18.680 595.600 20.080 ;
        RECT 3.990 17.360 595.600 18.680 ;
        RECT 4.400 15.960 595.600 17.360 ;
        RECT 3.990 14.640 595.600 15.960 ;
        RECT 4.400 13.240 595.600 14.640 ;
        RECT 3.990 11.920 595.600 13.240 ;
        RECT 4.400 10.520 595.600 11.920 ;
        RECT 3.990 8.335 596.000 10.520 ;
      LAYER met4 ;
        RECT 34.335 12.415 174.240 291.545 ;
        RECT 176.640 12.415 177.540 291.545 ;
        RECT 179.940 12.415 327.840 291.545 ;
        RECT 330.240 12.415 331.140 291.545 ;
        RECT 333.540 12.415 481.440 291.545 ;
        RECT 483.840 12.415 484.740 291.545 ;
        RECT 487.140 12.415 587.585 291.545 ;
  END
END main_busarb_m
END LIBRARY

